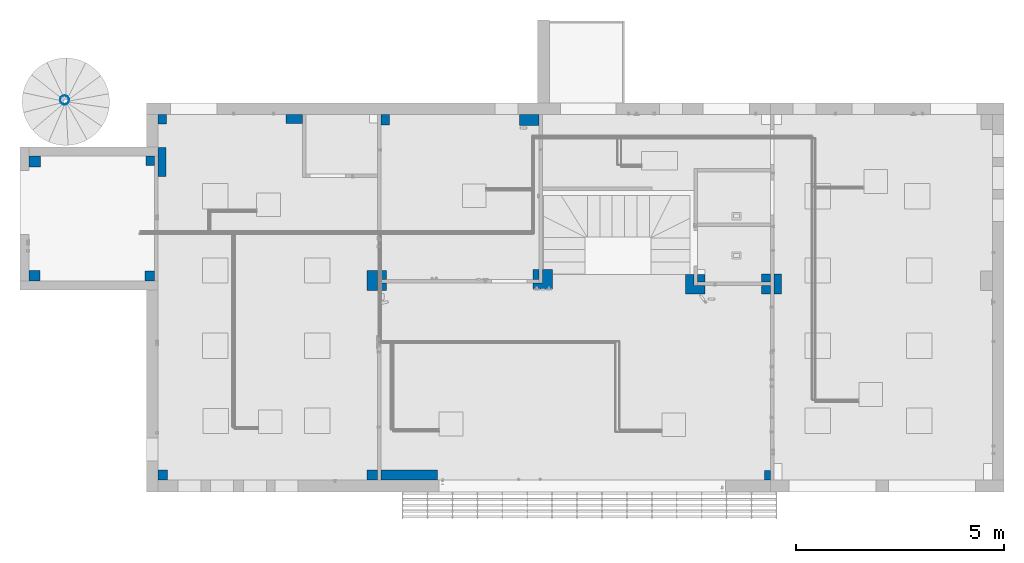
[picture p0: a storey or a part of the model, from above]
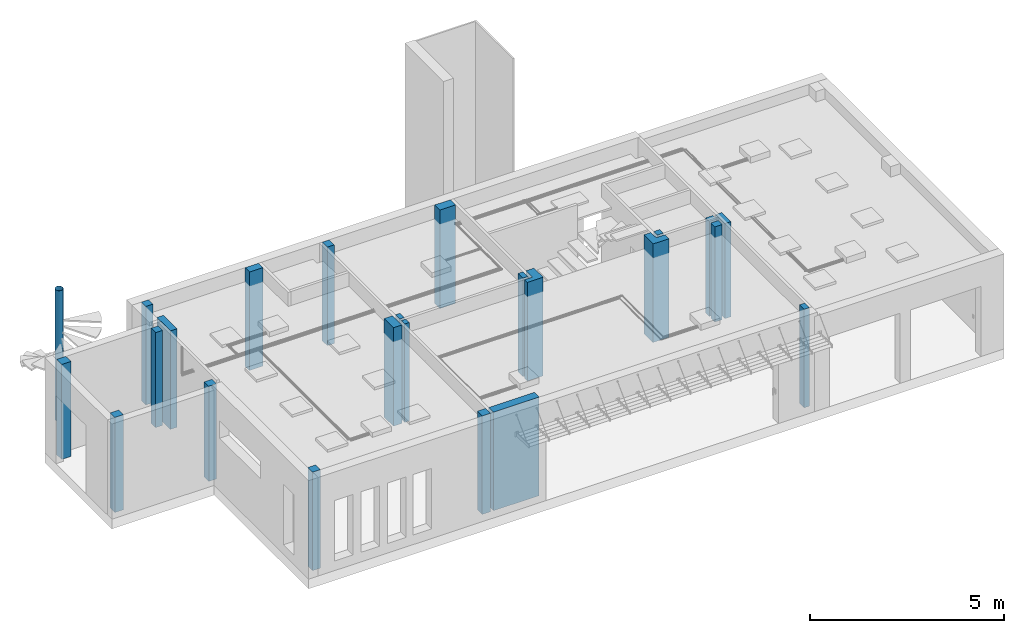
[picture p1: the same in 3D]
Properties of the parts of a building model (IFC2X3), part 1 of 5

# File
Description: ViewDefinition [CoordinationView_V2.0]
File name: Project Number
Time: 2023-02-07T13:56:00+02:00
Written by: ODA SDAI 22.12
Made in: 23.0.11.19 - Exporter 23.0.11.19 - Alternate UI 23.0.11.19

# IfcProject, Project Number
LongName: Project Name; Phase: Project Status

# IfcSite, Default
RefLatitude: 40, 38, 39, 763182; RefLongitude: 22, 55, 47, 232054; RefElevation: 0 mm
Pset_ProductRequirements - Category: Topography

# IfcSite: Surface:342065:342065 : Surface:342065, Surface:342065:342065 : Surface:342065:328022
Material: Earth 227
Pset_ProductRequirements - Category: Site

# IfcBuilding
Pset_BuildingCommon - NumberOfStoreys: 5
Pset_ProductRequirements - Category: Topography

# IfcBuildingStorey: Level:Circle Head - Project Datum (3)
Pset_ProductRequirements - Category: Levels
Name | LongName = Pset_AirSideSystemInformation, Name = Pset_ProductRequirements, Name | Elevation (mm)
Level 1 | Level 1 | 0
Level 2 | Level 2 | 3300
Top | Top | 6650

# IfcSpace: 10
In: Level 2
LongName: Bedroom First Floor; InteriorOrExteriorSpace: INTERNAL
Pset_AirSideSystemInformation - Name: Bedroom First Floor
Pset_ProductRequirements - Name: Bedroom First Floor; Category: Spaces
Pset_SpaceCommon - Reference: Bedroom First Floor 10; Category: Spaces

# IfcSpace: 11
In: Level 2
LongName: Game Room; InteriorOrExteriorSpace: INTERNAL
Pset_AirSideSystemInformation - Name: Game Room
Pset_ProductRequirements - Name: Game Room; Category: Spaces
Pset_SpaceCommon - Reference: Game Room 11; Category: Spaces

# IfcSpace: 12
In: Level 2
LongName: Double Bedroom; InteriorOrExteriorSpace: INTERNAL
Pset_AirSideSystemInformation - Name: Double Bedroom
Pset_ProductRequirements - Name: Double Bedroom; Category: Spaces
Pset_SpaceCommon - Reference: Double Bedroom 12; Category: Spaces

# IfcSpace: 13
In: Level 2
LongName: Bathroom Up; InteriorOrExteriorSpace: INTERNAL
Pset_AirSideSystemInformation - Name: Bathroom Up
Pset_ProductRequirements - Name: Bathroom Up; Category: Spaces
Pset_SpaceCommon - Reference: Bathroom Up 13; Category: Spaces

# IfcSpace: 15
In: Level 2
LongName: Hall up; InteriorOrExteriorSpace: INTERNAL
Pset_AirSideSystemInformation - Name: Hall up
Pset_ProductRequirements - Name: Hall up; Category: Spaces
Pset_SpaceCommon - Reference: Hall up 15; Category: Spaces

# IfcSpace: 2
In: Level 1
LongName: Control Room West; InteriorOrExteriorSpace: INTERNAL
Pset_AirSideSystemInformation - Name: Control Room West
Pset_ProductRequirements - Name: Control Room West; Category: Spaces
Pset_SpaceCommon - Reference: Control Room West 2; Category: Spaces

# IfcSpace: 3
In: Level 1
LongName: Bedroom; InteriorOrExteriorSpace: INTERNAL
Pset_AirSideSystemInformation - Name: Bedroom
Pset_ProductRequirements - Name: Bedroom; Category: Spaces
Pset_SpaceCommon - Reference: Bedroom 3; Category: Spaces

# IfcSpace: 33
In: Level 1
LongName: Plenum 1a; InteriorOrExteriorSpace: INTERNAL
Pset_AirSideSystemInformation - Name: Plenum 1a
Pset_ProductRequirements - Name: Plenum 1a; Category: Spaces
Pset_SpaceCommon - Reference: Plenum 1a 33; Category: Spaces

# IfcSpace: 34
In: Level 1
LongName: Plenum 1b; InteriorOrExteriorSpace: INTERNAL
Pset_AirSideSystemInformation - Name: Plenum 1b
Pset_ProductRequirements - Name: Plenum 1b; Category: Spaces
Pset_SpaceCommon - Reference: Plenum 1b 34; Category: Spaces

# IfcSpace: 35
In: Level 1
LongName: Plenum 1h; InteriorOrExteriorSpace: INTERNAL
Pset_AirSideSystemInformation - Name: Plenum 1h
Pset_ProductRequirements - Name: Plenum 1h; Category: Spaces
Pset_SpaceCommon - Reference: Plenum 1h 35; Category: Spaces

# IfcSpace: 36
In: Level 1
LongName: Plenum 1c; InteriorOrExteriorSpace: INTERNAL
Pset_AirSideSystemInformation - Name: Plenum 1c
Pset_ProductRequirements - Name: Plenum 1c; Category: Spaces
Pset_SpaceCommon - Reference: Plenum 1c 36; Category: Spaces

# IfcSpace: 37
In: Level 1
LongName: Plenum 1d; InteriorOrExteriorSpace: INTERNAL
Pset_AirSideSystemInformation - Name: Plenum 1d
Pset_ProductRequirements - Name: Plenum 1d; Category: Spaces
Pset_SpaceCommon - Reference: Plenum 1d 37; Category: Spaces

# IfcSpace: 38
In: Level 1
LongName: Plenum 1e; InteriorOrExteriorSpace: INTERNAL
Pset_AirSideSystemInformation - Name: Plenum 1e
Pset_ProductRequirements - Name: Plenum 1e; Category: Spaces
Pset_SpaceCommon - Reference: Plenum 1e 38; Category: Spaces

# IfcSpace: 39
In: Level 1
LongName: Plenum 1f; InteriorOrExteriorSpace: INTERNAL
Pset_AirSideSystemInformation - Name: Plenum 1f
Pset_ProductRequirements - Name: Plenum 1f; Category: Spaces
Pset_SpaceCommon - Reference: Plenum 1f 39; Category: Spaces

# IfcSpace: 4
In: Level 1
LongName: Living Room; InteriorOrExteriorSpace: INTERNAL
Pset_AirSideSystemInformation - Name: Living Room
Pset_ProductRequirements - Name: Living Room; Category: Spaces
Pset_SpaceCommon - Reference: Living Room 4; Category: Spaces

# IfcSpace: 40
In: Level 2
LongName: Plenum 2a; InteriorOrExteriorSpace: INTERNAL
Pset_AirSideSystemInformation - Name: Plenum 2a
Pset_ProductRequirements - Name: Plenum 2a; Category: Spaces
Pset_SpaceCommon - Reference: Plenum 2a 40; Category: Spaces

# IfcSpace: 41
In: Level 2
LongName: Plenum 2b; InteriorOrExteriorSpace: INTERNAL
Pset_AirSideSystemInformation - Name: Plenum 2b
Pset_ProductRequirements - Name: Plenum 2b; Category: Spaces
Pset_SpaceCommon - Reference: Plenum 2b 41; Category: Spaces

# IfcSpace: 42
In: Level 2
LongName: Plenum 2c; InteriorOrExteriorSpace: INTERNAL
Pset_AirSideSystemInformation - Name: Plenum 2c
Pset_ProductRequirements - Name: Plenum 2c; Category: Spaces
Pset_SpaceCommon - Reference: Plenum 2c 42; Category: Spaces

# IfcSpace: 43
In: Level 2
LongName: Plenum 2d; InteriorOrExteriorSpace: INTERNAL
Pset_AirSideSystemInformation - Name: Plenum 2d
Pset_ProductRequirements - Name: Plenum 2d; Category: Spaces
Pset_SpaceCommon - Reference: Plenum 2d 43; Category: Spaces

# IfcSpace: 44
In: Level 2
LongName: Plenum 2e; InteriorOrExteriorSpace: INTERNAL
Pset_AirSideSystemInformation - Name: Plenum 2e
Pset_ProductRequirements - Name: Plenum 2e; Category: Spaces
Pset_SpaceCommon - Reference: Plenum 2e 44; Category: Spaces

# IfcSpace: 45
In: Level 2
LongName: Plenum 2f; InteriorOrExteriorSpace: INTERNAL
Pset_AirSideSystemInformation - Name: Plenum 2f
Pset_ProductRequirements - Name: Plenum 2f; Category: Spaces
Pset_SpaceCommon - Reference: Plenum 2f 45; Category: Spaces

# IfcSpace: 46
In: Level 1
LongName: Plenum 1g; InteriorOrExteriorSpace: INTERNAL
Pset_AirSideSystemInformation - Name: Plenum 1g
Pset_ProductRequirements - Name: Plenum 1g; Category: Spaces
Pset_SpaceCommon - Reference: Plenum 1g 46; Category: Spaces

# IfcSpace: 47
In: Level 1
LongName: Stairs; InteriorOrExteriorSpace: INTERNAL
Pset_AirSideSystemInformation - Name: Stairs
Pset_ProductRequirements - Name: Stairs; Category: Spaces
Pset_SpaceCommon - Reference: Stairs 47; Category: Spaces

# IfcSpace: 48
In: Level 1
LongName: Engine Room; InteriorOrExteriorSpace: INTERNAL
Pset_AirSideSystemInformation - Name: Engine Room
Pset_ProductRequirements - Name: Engine Room; Category: Spaces
Pset_SpaceCommon - Reference: Engine Room 48; Category: Spaces

# IfcSpace: 49
In: Level 1
LongName: Space; InteriorOrExteriorSpace: INTERNAL
Pset_AirSideSystemInformation - Name: Space
Pset_ProductRequirements - Name: Space; Category: Spaces
Pset_SpaceCommon - Reference: Space 49; Category: Spaces

# IfcSpace: 5
In: Level 1
LongName: WC1; InteriorOrExteriorSpace: INTERNAL
Pset_AirSideSystemInformation - Name: WC1
Pset_ProductRequirements - Name: WC1; Category: Spaces
Pset_SpaceCommon - Reference: WC1 5; Category: Spaces

# IfcSpace: 6
In: Level 1
LongName: WC2; InteriorOrExteriorSpace: INTERNAL
Pset_AirSideSystemInformation - Name: WC2
Pset_ProductRequirements - Name: WC2; Category: Spaces
Pset_SpaceCommon - Reference: WC2 6; Category: Spaces

# IfcSpace: 7
In: Level 1
LongName: WC3; InteriorOrExteriorSpace: INTERNAL
Pset_AirSideSystemInformation - Name: WC3
Pset_ProductRequirements - Name: WC3; Category: Spaces
Pset_SpaceCommon - Reference: WC3 7; Category: Spaces

# IfcSpace: 9
In: Level 2
LongName: Demo Room; InteriorOrExteriorSpace: INTERNAL
Pset_AirSideSystemInformation - Name: Demo Room
Pset_ProductRequirements - Name: Demo Room; Category: Spaces
Pset_SpaceCommon - Reference: Demo Room 9; Category: Spaces

# IfcBuildingElementProxy: Alumil Chic no lock:Alumil Chic no lock:1027049:Alumil Chic no lock:1027049 : Alumil Chic no lock:Alumil Chic no lock:1027049:326691, Alumil Chic no lock:Alumil Chic no lock:1027049:Alumil Chic no lock:1027049 : Alumil Chic no lock:Alumil Chic no lock:1027049:326691:Alumil Chic no lock:1027049:Alumil Chic no lock:1027049 : Alumil Chic no lock:Alumil Chic no lock:1027049:326691 : Alumil Chic no lock:Alumil Chic no lock:1027049:Alumil Chic no lock:1027049 : Alumil Chic no lock:Alumil Chic no lock:1027049:326691:326029
In: Level 2
Type - Material: Polished Steel (5)
Type - Pset_BuildingElementProxyCommon - Reference: Alumil Chic no lock
Type - Pset_ProductRequirements - Category: Generic Models
Type - Pset_QuantityTakeOff - Reference: Alumil Chic no lock
Type - Pset_ProvisionForVoid - Width: 34 mm; Height: 14.0853 mm; Depth: 14.0853 mm
Pset_BuildingElementProxyCommon - sets with these values: 2
Pset_ProvisionForVoid - Width: 0.0103632 mm

# IfcBuildingElementProxy: Alumil Chic:Alumil Chic:1027241:Alumil Chic:1027241 : Alumil Chic:Alumil Chic:1027241:322622, Alumil Chic:Alumil Chic:1027241:Alumil Chic:1027241 : Alumil Chic:Alumil Chic:1027241:322622:Alumil Chic:1027241:Alumil Chic:1027241 : Alumil Chic:Alumil Chic:1027241:322622 : Alumil Chic:Alumil Chic:1027241:Alumil Chic:1027241 : Alumil Chic:Alumil Chic:1027241:322622:322399
In: Level 1
Type - Material: Polished Steel (9)
Type - Pset_BuildingElementProxyCommon - Reference: Alumil Chic
Type - Pset_ProductRequirements - Category: Generic Models
Type - Pset_QuantityTakeOff - Reference: Alumil Chic
Type - Pset_ProvisionForVoid - Width: 126.361 mm; Height: 34 mm; Depth: 4.01325 mm
Pset_BuildingElementProxyCommon - sets with these values: 2
Pset_ProvisionForVoid - Width: 0.038515 mm

# IfcBuildingElementProxy: Alumil Chic:Alumil Chic:1027242:Alumil Chic:1027242 : Alumil Chic:Alumil Chic:1027242:322710, Alumil Chic:Alumil Chic:1027242:Alumil Chic:1027242 : Alumil Chic:Alumil Chic:1027242:322710:Alumil Chic:1027242:Alumil Chic:1027242 : Alumil Chic:Alumil Chic:1027242:322710 : Alumil Chic:Alumil Chic:1027242:Alumil Chic:1027242 : Alumil Chic:Alumil Chic:1027242:322710:322488
In: Level 1
Type - Material: Polished Steel (9)
Type - Pset_BuildingElementProxyCommon - Reference: Alumil Chic
Type - Pset_ProductRequirements - Category: Generic Models
Type - Pset_QuantityTakeOff - Reference: Alumil Chic
Type - Pset_ProvisionForVoid - Width: 126.361 mm; Height: 34 mm; Depth: 4.01325 mm
Pset_BuildingElementProxyCommon - sets with these values: 2
Pset_ProvisionForVoid - Width: 0.038515 mm

# IfcBuildingElementProxy: Camera ORBBEC v1:Camera ORBBEC v1:1027540:Camera ORBBEC v1:1027540 : Camera ORBBEC v1:Camera ORBBEC v1:1027540:324731, Camera ORBBEC v1:Camera ORBBEC v1:1027540:Camera ORBBEC v1:1027540 : Camera ORBBEC v1:Camera ORBBEC v1:1027540:324731:Camera ORBBEC v1:1027540:Camera ORBBEC v1:1027540 : Camera ORBBEC v1:Camera ORBBEC v1:1027540:324731 : Camera ORBBEC v1:Camera ORBBEC v1:1027540:Camera ORBBEC v1:1027540 : Camera ORBBEC v1:Camera ORBBEC v1:1027540:324731:325063
In: Level 1
Type - Material: Plastic - Sony - Black_Matt (4)
Type - Pset_BuildingElementProxyCommon - Reference: Camera ORBBEC v1
Type - Pset_ManufacturerTypeInformation - Manufacturer: Orbbec
Type - Pset_ProductRequirements - Category: Specialty Equipment
Type - Pset_QuantityTakeOff - Reference: Camera ORBBEC v1
Type - Pset_ProvisionForVoid - Depth: 2 mm
Pset_BuildingElementProxyCommon - sets with these values: 2
Pset_ProductRequirements - Category: Generic Models

# IfcBuildingElementProxy: Camera ORBBEC v1:Camera ORBBEC v1:1027541:Camera ORBBEC v1:1027541 : Camera ORBBEC v1:Camera ORBBEC v1:1027541:324770, Camera ORBBEC v1:Camera ORBBEC v1:1027541:Camera ORBBEC v1:1027541 : Camera ORBBEC v1:Camera ORBBEC v1:1027541:324770:Camera ORBBEC v1:1027541:Camera ORBBEC v1:1027541 : Camera ORBBEC v1:Camera ORBBEC v1:1027541:324770 : Camera ORBBEC v1:Camera ORBBEC v1:1027541:Camera ORBBEC v1:1027541 : Camera ORBBEC v1:Camera ORBBEC v1:1027541:324770:325102
In: Level 1
Type - Material: Plastic - Sony - Black_Matt (4)
Type - Pset_BuildingElementProxyCommon - Reference: Camera ORBBEC v1
Type - Pset_ManufacturerTypeInformation - Manufacturer: Orbbec
Type - Pset_ProductRequirements - Category: Specialty Equipment
Type - Pset_QuantityTakeOff - Reference: Camera ORBBEC v1
Type - Pset_ProvisionForVoid - Depth: 2 mm
Pset_BuildingElementProxyCommon - sets with these values: 2
Pset_ProductRequirements - Category: Generic Models

# IfcBuildingElementProxy: Camera ORBBEC v1:Camera ORBBEC v1:1027546:Camera ORBBEC v1:1027546 : Camera ORBBEC v1:Camera ORBBEC v1:1027546:324823, Camera ORBBEC v1:Camera ORBBEC v1:1027546:Camera ORBBEC v1:1027546 : Camera ORBBEC v1:Camera ORBBEC v1:1027546:324823:Camera ORBBEC v1:1027546:Camera ORBBEC v1:1027546 : Camera ORBBEC v1:Camera ORBBEC v1:1027546:324823 : Camera ORBBEC v1:Camera ORBBEC v1:1027546:Camera ORBBEC v1:1027546 : Camera ORBBEC v1:Camera ORBBEC v1:1027546:324823:325155
In: Level 1
Type - Material: Plastic - Sony - Black_Matt (4)
Type - Pset_BuildingElementProxyCommon - Reference: Camera ORBBEC v1
Type - Pset_ManufacturerTypeInformation - Manufacturer: Orbbec
Type - Pset_ProductRequirements - Category: Specialty Equipment
Type - Pset_QuantityTakeOff - Reference: Camera ORBBEC v1
Type - Pset_ProvisionForVoid - Depth: 2 mm
Pset_BuildingElementProxyCommon - sets with these values: 2
Pset_ProductRequirements - Category: Generic Models

# IfcBuildingElementProxy: Camera ORBBEC v1:Camera ORBBEC v1:1027547:Camera ORBBEC v1:1027547 : Camera ORBBEC v1:Camera ORBBEC v1:1027547:324862, Camera ORBBEC v1:Camera ORBBEC v1:1027547:Camera ORBBEC v1:1027547 : Camera ORBBEC v1:Camera ORBBEC v1:1027547:324862:Camera ORBBEC v1:1027547:Camera ORBBEC v1:1027547 : Camera ORBBEC v1:Camera ORBBEC v1:1027547:324862 : Camera ORBBEC v1:Camera ORBBEC v1:1027547:Camera ORBBEC v1:1027547 : Camera ORBBEC v1:Camera ORBBEC v1:1027547:324862:325194
In: Level 1
Type - Material: Plastic - Sony - Black_Matt (4)
Type - Pset_BuildingElementProxyCommon - Reference: Camera ORBBEC v1
Type - Pset_ManufacturerTypeInformation - Manufacturer: Orbbec
Type - Pset_ProductRequirements - Category: Specialty Equipment
Type - Pset_QuantityTakeOff - Reference: Camera ORBBEC v1
Type - Pset_ProvisionForVoid - Depth: 2 mm
Pset_BuildingElementProxyCommon - sets with these values: 2
Pset_ProductRequirements - Category: Generic Models

# IfcBuildingElementProxy: Camera ORBBEC v1:Camera ORBBEC v1:1027552:Camera ORBBEC v1:1027552 : Camera ORBBEC v1:Camera ORBBEC v1:1027552:324015, Camera ORBBEC v1:Camera ORBBEC v1:1027552:Camera ORBBEC v1:1027552 : Camera ORBBEC v1:Camera ORBBEC v1:1027552:324015:Camera ORBBEC v1:1027552:Camera ORBBEC v1:1027552 : Camera ORBBEC v1:Camera ORBBEC v1:1027552:324015 : Camera ORBBEC v1:Camera ORBBEC v1:1027552:Camera ORBBEC v1:1027552 : Camera ORBBEC v1:Camera ORBBEC v1:1027552:324015:324971
In: Level 1
Type - Material: Plastic - Sony - Black_Matt (4)
Type - Pset_BuildingElementProxyCommon - Reference: Camera ORBBEC v1
Type - Pset_ManufacturerTypeInformation - Manufacturer: Orbbec
Type - Pset_ProductRequirements - Category: Specialty Equipment
Type - Pset_QuantityTakeOff - Reference: Camera ORBBEC v1
Type - Pset_ProvisionForVoid - Depth: 2 mm
Pset_BuildingElementProxyCommon - sets with these values: 2
Pset_ProductRequirements - Category: Generic Models

# IfcBuildingElementProxy: Compound Ceiling:My ceiling mineral fiber mpania:1026756:My ceiling mineral fiber mpania:1026756 : Compound Ceiling:My ceiling mineral fiber mpania:1026756:321788, Compound Ceiling:My ceiling mineral fiber mpania:1026756:My ceiling mineral fiber mpania:1026756 : Compound Ceiling:My ceiling mineral fiber mpania:1026756:321788:My ceiling mineral fiber mpania:1026756:My ceiling mineral fiber mpania:1026756 : Compound Ceiling:My ceiling mineral fiber mpania:1026756:321788 : Compound Ceiling:My ceiling mineral fiber mpania:1026756:My ceiling mineral fiber mpania:1026756 : Compound Ceiling:My ceiling mineral fiber mpania:1026756:321788:321591
In: Level 1
Type - Material: Ceiling Tile 600 x 600
Type - Pset_BuildingElementProxyCommon - Reference: My ceiling mineral fiber mpania
Type - Pset_ProductRequirements - Category: Ceilings
Type - Pset_QuantityTakeOff - Reference: My ceiling mineral fiber mpania
Type - Pset_ProvisionForVoid - Depth: 57 mm
Pset_BuildingElementProxyCommon - sets with these values: 2
Pset_ProductRequirements - Category: Generic Models

# IfcBuildingElementProxy: Compound Ceiling:My ceiling mineral fiber mpania:1026769:My ceiling mineral fiber mpania:1026769 : Compound Ceiling:My ceiling mineral fiber mpania:1026769:321804, Compound Ceiling:My ceiling mineral fiber mpania:1026769:My ceiling mineral fiber mpania:1026769 : Compound Ceiling:My ceiling mineral fiber mpania:1026769:321804:My ceiling mineral fiber mpania:1026769:My ceiling mineral fiber mpania:1026769 : Compound Ceiling:My ceiling mineral fiber mpania:1026769:321804 : Compound Ceiling:My ceiling mineral fiber mpania:1026769:My ceiling mineral fiber mpania:1026769 : Compound Ceiling:My ceiling mineral fiber mpania:1026769:321804:321607
In: Level 1
Type - Material: Ceiling Tile 600 x 600
Type - Pset_BuildingElementProxyCommon - Reference: My ceiling mineral fiber mpania
Type - Pset_ProductRequirements - Category: Ceilings
Type - Pset_QuantityTakeOff - Reference: My ceiling mineral fiber mpania
Type - Pset_ProvisionForVoid - Depth: 57 mm
Pset_BuildingElementProxyCommon - sets with these values: 2
Pset_ProductRequirements - Category: Generic Models

# IfcBuildingElementProxy: Compound Ceiling:My ceiling mineral fiber mpania:1026845:My ceiling mineral fiber mpania:1026845 : Compound Ceiling:My ceiling mineral fiber mpania:1026845:326623, Compound Ceiling:My ceiling mineral fiber mpania:1026845:My ceiling mineral fiber mpania:1026845 : Compound Ceiling:My ceiling mineral fiber mpania:1026845:326623:My ceiling mineral fiber mpania:1026845:My ceiling mineral fiber mpania:1026845 : Compound Ceiling:My ceiling mineral fiber mpania:1026845:326623 : Compound Ceiling:My ceiling mineral fiber mpania:1026845:My ceiling mineral fiber mpania:1026845 : Compound Ceiling:My ceiling mineral fiber mpania:1026845:326623:325963
In: Level 2
Type - Material: Ceiling Tile 600 x 600
Type - Pset_BuildingElementProxyCommon - Reference: My ceiling mineral fiber mpania
Type - Pset_ProductRequirements - Category: Ceilings
Type - Pset_QuantityTakeOff - Reference: My ceiling mineral fiber mpania
Type - Pset_ProvisionForVoid - Depth: 57 mm
Pset_BuildingElementProxyCommon - sets with these values: 2
Pset_ProductRequirements - Category: Generic Models

# IfcBuildingElementProxy: Compound Ceiling:My ceiling mineral fiber:1026741:My ceiling mineral fiber:1026741 : Compound Ceiling:My ceiling mineral fiber:1026741:321752, Compound Ceiling:My ceiling mineral fiber:1026741:My ceiling mineral fiber:1026741 : Compound Ceiling:My ceiling mineral fiber:1026741:321752:My ceiling mineral fiber:1026741:My ceiling mineral fiber:1026741 : Compound Ceiling:My ceiling mineral fiber:1026741:321752 : Compound Ceiling:My ceiling mineral fiber:1026741:My ceiling mineral fiber:1026741 : Compound Ceiling:My ceiling mineral fiber:1026741:321752:321562
In: Level 1
Type - Material: Ceiling Tile 600 x 600
Type - Pset_BuildingElementProxyCommon - Reference: My ceiling mineral fiber
Type - Pset_ProductRequirements - Category: Ceilings
Type - Pset_QuantityTakeOff - Reference: My ceiling mineral fiber
Type - Pset_ProvisionForVoid - Depth: 57 mm
Pset_BuildingElementProxyCommon - sets with these values: 2
Pset_ProductRequirements - Category: Generic Models

# IfcBuildingElementProxy: Compound Ceiling:My ceiling mineral fiber:1026780:My ceiling mineral fiber:1026780 : Compound Ceiling:My ceiling mineral fiber:1026780:326517, Compound Ceiling:My ceiling mineral fiber:1026780:My ceiling mineral fiber:1026780 : Compound Ceiling:My ceiling mineral fiber:1026780:326517:My ceiling mineral fiber:1026780:My ceiling mineral fiber:1026780 : Compound Ceiling:My ceiling mineral fiber:1026780:326517 : Compound Ceiling:My ceiling mineral fiber:1026780:My ceiling mineral fiber:1026780 : Compound Ceiling:My ceiling mineral fiber:1026780:326517:325857
In: Level 2
Type - Material: Ceiling Tile 600 x 600
Type - Pset_BuildingElementProxyCommon - Reference: My ceiling mineral fiber
Type - Pset_ProductRequirements - Category: Ceilings
Type - Pset_QuantityTakeOff - Reference: My ceiling mineral fiber
Type - Pset_ProvisionForVoid - Depth: 57 mm
Pset_BuildingElementProxyCommon - sets with these values: 2
Pset_ProductRequirements - Category: Generic Models

# IfcBuildingElementProxy: Compound Ceiling:My ceiling mineral fiber:1026814:My ceiling mineral fiber:1026814 : Compound Ceiling:My ceiling mineral fiber:1026814:326583, Compound Ceiling:My ceiling mineral fiber:1026814:My ceiling mineral fiber:1026814 : Compound Ceiling:My ceiling mineral fiber:1026814:326583:My ceiling mineral fiber:1026814:My ceiling mineral fiber:1026814 : Compound Ceiling:My ceiling mineral fiber:1026814:326583 : Compound Ceiling:My ceiling mineral fiber:1026814:My ceiling mineral fiber:1026814 : Compound Ceiling:My ceiling mineral fiber:1026814:326583:325923
In: Level 2
Type - Material: Ceiling Tile 600 x 600
Type - Pset_BuildingElementProxyCommon - Reference: My ceiling mineral fiber
Type - Pset_ProductRequirements - Category: Ceilings
Type - Pset_QuantityTakeOff - Reference: My ceiling mineral fiber
Type - Pset_ProvisionForVoid - Depth: 57 mm
Pset_BuildingElementProxyCommon - sets with these values: 2
Pset_ProductRequirements - Category: Generic Models

# IfcBuildingElementProxy: Compound Ceiling:My ceiling mineral fiber:1026827:My ceiling mineral fiber:1026827 : Compound Ceiling:My ceiling mineral fiber:1026827:326603, Compound Ceiling:My ceiling mineral fiber:1026827:My ceiling mineral fiber:1026827 : Compound Ceiling:My ceiling mineral fiber:1026827:326603:My ceiling mineral fiber:1026827:My ceiling mineral fiber:1026827 : Compound Ceiling:My ceiling mineral fiber:1026827:326603 : Compound Ceiling:My ceiling mineral fiber:1026827:My ceiling mineral fiber:1026827 : Compound Ceiling:My ceiling mineral fiber:1026827:326603:325943
In: Level 2
Type - Material: Ceiling Tile 600 x 600
Type - Pset_BuildingElementProxyCommon - Reference: My ceiling mineral fiber
Type - Pset_ProductRequirements - Category: Ceilings
Type - Pset_QuantityTakeOff - Reference: My ceiling mineral fiber
Type - Pset_ProvisionForVoid - Depth: 57 mm
Pset_BuildingElementProxyCommon - sets with these values: 2
Pset_ProductRequirements - Category: Generic Models

# IfcBuildingElementProxy: Compound Ceiling:My ceiling mineral fiber:1026868:My ceiling mineral fiber:1026868 : Compound Ceiling:My ceiling mineral fiber:1026868:326647, Compound Ceiling:My ceiling mineral fiber:1026868:My ceiling mineral fiber:1026868 : Compound Ceiling:My ceiling mineral fiber:1026868:326647:My ceiling mineral fiber:1026868:My ceiling mineral fiber:1026868 : Compound Ceiling:My ceiling mineral fiber:1026868:326647 : Compound Ceiling:My ceiling mineral fiber:1026868:My ceiling mineral fiber:1026868 : Compound Ceiling:My ceiling mineral fiber:1026868:326647:325987
In: Level 2
Type - Material: Ceiling Tile 600 x 600
Type - Pset_BuildingElementProxyCommon - Reference: My ceiling mineral fiber
Type - Pset_ProductRequirements - Category: Ceilings
Type - Pset_QuantityTakeOff - Reference: My ceiling mineral fiber
Type - Pset_ProvisionForVoid - Depth: 57 mm
Pset_BuildingElementProxyCommon - sets with these values: 2
Pset_ProductRequirements - Category: Generic Models

# IfcBuildingElementProxy: Compound Ceiling:My ceiling mineral fiber:1026892:My ceiling mineral fiber:1026892 : Compound Ceiling:My ceiling mineral fiber:1026892:326669, Compound Ceiling:My ceiling mineral fiber:1026892:My ceiling mineral fiber:1026892 : Compound Ceiling:My ceiling mineral fiber:1026892:326669:My ceiling mineral fiber:1026892:My ceiling mineral fiber:1026892 : Compound Ceiling:My ceiling mineral fiber:1026892:326669 : Compound Ceiling:My ceiling mineral fiber:1026892:My ceiling mineral fiber:1026892 : Compound Ceiling:My ceiling mineral fiber:1026892:326669:326009
In: Level 2
Type - Material: Ceiling Tile 600 x 600
Type - Pset_BuildingElementProxyCommon - Reference: My ceiling mineral fiber
Type - Pset_ProductRequirements - Category: Ceilings
Type - Pset_QuantityTakeOff - Reference: My ceiling mineral fiber
Type - Pset_ProvisionForVoid - Depth: 57 mm
Pset_BuildingElementProxyCommon - sets with these values: 2
Pset_ProductRequirements - Category: Generic Models

# IfcBuildingElementProxy: Compound Ceiling:My ceiling mineral fiber:1026909:My ceiling mineral fiber:1026909 : Compound Ceiling:My ceiling mineral fiber:1026909:321822, Compound Ceiling:My ceiling mineral fiber:1026909:My ceiling mineral fiber:1026909 : Compound Ceiling:My ceiling mineral fiber:1026909:321822:My ceiling mineral fiber:1026909:My ceiling mineral fiber:1026909 : Compound Ceiling:My ceiling mineral fiber:1026909:321822 : Compound Ceiling:My ceiling mineral fiber:1026909:My ceiling mineral fiber:1026909 : Compound Ceiling:My ceiling mineral fiber:1026909:321822:321625
In: Level 1
Type - Material: Ceiling Tile 600 x 600
Type - Pset_BuildingElementProxyCommon - Reference: My ceiling mineral fiber
Type - Pset_ProductRequirements - Category: Ceilings
Type - Pset_QuantityTakeOff - Reference: My ceiling mineral fiber
Type - Pset_ProvisionForVoid - Depth: 57 mm
Pset_BuildingElementProxyCommon - sets with these values: 2
Pset_ProductRequirements - Category: Generic Models

# IfcBuildingElementProxy: Compound Ceiling:My ceiling mineral fiber:1027013:My ceiling mineral fiber:1027013 : Compound Ceiling:My ceiling mineral fiber:1027013:321842, Compound Ceiling:My ceiling mineral fiber:1027013:My ceiling mineral fiber:1027013 : Compound Ceiling:My ceiling mineral fiber:1027013:321842:My ceiling mineral fiber:1027013:My ceiling mineral fiber:1027013 : Compound Ceiling:My ceiling mineral fiber:1027013:321842 : Compound Ceiling:My ceiling mineral fiber:1027013:My ceiling mineral fiber:1027013 : Compound Ceiling:My ceiling mineral fiber:1027013:321842:321645
In: Level 1
Type - Material: Ceiling Tile 600 x 600
Type - Pset_BuildingElementProxyCommon - Reference: My ceiling mineral fiber
Type - Pset_ProductRequirements - Category: Ceilings
Type - Pset_QuantityTakeOff - Reference: My ceiling mineral fiber
Type - Pset_ProvisionForVoid - Width: 1225.48 mm; Height: 1759 mm; Depth: 57 mm
Pset_BuildingElementProxyCommon - sets with these values: 2
Pset_ProductRequirements - Category: Generic Models
Pset_ProvisionForVoid - Width: 0.373527 mm

# IfcBuildingElementProxy: Compound Ceiling:My ceiling mineral fiber:1027159:My ceiling mineral fiber:1027159 : Compound Ceiling:My ceiling mineral fiber:1027159:322520, Compound Ceiling:My ceiling mineral fiber:1027159:My ceiling mineral fiber:1027159 : Compound Ceiling:My ceiling mineral fiber:1027159:322520:My ceiling mineral fiber:1027159:My ceiling mineral fiber:1027159 : Compound Ceiling:My ceiling mineral fiber:1027159:322520 : Compound Ceiling:My ceiling mineral fiber:1027159:My ceiling mineral fiber:1027159 : Compound Ceiling:My ceiling mineral fiber:1027159:322520:322307
In: Level 1
Type - Material: Ceiling Tile 600 x 600
Type - Pset_BuildingElementProxyCommon - Reference: My ceiling mineral fiber
Type - Pset_ProductRequirements - Category: Ceilings
Type - Pset_QuantityTakeOff - Reference: My ceiling mineral fiber
Type - Pset_ProvisionForVoid - Depth: 57 mm
Pset_BuildingElementProxyCommon - sets with these values: 2
Pset_ProductRequirements - Category: Generic Models

# IfcBuildingElementProxy: Compound Ceiling:My ceiling mineral fiber:1027182:My ceiling mineral fiber:1027182 : Compound Ceiling:My ceiling mineral fiber:1027182:322582, Compound Ceiling:My ceiling mineral fiber:1027182:My ceiling mineral fiber:1027182 : Compound Ceiling:My ceiling mineral fiber:1027182:322582:My ceiling mineral fiber:1027182:My ceiling mineral fiber:1027182 : Compound Ceiling:My ceiling mineral fiber:1027182:322582 : Compound Ceiling:My ceiling mineral fiber:1027182:My ceiling mineral fiber:1027182 : Compound Ceiling:My ceiling mineral fiber:1027182:322582:322369
In: Level 1
Type - Material: Ceiling Tile 600 x 600
Type - Pset_BuildingElementProxyCommon - Reference: My ceiling mineral fiber
Type - Pset_ProductRequirements - Category: Ceilings
Type - Pset_QuantityTakeOff - Reference: My ceiling mineral fiber
Type - Pset_ProvisionForVoid - Depth: 57 mm
Pset_BuildingElementProxyCommon - sets with these values: 2
Pset_ProductRequirements - Category: Generic Models

# IfcBuildingElementProxy: Compound Ceiling:My ceiling mineral fiber:1027328:My ceiling mineral fiber:1027328 : Compound Ceiling:My ceiling mineral fiber:1027328:322800, Compound Ceiling:My ceiling mineral fiber:1027328:My ceiling mineral fiber:1027328 : Compound Ceiling:My ceiling mineral fiber:1027328:322800:My ceiling mineral fiber:1027328:My ceiling mineral fiber:1027328 : Compound Ceiling:My ceiling mineral fiber:1027328:322800 : Compound Ceiling:My ceiling mineral fiber:1027328:My ceiling mineral fiber:1027328 : Compound Ceiling:My ceiling mineral fiber:1027328:322800:322576
In: Level 1
Type - Material: Ceiling Tile 600 x 600
Type - Pset_BuildingElementProxyCommon - Reference: My ceiling mineral fiber
Type - Pset_ProductRequirements - Category: Ceilings
Type - Pset_QuantityTakeOff - Reference: My ceiling mineral fiber
Type - Pset_ProvisionForVoid - Depth: 57 mm
Pset_BuildingElementProxyCommon - sets with these values: 2
Pset_ProductRequirements - Category: Generic Models

# IfcBuildingElementProxy: Electrical_Controls_Fibaro_Motion-sensor.eng:Default:1027543:Default:1027543 : Electrical_Controls_Fibaro_Motion-sensor.eng:Default:1027543:324809, Electrical_Controls_Fibaro_Motion-sensor.eng:Default:1027543:Default:1027543 : Electrical_Controls_Fibaro_Motion-sensor.eng:Default:1027543:324809:Default:1027543:Default:1027543 : Electrical_Controls_Fibaro_Motion-sensor.eng:Default:1027543:324809 : Electrical_Controls_Fibaro_Motion-sensor.eng:Default:1027543:Default:1027543 : Electrical_Controls_Fibaro_Motion-sensor.eng:Default:1027543:324809:325141
In: Level 1
Type - Material: Fibaro_glossywhite 7ECA5D70
Type - Pset_BuildingElementProxyCommon - Reference: Default
Type - Pset_ProductRequirements - Category: Electrical Equipment
Type - Pset_QuantityTakeOff - Reference: Default
Material: Fibaro_blue 127BC1BD, Fibaro_transparent 1B44B9A5, Fibaro_glossywhite 7ECA5D70
Pset_BuildingElementProxyCommon - sets with these values: 2
Pset_ProductRequirements - Category: Generic Models

# IfcBuildingElementProxy: Electrical_Controls_Fibaro_Motion-sensor.eng:Default:1027545:Default:1027545 : Electrical_Controls_Fibaro_Motion-sensor.eng:Default:1027545:324816, Electrical_Controls_Fibaro_Motion-sensor.eng:Default:1027545:Default:1027545 : Electrical_Controls_Fibaro_Motion-sensor.eng:Default:1027545:324816:Default:1027545:Default:1027545 : Electrical_Controls_Fibaro_Motion-sensor.eng:Default:1027545:324816 : Electrical_Controls_Fibaro_Motion-sensor.eng:Default:1027545:Default:1027545 : Electrical_Controls_Fibaro_Motion-sensor.eng:Default:1027545:324816:325148
In: Level 1
Type - Material: Fibaro_glossywhite 7ECA5D70
Type - Pset_BuildingElementProxyCommon - Reference: Default
Type - Pset_ProductRequirements - Category: Electrical Equipment
Type - Pset_QuantityTakeOff - Reference: Default
Material: Fibaro_blue 127BC1BD, Fibaro_transparent 1B44B9A5, Fibaro_glossywhite 7ECA5D70
Pset_BuildingElementProxyCommon - sets with these values: 2
Pset_ProductRequirements - Category: Generic Models

# IfcBuildingElementProxy: Electrical_Controls_Fibaro_Motion-sensor.eng:Default:1027550:Default:1027550 : Electrical_Controls_Fibaro_Motion-sensor.eng:Default:1027550:324931, Electrical_Controls_Fibaro_Motion-sensor.eng:Default:1027550:Default:1027550 : Electrical_Controls_Fibaro_Motion-sensor.eng:Default:1027550:324931:Default:1027550:Default:1027550 : Electrical_Controls_Fibaro_Motion-sensor.eng:Default:1027550:324931 : Electrical_Controls_Fibaro_Motion-sensor.eng:Default:1027550:Default:1027550 : Electrical_Controls_Fibaro_Motion-sensor.eng:Default:1027550:324931:325263
In: Level 1
Type - Material: Fibaro_glossywhite 7ECA5D70
Type - Pset_BuildingElementProxyCommon - Reference: Default
Type - Pset_ProductRequirements - Category: Electrical Equipment
Type - Pset_QuantityTakeOff - Reference: Default
Material: Fibaro_blue 127BC1BD, Fibaro_transparent 1B44B9A5, Fibaro_glossywhite 7ECA5D70
Pset_BuildingElementProxyCommon - sets with these values: 2
Pset_ProductRequirements - Category: Generic Models

# IfcBuildingElementProxy: Electrical_Controls_Fibaro_Motion-sensor.eng:Default:1027556:Default:1027556 : Electrical_Controls_Fibaro_Motion-sensor.eng:Default:1027556:324090, Electrical_Controls_Fibaro_Motion-sensor.eng:Default:1027556:Default:1027556 : Electrical_Controls_Fibaro_Motion-sensor.eng:Default:1027556:324090:Default:1027556:Default:1027556 : Electrical_Controls_Fibaro_Motion-sensor.eng:Default:1027556:324090 : Electrical_Controls_Fibaro_Motion-sensor.eng:Default:1027556:Default:1027556 : Electrical_Controls_Fibaro_Motion-sensor.eng:Default:1027556:324090:325046
In: Level 1
Type - Material: Fibaro_glossywhite 7ECA5D70
Type - Pset_BuildingElementProxyCommon - Reference: Default
Type - Pset_ProductRequirements - Category: Electrical Equipment
Type - Pset_QuantityTakeOff - Reference: Default
Material: Fibaro_blue 127BC1BD, Fibaro_transparent 1B44B9A5, Fibaro_glossywhite 7ECA5D70
Pset_BuildingElementProxyCommon - sets with these values: 2
Pset_ProductRequirements - Category: Generic Models

# IfcBuildingElementProxy: Electrical_Controls_Fibaro_Motion-sensor.eng:Default:1027557:Default:1027557 : Electrical_Controls_Fibaro_Motion-sensor.eng:Default:1027557:324118, Electrical_Controls_Fibaro_Motion-sensor.eng:Default:1027557:Default:1027557 : Electrical_Controls_Fibaro_Motion-sensor.eng:Default:1027557:324118:Default:1027557:Default:1027557 : Electrical_Controls_Fibaro_Motion-sensor.eng:Default:1027557:324118 : Electrical_Controls_Fibaro_Motion-sensor.eng:Default:1027557:Default:1027557 : Electrical_Controls_Fibaro_Motion-sensor.eng:Default:1027557:324118:325056
In: Level 1
Type - Material: Fibaro_glossywhite 7ECA5D70
Type - Pset_BuildingElementProxyCommon - Reference: Default
Type - Pset_ProductRequirements - Category: Electrical Equipment
Type - Pset_QuantityTakeOff - Reference: Default
Material: Fibaro_blue 127BC1BD, Fibaro_transparent 1B44B9A5, Fibaro_glossywhite 7ECA5D70
Pset_BuildingElementProxyCommon - sets with these values: 2
Pset_ProductRequirements - Category: Generic Models

# IfcBuildingElementProxy: FIH65B_Luminance_Eltaco:FIH65B_Luminance_Eltaco:1027553:FIH65B_Luminance_Eltaco:1027553 : FIH65B_Luminance_Eltaco:FIH65B_Luminance_Eltaco:1027553:324055, FIH65B_Luminance_Eltaco:FIH65B_Luminance_Eltaco:1027553:FIH65B_Luminance_Eltaco:1027553 : FIH65B_Luminance_Eltaco:FIH65B_Luminance_Eltaco:1027553:324055:FIH65B_Luminance_Eltaco:1027553:FIH65B_Luminance_Eltaco:1027553 : FIH65B_Luminance_Eltaco:FIH65B_Luminance_Eltaco:1027553:324055 : FIH65B_Luminance_Eltaco:FIH65B_Luminance_Eltaco:1027553:FIH65B_Luminance_Eltaco:1027553 : FIH65B_Luminance_Eltaco:FIH65B_Luminance_Eltaco:1027553:324055:325011
In: Level 1
Type - Material: Plastic 166340 (3)
Type - Pset_BuildingElementProxyCommon - Reference: FIH65B_Luminance_Eltaco
Type - Pset_ManufacturerTypeInformation - Manufacturer: Plugwise
Type - Pset_ProductRequirements - Category: Specialty Equipment
Type - Pset_QuantityTakeOff - Reference: FIH65B_Luminance_Eltaco
Type - Pset_ProvisionForVoid - Depth: 1 mm
Pset_BuildingElementProxyCommon - sets with these values: 2
Pset_ProductRequirements - Category: Generic Models

# IfcBuildingElementProxy: Indoor LG 1way simple box KRIPIS v1 SYSTEMS:ARNU09GTUC4:937583:ARNU09GTUC4:937583 : Indoor LG 1way simple box KRIPIS v1 SYSTEMS:ARNU09GTUC4:937583:324319, Indoor LG 1way simple box KRIPIS v1 SYSTEMS:ARNU09GTUC4:937583:ARNU09GTUC4:937583 : Indoor LG 1way simple box KRIPIS v1 SYSTEMS:ARNU09GTUC4:937583:324319:ARNU09GTUC4:937583:ARNU09GTUC4:937583 : Indoor LG 1way simple box KRIPIS v1 SYSTEMS:ARNU09GTUC4:937583:324319 : Indoor LG 1way simple box KRIPIS v1 SYSTEMS:ARNU09GTUC4:937583:ARNU09GTUC4:937583 : Indoor LG 1way simple box KRIPIS v1 SYSTEMS:ARNU09GTUC4:937583:324319:323520
In: Level 1
Type - Material: <Unnamed>
Type - Pset_BuildingElementProxyCommon - Reference: ARNU09GTUC4
Type - Pset_ProductRequirements - Category: Mechanical Equipment
Type - Pset_QuantityTakeOff - Reference: ARNU09GTUC4
Type - Pset_ProvisionForVoid - Width: 450 mm; Height: 860 mm; Depth: 132 mm
Pset_BuildingElementProxyCommon - sets with these values: 2
Pset_ProductRequirements - Category: Generic Models
Pset_ProvisionForVoid - Width: 0.13716 mm

# IfcBuildingElementProxy: Indoor LG 4way simple box KRIPIS v3 SYSTEMS:ARNU07GTRC4:921597:ARNU07GTRC4:921597 : Indoor LG 4way simple box KRIPIS v3 SYSTEMS:ARNU07GTRC4:921597:328316, Indoor LG 4way simple box KRIPIS v3 SYSTEMS:ARNU07GTRC4:921597:ARNU07GTRC4:921597 : Indoor LG 4way simple box KRIPIS v3 SYSTEMS:ARNU07GTRC4:921597:328316:ARNU07GTRC4:921597:ARNU07GTRC4:921597 : Indoor LG 4way simple box KRIPIS v3 SYSTEMS:ARNU07GTRC4:921597:328316 : Indoor LG 4way simple box KRIPIS v3 SYSTEMS:ARNU07GTRC4:921597:ARNU07GTRC4:921597 : Indoor LG 4way simple box KRIPIS v3 SYSTEMS:ARNU07GTRC4:921597:328316:327255
In: Level 2
Type - Material: <Unnamed>
Type - Pset_BuildingElementProxyCommon - Reference: ARNU07GTRC4
Type - Pset_ProductRequirements - Category: Mechanical Equipment
Type - Pset_QuantityTakeOff - Reference: ARNU07GTRC4
Type - Pset_ProvisionForVoid - Width: 570 mm; Height: 570 mm; Depth: 214 mm
Pset_BuildingElementProxyCommon - sets with these values: 2
Pset_ProductRequirements - Category: Generic Models
Pset_ProvisionForVoid - Width: 0.173736 mm

# IfcBuildingElementProxy: Indoor LG 4way simple box KRIPIS v3 SYSTEMS:ARNU07GTRC4:922141:ARNU07GTRC4:922141 : Indoor LG 4way simple box KRIPIS v3 SYSTEMS:ARNU07GTRC4:922141:328980, Indoor LG 4way simple box KRIPIS v3 SYSTEMS:ARNU07GTRC4:922141:ARNU07GTRC4:922141 : Indoor LG 4way simple box KRIPIS v3 SYSTEMS:ARNU07GTRC4:922141:328980:ARNU07GTRC4:922141:ARNU07GTRC4:922141 : Indoor LG 4way simple box KRIPIS v3 SYSTEMS:ARNU07GTRC4:922141:328980 : Indoor LG 4way simple box KRIPIS v3 SYSTEMS:ARNU07GTRC4:922141:ARNU07GTRC4:922141 : Indoor LG 4way simple box KRIPIS v3 SYSTEMS:ARNU07GTRC4:922141:328980:327588
In: Level 2
Type - Material: <Unnamed>
Type - Pset_BuildingElementProxyCommon - Reference: ARNU07GTRC4
Type - Pset_ProductRequirements - Category: Mechanical Equipment
Type - Pset_QuantityTakeOff - Reference: ARNU07GTRC4
Type - Pset_ProvisionForVoid - Width: 570 mm; Height: 570 mm; Depth: 214 mm
Pset_BuildingElementProxyCommon - sets with these values: 2
Pset_ProductRequirements - Category: Generic Models
Pset_ProvisionForVoid - Width: 0.173736 mm

# IfcBuildingElementProxy: Indoor LG 4way simple box KRIPIS v3 SYSTEMS:ARNU07GTRC4:931225:ARNU07GTRC4:931225 : Indoor LG 4way simple box KRIPIS v3 SYSTEMS:ARNU07GTRC4:931225:323736, Indoor LG 4way simple box KRIPIS v3 SYSTEMS:ARNU07GTRC4:931225:ARNU07GTRC4:931225 : Indoor LG 4way simple box KRIPIS v3 SYSTEMS:ARNU07GTRC4:931225:323736:ARNU07GTRC4:931225:ARNU07GTRC4:931225 : Indoor LG 4way simple box KRIPIS v3 SYSTEMS:ARNU07GTRC4:931225:323736 : Indoor LG 4way simple box KRIPIS v3 SYSTEMS:ARNU07GTRC4:931225:ARNU07GTRC4:931225 : Indoor LG 4way simple box KRIPIS v3 SYSTEMS:ARNU07GTRC4:931225:323736:323334
In: Level 1
Type - Material: <Unnamed>
Type - Pset_BuildingElementProxyCommon - Reference: ARNU07GTRC4
Type - Pset_ProductRequirements - Category: Mechanical Equipment
Type - Pset_QuantityTakeOff - Reference: ARNU07GTRC4
Type - Pset_ProvisionForVoid - Width: 570 mm; Height: 570 mm; Depth: 214 mm
Pset_BuildingElementProxyCommon - sets with these values: 2
Pset_ProductRequirements - Category: Generic Models
Pset_ProvisionForVoid - Width: 0.173736 mm

# IfcBuildingElementProxy: Indoor LG 4way simple box KRIPIS v3 SYSTEMS:ARNU12GTRC4:921133:ARNU12GTRC4:921133 : Indoor LG 4way simple box KRIPIS v3 SYSTEMS:ARNU12GTRC4:921133:328557, Indoor LG 4way simple box KRIPIS v3 SYSTEMS:ARNU12GTRC4:921133:ARNU12GTRC4:921133 : Indoor LG 4way simple box KRIPIS v3 SYSTEMS:ARNU12GTRC4:921133:328557:ARNU12GTRC4:921133:ARNU12GTRC4:921133 : Indoor LG 4way simple box KRIPIS v3 SYSTEMS:ARNU12GTRC4:921133:328557 : Indoor LG 4way simple box KRIPIS v3 SYSTEMS:ARNU12GTRC4:921133:ARNU12GTRC4:921133 : Indoor LG 4way simple box KRIPIS v3 SYSTEMS:ARNU12GTRC4:921133:328557:327366
In: Level 2
Type - Material: <Unnamed>
Type - Pset_BuildingElementProxyCommon - Reference: ARNU12GTRC4
Type - Pset_ProductRequirements - Category: Mechanical Equipment
Type - Pset_QuantityTakeOff - Reference: ARNU12GTRC4
Type - Pset_ProvisionForVoid - Width: 570 mm; Height: 570 mm; Depth: 214 mm
Pset_BuildingElementProxyCommon - sets with these values: 2
Pset_ProductRequirements - Category: Generic Models
Pset_ProvisionForVoid - Width: 0.173736 mm

# IfcBuildingElementProxy: Indoor LG 4way simple box KRIPIS v3 SYSTEMS:ARNU12GTRC4:921403:ARNU12GTRC4:921403 : Indoor LG 4way simple box KRIPIS v3 SYSTEMS:ARNU12GTRC4:921403:327674, Indoor LG 4way simple box KRIPIS v3 SYSTEMS:ARNU12GTRC4:921403:ARNU12GTRC4:921403 : Indoor LG 4way simple box KRIPIS v3 SYSTEMS:ARNU12GTRC4:921403:327674:ARNU12GTRC4:921403:ARNU12GTRC4:921403 : Indoor LG 4way simple box KRIPIS v3 SYSTEMS:ARNU12GTRC4:921403:327674 : Indoor LG 4way simple box KRIPIS v3 SYSTEMS:ARNU12GTRC4:921403:ARNU12GTRC4:921403 : Indoor LG 4way simple box KRIPIS v3 SYSTEMS:ARNU12GTRC4:921403:327674:326805
In: Level 2
Type - Material: <Unnamed>
Type - Pset_BuildingElementProxyCommon - Reference: ARNU12GTRC4
Type - Pset_ProductRequirements - Category: Mechanical Equipment
Type - Pset_QuantityTakeOff - Reference: ARNU12GTRC4
Type - Pset_ProvisionForVoid - Width: 570 mm; Height: 570 mm; Depth: 214 mm
Pset_BuildingElementProxyCommon - sets with these values: 2
Pset_ProductRequirements - Category: Generic Models
Pset_ProvisionForVoid - Width: 0.173736 mm

# IfcBuildingElementProxy: Indoor LG 4way simple box KRIPIS v3 SYSTEMS:ARNU12GTRC4:921951:ARNU12GTRC4:921951 : Indoor LG 4way simple box KRIPIS v3 SYSTEMS:ARNU12GTRC4:921951:327688, Indoor LG 4way simple box KRIPIS v3 SYSTEMS:ARNU12GTRC4:921951:ARNU12GTRC4:921951 : Indoor LG 4way simple box KRIPIS v3 SYSTEMS:ARNU12GTRC4:921951:327688:ARNU12GTRC4:921951:ARNU12GTRC4:921951 : Indoor LG 4way simple box KRIPIS v3 SYSTEMS:ARNU12GTRC4:921951:327688 : Indoor LG 4way simple box KRIPIS v3 SYSTEMS:ARNU12GTRC4:921951:ARNU12GTRC4:921951 : Indoor LG 4way simple box KRIPIS v3 SYSTEMS:ARNU12GTRC4:921951:327688:326819
In: Level 2
Type - Material: <Unnamed>
Type - Pset_BuildingElementProxyCommon - Reference: ARNU12GTRC4
Type - Pset_ProductRequirements - Category: Mechanical Equipment
Type - Pset_QuantityTakeOff - Reference: ARNU12GTRC4
Type - Pset_ProvisionForVoid - Width: 570 mm; Height: 570 mm; Depth: 214 mm
Pset_BuildingElementProxyCommon - sets with these values: 2
Pset_ProductRequirements - Category: Generic Models
Pset_ProvisionForVoid - Width: 0.173736 mm

# IfcBuildingElementProxy: Indoor LG 4way simple box KRIPIS v3 SYSTEMS:ARNU12GTRC4:931535:ARNU12GTRC4:931535 : Indoor LG 4way simple box KRIPIS v3 SYSTEMS:ARNU12GTRC4:931535:322912, Indoor LG 4way simple box KRIPIS v3 SYSTEMS:ARNU12GTRC4:931535:ARNU12GTRC4:931535 : Indoor LG 4way simple box KRIPIS v3 SYSTEMS:ARNU12GTRC4:931535:322912:ARNU12GTRC4:931535:ARNU12GTRC4:931535 : Indoor LG 4way simple box KRIPIS v3 SYSTEMS:ARNU12GTRC4:931535:322912 : Indoor LG 4way simple box KRIPIS v3 SYSTEMS:ARNU12GTRC4:931535:ARNU12GTRC4:931535 : Indoor LG 4way simple box KRIPIS v3 SYSTEMS:ARNU12GTRC4:931535:322912:322636
In: Level 1
Type - Material: <Unnamed>
Type - Pset_BuildingElementProxyCommon - Reference: ARNU12GTRC4
Type - Pset_ProductRequirements - Category: Mechanical Equipment
Type - Pset_QuantityTakeOff - Reference: ARNU12GTRC4
Type - Pset_ProvisionForVoid - Width: 570 mm; Height: 570 mm; Depth: 214 mm
Pset_BuildingElementProxyCommon - sets with these values: 2
Pset_ProductRequirements - Category: Generic Models
Pset_ProvisionForVoid - Width: 0.173736 mm

# IfcBuildingElementProxy: Indoor LG 4way simple box KRIPIS v3 SYSTEMS:ARNU12GTRC4:931541:ARNU12GTRC4:931541 : Indoor LG 4way simple box KRIPIS v3 SYSTEMS:ARNU12GTRC4:931541:322926, Indoor LG 4way simple box KRIPIS v3 SYSTEMS:ARNU12GTRC4:931541:ARNU12GTRC4:931541 : Indoor LG 4way simple box KRIPIS v3 SYSTEMS:ARNU12GTRC4:931541:322926:ARNU12GTRC4:931541:ARNU12GTRC4:931541 : Indoor LG 4way simple box KRIPIS v3 SYSTEMS:ARNU12GTRC4:931541:322926 : Indoor LG 4way simple box KRIPIS v3 SYSTEMS:ARNU12GTRC4:931541:ARNU12GTRC4:931541 : Indoor LG 4way simple box KRIPIS v3 SYSTEMS:ARNU12GTRC4:931541:322926:322650
In: Level 1
Type - Material: <Unnamed>
Type - Pset_BuildingElementProxyCommon - Reference: ARNU12GTRC4
Type - Pset_ProductRequirements - Category: Mechanical Equipment
Type - Pset_QuantityTakeOff - Reference: ARNU12GTRC4
Type - Pset_ProvisionForVoid - Width: 570 mm; Height: 570 mm; Depth: 214 mm
Pset_BuildingElementProxyCommon - sets with these values: 2
Pset_ProductRequirements - Category: Generic Models
Pset_ProvisionForVoid - Width: 0.173736 mm

# IfcBuildingElementProxy: Indoor LG 4way simple box KRIPIS v3 SYSTEMS:ARNU15GTQC4:931777:ARNU15GTQC4:931777 : Indoor LG 4way simple box KRIPIS v3 SYSTEMS:ARNU15GTQC4:931777:325145, Indoor LG 4way simple box KRIPIS v3 SYSTEMS:ARNU15GTQC4:931777:ARNU15GTQC4:931777 : Indoor LG 4way simple box KRIPIS v3 SYSTEMS:ARNU15GTQC4:931777:325145:ARNU15GTQC4:931777:ARNU15GTQC4:931777 : Indoor LG 4way simple box KRIPIS v3 SYSTEMS:ARNU15GTQC4:931777:325145 : Indoor LG 4way simple box KRIPIS v3 SYSTEMS:ARNU15GTQC4:931777:ARNU15GTQC4:931777 : Indoor LG 4way simple box KRIPIS v3 SYSTEMS:ARNU15GTQC4:931777:325145:323993
In: Level 1
Type - Material: <Unnamed>
Type - Pset_BuildingElementProxyCommon - Reference: ARNU15GTQC4
Type - Pset_ProductRequirements - Category: Mechanical Equipment
Type - Pset_QuantityTakeOff - Reference: ARNU15GTQC4
Type - Pset_ProvisionForVoid - Width: 570 mm; Height: 570 mm; Depth: 256 mm
Pset_BuildingElementProxyCommon - sets with these values: 2
Pset_ProductRequirements - Category: Generic Models
Pset_ProvisionForVoid - Width: 0.173736 mm

# IfcBuildingElementProxy: Indoor LG 4way simple box KRIPIS v3 SYSTEMS:ARNU15GTQC4:931784:ARNU15GTQC4:931784 : Indoor LG 4way simple box KRIPIS v3 SYSTEMS:ARNU15GTQC4:931784:325159, Indoor LG 4way simple box KRIPIS v3 SYSTEMS:ARNU15GTQC4:931784:ARNU15GTQC4:931784 : Indoor LG 4way simple box KRIPIS v3 SYSTEMS:ARNU15GTQC4:931784:325159:ARNU15GTQC4:931784:ARNU15GTQC4:931784 : Indoor LG 4way simple box KRIPIS v3 SYSTEMS:ARNU15GTQC4:931784:325159 : Indoor LG 4way simple box KRIPIS v3 SYSTEMS:ARNU15GTQC4:931784:ARNU15GTQC4:931784 : Indoor LG 4way simple box KRIPIS v3 SYSTEMS:ARNU15GTQC4:931784:325159:324007
In: Level 1
Type - Material: <Unnamed>
Type - Pset_BuildingElementProxyCommon - Reference: ARNU15GTQC4
Type - Pset_ProductRequirements - Category: Mechanical Equipment
Type - Pset_QuantityTakeOff - Reference: ARNU15GTQC4
Type - Pset_ProvisionForVoid - Width: 570 mm; Height: 570 mm; Depth: 256 mm
Pset_BuildingElementProxyCommon - sets with these values: 2
Pset_ProductRequirements - Category: Generic Models
Pset_ProvisionForVoid - Width: 0.173736 mm

# IfcBuildingElementProxy: Indoor LG 4way simple box KRIPIS v3 SYSTEMS:ARNU18GTQC4:921126:ARNU18GTQC4:921126 : Indoor LG 4way simple box KRIPIS v3 SYSTEMS:ARNU18GTQC4:921126:328739, Indoor LG 4way simple box KRIPIS v3 SYSTEMS:ARNU18GTQC4:921126:ARNU18GTQC4:921126 : Indoor LG 4way simple box KRIPIS v3 SYSTEMS:ARNU18GTQC4:921126:328739:ARNU18GTQC4:921126:ARNU18GTQC4:921126 : Indoor LG 4way simple box KRIPIS v3 SYSTEMS:ARNU18GTQC4:921126:328739 : Indoor LG 4way simple box KRIPIS v3 SYSTEMS:ARNU18GTQC4:921126:ARNU18GTQC4:921126 : Indoor LG 4way simple box KRIPIS v3 SYSTEMS:ARNU18GTQC4:921126:328739:327456
In: Level 2
Type - Material: <Unnamed>
Type - Pset_BuildingElementProxyCommon - Reference: ARNU18GTQC4
Type - Pset_ProductRequirements - Category: Mechanical Equipment
Type - Pset_QuantityTakeOff - Reference: ARNU18GTQC4
Type - Pset_ProvisionForVoid - Width: 570 mm; Height: 570 mm; Depth: 256 mm
Pset_BuildingElementProxyCommon - sets with these values: 2
Pset_ProductRequirements - Category: Generic Models
Pset_ProvisionForVoid - Width: 0.173736 mm

# IfcBuildingElementProxy: Indoor LG 4way simple box KRIPIS v3 SYSTEMS:ARNU18GTQC4:931936:ARNU18GTQC4:931936 : Indoor LG 4way simple box KRIPIS v3 SYSTEMS:ARNU18GTQC4:931936:324153, Indoor LG 4way simple box KRIPIS v3 SYSTEMS:ARNU18GTQC4:931936:ARNU18GTQC4:931936 : Indoor LG 4way simple box KRIPIS v3 SYSTEMS:ARNU18GTQC4:931936:324153:ARNU18GTQC4:931936:ARNU18GTQC4:931936 : Indoor LG 4way simple box KRIPIS v3 SYSTEMS:ARNU18GTQC4:931936:324153 : Indoor LG 4way simple box KRIPIS v3 SYSTEMS:ARNU18GTQC4:931936:ARNU18GTQC4:931936 : Indoor LG 4way simple box KRIPIS v3 SYSTEMS:ARNU18GTQC4:931936:324153:323466
In: Level 1
Type - Material: <Unnamed>
Type - Pset_BuildingElementProxyCommon - Reference: ARNU18GTQC4
Type - Pset_ProductRequirements - Category: Mechanical Equipment
Type - Pset_QuantityTakeOff - Reference: ARNU18GTQC4
Type - Pset_ProvisionForVoid - Width: 570 mm; Height: 570 mm; Depth: 256 mm
Pset_BuildingElementProxyCommon - sets with these values: 2
Pset_ProductRequirements - Category: Generic Models
Pset_ProvisionForVoid - Width: 0.173736 mm

# IfcBuildingElementProxy: Indoor LG 4way simple box KRIPIS v3 SYSTEMS:ARNU18GTQC4:931942:ARNU18GTQC4:931942 : Indoor LG 4way simple box KRIPIS v3 SYSTEMS:ARNU18GTQC4:931942:324167, Indoor LG 4way simple box KRIPIS v3 SYSTEMS:ARNU18GTQC4:931942:ARNU18GTQC4:931942 : Indoor LG 4way simple box KRIPIS v3 SYSTEMS:ARNU18GTQC4:931942:324167:ARNU18GTQC4:931942:ARNU18GTQC4:931942 : Indoor LG 4way simple box KRIPIS v3 SYSTEMS:ARNU18GTQC4:931942:324167 : Indoor LG 4way simple box KRIPIS v3 SYSTEMS:ARNU18GTQC4:931942:ARNU18GTQC4:931942 : Indoor LG 4way simple box KRIPIS v3 SYSTEMS:ARNU18GTQC4:931942:324167:323480
In: Level 1
Type - Material: <Unnamed>
Type - Pset_BuildingElementProxyCommon - Reference: ARNU18GTQC4
Type - Pset_ProductRequirements - Category: Mechanical Equipment
Type - Pset_QuantityTakeOff - Reference: ARNU18GTQC4
Type - Pset_ProvisionForVoid - Width: 570 mm; Height: 570 mm; Depth: 256 mm
Pset_BuildingElementProxyCommon - sets with these values: 2
Pset_ProductRequirements - Category: Generic Models
Pset_ProvisionForVoid - Width: 0.173736 mm

# IfcBuildingElementProxy: M_Lighting Switches:Single Pole:1026974:Single Pole:1026974 : M_Lighting Switches:Single Pole:1026974:328798, M_Lighting Switches:Single Pole:1026974:Single Pole:1026974 : M_Lighting Switches:Single Pole:1026974:328798:Single Pole:1026974:Single Pole:1026974 : M_Lighting Switches:Single Pole:1026974:328798 : M_Lighting Switches:Single Pole:1026974:Single Pole:1026974 : M_Lighting Switches:Single Pole:1026974:328798:327483
In: Level 2
Type - Material: <Unnamed> (2)
Type - Pset_BuildingElementProxyCommon - Reference: Single Pole
Type - Pset_ProductRequirements - Category: Lighting Devices
Type - Pset_QuantityTakeOff - Reference: Single Pole
Type - Pset_ProvisionForVoid - Width: 53.975 mm; Height: 38.1 mm; Depth: 76.2 mm
Pset_BuildingElementProxyCommon - sets with these values: 2
Pset_ProductRequirements - Category: Generic Models
Pset_ProvisionForVoid - Width: 0.0164516 mm

# IfcBuildingElementProxy: M_Lighting Switches:Single Pole:1026975:Single Pole:1026975 : M_Lighting Switches:Single Pole:1026975:328819, M_Lighting Switches:Single Pole:1026975:Single Pole:1026975 : M_Lighting Switches:Single Pole:1026975:328819:Single Pole:1026975:Single Pole:1026975 : M_Lighting Switches:Single Pole:1026975:328819 : M_Lighting Switches:Single Pole:1026975:Single Pole:1026975 : M_Lighting Switches:Single Pole:1026975:328819:327504
In: Level 2
Type - Material: <Unnamed> (2)
Type - Pset_BuildingElementProxyCommon - Reference: Single Pole
Type - Pset_ProductRequirements - Category: Lighting Devices
Type - Pset_QuantityTakeOff - Reference: Single Pole
Type - Pset_ProvisionForVoid - Width: 53.975 mm; Height: 38.1 mm; Depth: 76.2 mm
Pset_BuildingElementProxyCommon - sets with these values: 2
Pset_ProductRequirements - Category: Generic Models
Pset_ProvisionForVoid - Width: 0.0164516 mm

# IfcBuildingElementProxy: M_Lighting Switches:Single Pole:1026976:Single Pole:1026976 : M_Lighting Switches:Single Pole:1026976:328840, M_Lighting Switches:Single Pole:1026976:Single Pole:1026976 : M_Lighting Switches:Single Pole:1026976:328840:Single Pole:1026976:Single Pole:1026976 : M_Lighting Switches:Single Pole:1026976:328840 : M_Lighting Switches:Single Pole:1026976:Single Pole:1026976 : M_Lighting Switches:Single Pole:1026976:328840:327525
In: Level 2
Type - Material: <Unnamed> (2)
Type - Pset_BuildingElementProxyCommon - Reference: Single Pole
Type - Pset_ProductRequirements - Category: Lighting Devices
Type - Pset_QuantityTakeOff - Reference: Single Pole
Type - Pset_ProvisionForVoid - Width: 53.975 mm; Height: 38.1 mm; Depth: 76.2 mm
Pset_BuildingElementProxyCommon - sets with these values: 2
Pset_ProductRequirements - Category: Generic Models
Pset_ProvisionForVoid - Width: 0.0164516 mm

# IfcBuildingElementProxy: M_Lighting Switches:Single Pole:1026977:Single Pole:1026977 : M_Lighting Switches:Single Pole:1026977:328931, M_Lighting Switches:Single Pole:1026977:Single Pole:1026977 : M_Lighting Switches:Single Pole:1026977:328931:Single Pole:1026977:Single Pole:1026977 : M_Lighting Switches:Single Pole:1026977:328931 : M_Lighting Switches:Single Pole:1026977:Single Pole:1026977 : M_Lighting Switches:Single Pole:1026977:328931:327567
In: Level 2
Type - Material: <Unnamed> (2)
Type - Pset_BuildingElementProxyCommon - Reference: Single Pole
Type - Pset_ProductRequirements - Category: Lighting Devices
Type - Pset_QuantityTakeOff - Reference: Single Pole
Type - Pset_ProvisionForVoid - Width: 53.975 mm; Height: 38.1 mm; Depth: 76.2 mm
Pset_BuildingElementProxyCommon - sets with these values: 2
Pset_ProductRequirements - Category: Generic Models
Pset_ProvisionForVoid - Width: 0.0164516 mm

# IfcBuildingElementProxy: M_Lighting Switches:Single Pole:1026979:Single Pole:1026979 : M_Lighting Switches:Single Pole:1026979:329052, M_Lighting Switches:Single Pole:1026979:Single Pole:1026979 : M_Lighting Switches:Single Pole:1026979:329052:Single Pole:1026979:Single Pole:1026979 : M_Lighting Switches:Single Pole:1026979:329052 : M_Lighting Switches:Single Pole:1026979:Single Pole:1026979 : M_Lighting Switches:Single Pole:1026979:329052:327636
In: Level 2
Type - Material: <Unnamed> (2)
Type - Pset_BuildingElementProxyCommon - Reference: Single Pole
Type - Pset_ProductRequirements - Category: Lighting Devices
Type - Pset_QuantityTakeOff - Reference: Single Pole
Type - Pset_ProvisionForVoid - Width: 53.975 mm; Height: 38.1 mm; Depth: 76.2 mm
Pset_BuildingElementProxyCommon - sets with these values: 2
Pset_ProductRequirements - Category: Generic Models
Pset_ProvisionForVoid - Width: 0.0164516 mm

# IfcBuildingElementProxy: M_Lighting Switches:Single Pole:1026980:Single Pole:1026980 : M_Lighting Switches:Single Pole:1026980:328431, M_Lighting Switches:Single Pole:1026980:Single Pole:1026980 : M_Lighting Switches:Single Pole:1026980:328431:Single Pole:1026980:Single Pole:1026980 : M_Lighting Switches:Single Pole:1026980:328431 : M_Lighting Switches:Single Pole:1026980:Single Pole:1026980 : M_Lighting Switches:Single Pole:1026980:328431:327282
In: Level 2
Type - Material: <Unnamed> (2)
Type - Pset_BuildingElementProxyCommon - Reference: Single Pole
Type - Pset_ProductRequirements - Category: Lighting Devices
Type - Pset_QuantityTakeOff - Reference: Single Pole
Type - Pset_ProvisionForVoid - Width: 53.975 mm; Height: 38.1 mm; Depth: 76.2 mm
Pset_BuildingElementProxyCommon - sets with these values: 2
Pset_ProductRequirements - Category: Generic Models
Pset_ProvisionForVoid - Width: 0.0164516 mm

# IfcBuildingElementProxy: M_Lighting Switches:Single Pole:1026981:Single Pole:1026981 : M_Lighting Switches:Single Pole:1026981:328452, M_Lighting Switches:Single Pole:1026981:Single Pole:1026981 : M_Lighting Switches:Single Pole:1026981:328452:Single Pole:1026981:Single Pole:1026981 : M_Lighting Switches:Single Pole:1026981:328452 : M_Lighting Switches:Single Pole:1026981:Single Pole:1026981 : M_Lighting Switches:Single Pole:1026981:328452:327303
In: Level 2
Type - Material: <Unnamed> (2)
Type - Pset_BuildingElementProxyCommon - Reference: Single Pole
Type - Pset_ProductRequirements - Category: Lighting Devices
Type - Pset_QuantityTakeOff - Reference: Single Pole
Type - Pset_ProvisionForVoid - Width: 53.975 mm; Height: 38.1 mm; Depth: 76.2 mm
Pset_BuildingElementProxyCommon - sets with these values: 2
Pset_ProductRequirements - Category: Generic Models
Pset_ProvisionForVoid - Width: 0.0164516 mm

# IfcBuildingElementProxy: M_Lighting Switches:Single Pole:1026982:Single Pole:1026982 : M_Lighting Switches:Single Pole:1026982:328473, M_Lighting Switches:Single Pole:1026982:Single Pole:1026982 : M_Lighting Switches:Single Pole:1026982:328473:Single Pole:1026982:Single Pole:1026982 : M_Lighting Switches:Single Pole:1026982:328473 : M_Lighting Switches:Single Pole:1026982:Single Pole:1026982 : M_Lighting Switches:Single Pole:1026982:328473:327324
In: Level 2
Type - Material: <Unnamed> (2)
Type - Pset_BuildingElementProxyCommon - Reference: Single Pole
Type - Pset_ProductRequirements - Category: Lighting Devices
Type - Pset_QuantityTakeOff - Reference: Single Pole
Type - Pset_ProvisionForVoid - Width: 53.975 mm; Height: 38.1 mm; Depth: 76.2 mm
Pset_BuildingElementProxyCommon - sets with these values: 2
Pset_ProductRequirements - Category: Generic Models
Pset_ProvisionForVoid - Width: 0.0164516 mm

# IfcBuildingElementProxy: M_Lighting Switches:Single Pole:1026983:Single Pole:1026983 : M_Lighting Switches:Single Pole:1026983:327864, M_Lighting Switches:Single Pole:1026983:Single Pole:1026983 : M_Lighting Switches:Single Pole:1026983:327864:Single Pole:1026983:Single Pole:1026983 : M_Lighting Switches:Single Pole:1026983:327864 : M_Lighting Switches:Single Pole:1026983:Single Pole:1026983 : M_Lighting Switches:Single Pole:1026983:327864:326859
In: Level 2
Type - Material: <Unnamed> (2)
Type - Pset_BuildingElementProxyCommon - Reference: Single Pole
Type - Pset_ProductRequirements - Category: Lighting Devices
Type - Pset_QuantityTakeOff - Reference: Single Pole
Type - Pset_ProvisionForVoid - Width: 53.975 mm; Height: 38.1 mm; Depth: 76.2 mm
Pset_BuildingElementProxyCommon - sets with these values: 2
Pset_ProductRequirements - Category: Generic Models
Pset_ProvisionForVoid - Width: 0.0164516 mm

# IfcBuildingElementProxy: M_Lighting Switches:Single Pole:1026990:Single Pole:1026990 : M_Lighting Switches:Single Pole:1026990:325481, M_Lighting Switches:Single Pole:1026990:Single Pole:1026990 : M_Lighting Switches:Single Pole:1026990:325481:Single Pole:1026990:Single Pole:1026990 : M_Lighting Switches:Single Pole:1026990:325481 : M_Lighting Switches:Single Pole:1026990:Single Pole:1026990 : M_Lighting Switches:Single Pole:1026990:325481:324257
In: Level 1
Type - Material: <Unnamed> (2)
Type - Pset_BuildingElementProxyCommon - Reference: Single Pole
Type - Pset_ProductRequirements - Category: Lighting Devices
Type - Pset_QuantityTakeOff - Reference: Single Pole
Type - Pset_ProvisionForVoid - Width: 53.975 mm; Height: 38.1 mm; Depth: 76.2 mm
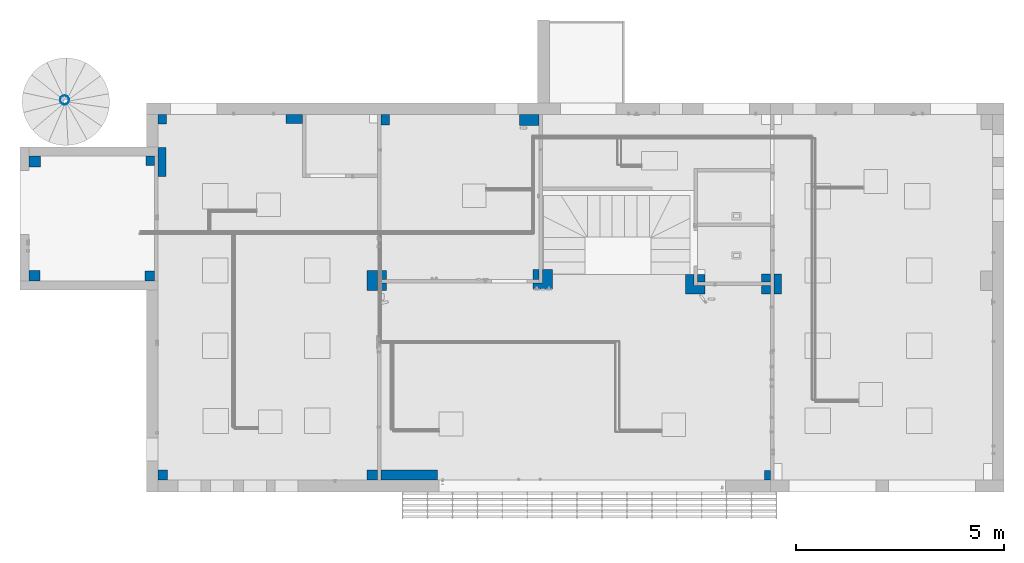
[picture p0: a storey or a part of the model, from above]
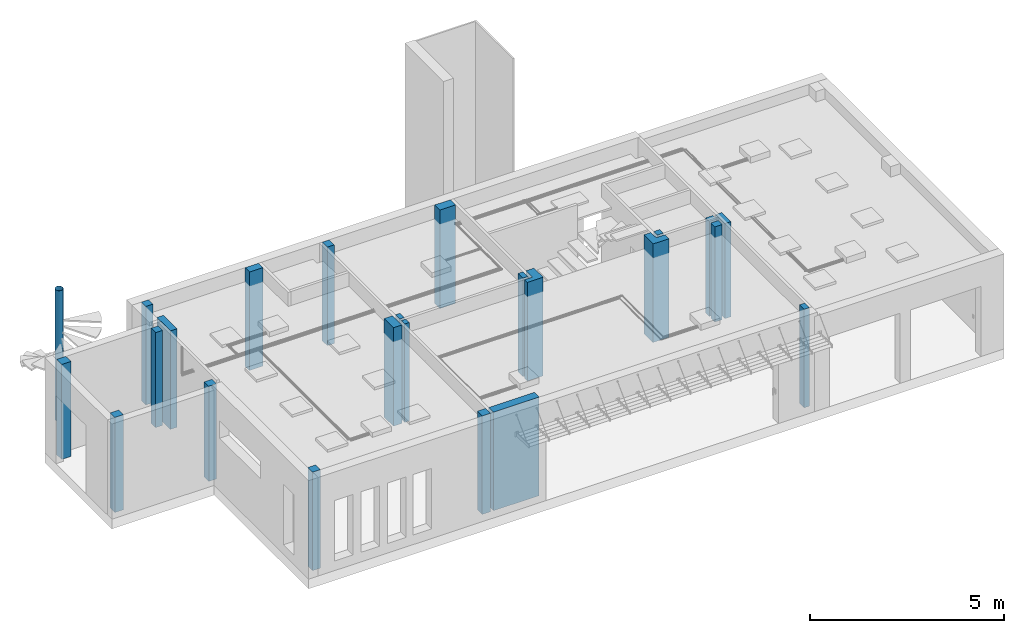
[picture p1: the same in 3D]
Properties of the parts of a building model (IFC2X3), part 2 of 5

# IfcBuildingElementProxy: M_Lighting Switches:Single Pole:1026990:Single Pole:1026990 : M_Lighting Switches:Single Pole:1026990:325481, M_Lighting Switches:Single Pole:1026990:Single Pole:1026990 : M_Lighting Switches:Single Pole:1026990:325481:Single Pole:1026990:Single Pole:1026990 : M_Lighting Switches:Single Pole:1026990:325481 : M_Lighting Switches:Single Pole:1026990:Single Pole:1026990 : M_Lighting Switches:Single Pole:1026990:325481:324257
Pset_BuildingElementProxyCommon - sets with these values: 2
Pset_ProductRequirements - Category: Generic Models
Pset_ProvisionForVoid - Width: 0.0164516 mm

# IfcBuildingElementProxy: M_Lighting Switches:Single Pole:1026993:Single Pole:1026993 : M_Lighting Switches:Single Pole:1026993:324605, M_Lighting Switches:Single Pole:1026993:Single Pole:1026993 : M_Lighting Switches:Single Pole:1026993:324605:Single Pole:1026993:Single Pole:1026993 : M_Lighting Switches:Single Pole:1026993:324605 : M_Lighting Switches:Single Pole:1026993:Single Pole:1026993 : M_Lighting Switches:Single Pole:1026993:324605:323757
In: Level 1
Type - Material: <Unnamed> (2)
Type - Pset_BuildingElementProxyCommon - Reference: Single Pole
Type - Pset_ProductRequirements - Category: Lighting Devices
Type - Pset_QuantityTakeOff - Reference: Single Pole
Type - Pset_ProvisionForVoid - Width: 53.975 mm; Height: 38.1 mm; Depth: 76.2 mm
Pset_BuildingElementProxyCommon - sets with these values: 2
Pset_ProductRequirements - Category: Generic Models
Pset_ProvisionForVoid - Width: 0.0164516 mm

# IfcBuildingElementProxy: M_Lighting Switches:Single Pole:1026995:Single Pole:1026995 : M_Lighting Switches:Single Pole:1026995:324626, M_Lighting Switches:Single Pole:1026995:Single Pole:1026995 : M_Lighting Switches:Single Pole:1026995:324626:Single Pole:1026995:Single Pole:1026995 : M_Lighting Switches:Single Pole:1026995:324626 : M_Lighting Switches:Single Pole:1026995:Single Pole:1026995 : M_Lighting Switches:Single Pole:1026995:324626:323778
In: Level 1
Type - Material: <Unnamed> (2)
Type - Pset_BuildingElementProxyCommon - Reference: Single Pole
Type - Pset_ProductRequirements - Category: Lighting Devices
Type - Pset_QuantityTakeOff - Reference: Single Pole
Type - Pset_ProvisionForVoid - Width: 53.975 mm; Height: 38.1 mm; Depth: 76.2 mm
Pset_BuildingElementProxyCommon - sets with these values: 2
Pset_ProductRequirements - Category: Generic Models
Pset_ProvisionForVoid - Width: 0.0164516 mm

# IfcBuildingElementProxy: M_Lighting Switches:Single Pole:1026996:Single Pole:1026996 : M_Lighting Switches:Single Pole:1026996:324647, M_Lighting Switches:Single Pole:1026996:Single Pole:1026996 : M_Lighting Switches:Single Pole:1026996:324647:Single Pole:1026996:Single Pole:1026996 : M_Lighting Switches:Single Pole:1026996:324647 : M_Lighting Switches:Single Pole:1026996:Single Pole:1026996 : M_Lighting Switches:Single Pole:1026996:324647:323799
In: Level 1
Type - Material: <Unnamed> (2)
Type - Pset_BuildingElementProxyCommon - Reference: Single Pole
Type - Pset_ProductRequirements - Category: Lighting Devices
Type - Pset_QuantityTakeOff - Reference: Single Pole
Type - Pset_ProvisionForVoid - Width: 53.975 mm; Height: 38.1 mm; Depth: 76.2 mm
Pset_BuildingElementProxyCommon - sets with these values: 2
Pset_ProductRequirements - Category: Generic Models
Pset_ProvisionForVoid - Width: 0.0164516 mm

# IfcBuildingElementProxy: M_Lighting Switches:Single Pole:1026997:Single Pole:1026997 : M_Lighting Switches:Single Pole:1026997:323872, M_Lighting Switches:Single Pole:1026997:Single Pole:1026997 : M_Lighting Switches:Single Pole:1026997:323872:Single Pole:1026997:Single Pole:1026997 : M_Lighting Switches:Single Pole:1026997:323872 : M_Lighting Switches:Single Pole:1026997:Single Pole:1026997 : M_Lighting Switches:Single Pole:1026997:323872:323382
In: Level 1
Type - Material: <Unnamed> (2)
Type - Pset_BuildingElementProxyCommon - Reference: Single Pole
Type - Pset_ProductRequirements - Category: Lighting Devices
Type - Pset_QuantityTakeOff - Reference: Single Pole
Type - Pset_ProvisionForVoid - Width: 53.975 mm; Height: 38.1 mm; Depth: 76.2 mm
Pset_BuildingElementProxyCommon - sets with these values: 2
Pset_ProductRequirements - Category: Generic Models
Pset_ProvisionForVoid - Width: 0.0164516 mm

# IfcBuildingElementProxy: M_Lighting Switches:Single Pole:1026998:Single Pole:1026998 : M_Lighting Switches:Single Pole:1026998:323893, M_Lighting Switches:Single Pole:1026998:Single Pole:1026998 : M_Lighting Switches:Single Pole:1026998:323893:Single Pole:1026998:Single Pole:1026998 : M_Lighting Switches:Single Pole:1026998:323893 : M_Lighting Switches:Single Pole:1026998:Single Pole:1026998 : M_Lighting Switches:Single Pole:1026998:323893:323403
In: Level 1
Type - Material: <Unnamed> (2)
Type - Pset_BuildingElementProxyCommon - Reference: Single Pole
Type - Pset_ProductRequirements - Category: Lighting Devices
Type - Pset_QuantityTakeOff - Reference: Single Pole
Type - Pset_ProvisionForVoid - Width: 53.975 mm; Height: 38.1 mm; Depth: 76.2 mm
Pset_BuildingElementProxyCommon - sets with these values: 2
Pset_ProductRequirements - Category: Generic Models
Pset_ProvisionForVoid - Width: 0.0164516 mm

# IfcBuildingElementProxy: M_Lighting Switches:Single Pole:1026999:Single Pole:1026999 : M_Lighting Switches:Single Pole:1026999:323914, M_Lighting Switches:Single Pole:1026999:Single Pole:1026999 : M_Lighting Switches:Single Pole:1026999:323914:Single Pole:1026999:Single Pole:1026999 : M_Lighting Switches:Single Pole:1026999:323914 : M_Lighting Switches:Single Pole:1026999:Single Pole:1026999 : M_Lighting Switches:Single Pole:1026999:323914:323424
In: Level 1
Type - Material: <Unnamed> (2)
Type - Pset_BuildingElementProxyCommon - Reference: Single Pole
Type - Pset_ProductRequirements - Category: Lighting Devices
Type - Pset_QuantityTakeOff - Reference: Single Pole
Type - Pset_ProvisionForVoid - Width: 53.975 mm; Height: 38.1 mm; Depth: 76.2 mm
Pset_BuildingElementProxyCommon - sets with these values: 2
Pset_ProductRequirements - Category: Generic Models
Pset_ProvisionForVoid - Width: 0.0164516 mm

# IfcBuildingElementProxy: M_Lighting Switches:Single Pole:1027000:Single Pole:1027000 : M_Lighting Switches:Single Pole:1027000:323332, M_Lighting Switches:Single Pole:1027000:Single Pole:1027000 : M_Lighting Switches:Single Pole:1027000:323332:Single Pole:1027000:Single Pole:1027000 : M_Lighting Switches:Single Pole:1027000:323332 : M_Lighting Switches:Single Pole:1027000:Single Pole:1027000 : M_Lighting Switches:Single Pole:1027000:323332:322947
In: Level 1
Type - Material: <Unnamed> (2)
Type - Pset_BuildingElementProxyCommon - Reference: Single Pole
Type - Pset_ProductRequirements - Category: Lighting Devices
Type - Pset_QuantityTakeOff - Reference: Single Pole
Type - Pset_ProvisionForVoid - Width: 53.975 mm; Height: 38.1 mm; Depth: 76.2 mm
Pset_BuildingElementProxyCommon - sets with these values: 2
Pset_ProductRequirements - Category: Generic Models
Pset_ProvisionForVoid - Width: 0.0164516 mm

# IfcBuildingElementProxy: M_Lighting Switches:Single Pole:1027002:Single Pole:1027002 : M_Lighting Switches:Single Pole:1027002:325103, M_Lighting Switches:Single Pole:1027002:Single Pole:1027002 : M_Lighting Switches:Single Pole:1027002:325103:Single Pole:1027002:Single Pole:1027002 : M_Lighting Switches:Single Pole:1027002:325103 : M_Lighting Switches:Single Pole:1027002:Single Pole:1027002 : M_Lighting Switches:Single Pole:1027002:325103:323951
In: Level 1
Type - Material: <Unnamed> (2)
Type - Pset_BuildingElementProxyCommon - Reference: Single Pole
Type - Pset_ProductRequirements - Category: Lighting Devices
Type - Pset_QuantityTakeOff - Reference: Single Pole
Type - Pset_ProvisionForVoid - Width: 53.975 mm; Height: 38.1 mm; Depth: 76.2 mm
Pset_BuildingElementProxyCommon - sets with these values: 2
Pset_ProductRequirements - Category: Generic Models
Pset_ProvisionForVoid - Width: 0.0164516 mm

# IfcBuildingElementProxy: M_Lighting Switches:Single Pole:1027003:Single Pole:1027003 : M_Lighting Switches:Single Pole:1027003:325124, M_Lighting Switches:Single Pole:1027003:Single Pole:1027003 : M_Lighting Switches:Single Pole:1027003:325124:Single Pole:1027003:Single Pole:1027003 : M_Lighting Switches:Single Pole:1027003:325124 : M_Lighting Switches:Single Pole:1027003:Single Pole:1027003 : M_Lighting Switches:Single Pole:1027003:325124:323972
In: Level 1
Type - Material: <Unnamed> (2)
Type - Pset_BuildingElementProxyCommon - Reference: Single Pole
Type - Pset_ProductRequirements - Category: Lighting Devices
Type - Pset_QuantityTakeOff - Reference: Single Pole
Type - Pset_ProvisionForVoid - Width: 53.975 mm; Height: 38.1 mm; Depth: 76.2 mm
Pset_BuildingElementProxyCommon - sets with these values: 2
Pset_ProductRequirements - Category: Generic Models
Pset_ProvisionForVoid - Width: 0.0164516 mm

# IfcBuildingElementProxy: M_Lighting Switches:Three Way:1026984:Three Way:1026984 : M_Lighting Switches:Three Way:1026984:328648, M_Lighting Switches:Three Way:1026984:Three Way:1026984 : M_Lighting Switches:Three Way:1026984:328648:Three Way:1026984:Three Way:1026984 : M_Lighting Switches:Three Way:1026984:328648 : M_Lighting Switches:Three Way:1026984:Three Way:1026984 : M_Lighting Switches:Three Way:1026984:328648:327393
In: Level 2
Type - Material: <Unnamed> (2)
Type - Pset_BuildingElementProxyCommon - Reference: Three Way
Type - Pset_ProductRequirements - Category: Lighting Devices
Type - Pset_QuantityTakeOff - Reference: Three Way
Type - Pset_ProvisionForVoid - Width: 53.975 mm; Height: 38.1 mm; Depth: 76.2 mm
Pset_BuildingElementProxyCommon - sets with these values: 2
Pset_ProductRequirements - Category: Generic Models
Pset_ProvisionForVoid - Width: 0.0164516 mm

# IfcBuildingElementProxy: M_Lighting Switches:Three Way:1026985:Three Way:1026985 : M_Lighting Switches:Three Way:1026985:328669, M_Lighting Switches:Three Way:1026985:Three Way:1026985 : M_Lighting Switches:Three Way:1026985:328669:Three Way:1026985:Three Way:1026985 : M_Lighting Switches:Three Way:1026985:328669 : M_Lighting Switches:Three Way:1026985:Three Way:1026985 : M_Lighting Switches:Three Way:1026985:328669:327414
In: Level 2
Type - Material: <Unnamed> (2)
Type - Pset_BuildingElementProxyCommon - Reference: Three Way
Type - Pset_ProductRequirements - Category: Lighting Devices
Type - Pset_QuantityTakeOff - Reference: Three Way
Type - Pset_ProvisionForVoid - Width: 53.975 mm; Height: 38.1 mm; Depth: 76.2 mm
Pset_BuildingElementProxyCommon - sets with these values: 2
Pset_ProductRequirements - Category: Generic Models
Pset_ProvisionForVoid - Width: 0.0164516 mm

# IfcBuildingElementProxy: M_Lighting Switches:Three Way:1026986:Three Way:1026986 : M_Lighting Switches:Three Way:1026986:329073, M_Lighting Switches:Three Way:1026986:Three Way:1026986 : M_Lighting Switches:Three Way:1026986:329073:Three Way:1026986:Three Way:1026986 : M_Lighting Switches:Three Way:1026986:329073 : M_Lighting Switches:Three Way:1026986:Three Way:1026986 : M_Lighting Switches:Three Way:1026986:329073:327657
In: Level 2
Type - Material: <Unnamed> (2)
Type - Pset_BuildingElementProxyCommon - Reference: Three Way
Type - Pset_ProductRequirements - Category: Lighting Devices
Type - Pset_QuantityTakeOff - Reference: Three Way
Type - Pset_ProvisionForVoid - Width: 53.975 mm; Height: 38.1 mm; Depth: 76.2 mm
Pset_BuildingElementProxyCommon - sets with these values: 2
Pset_ProductRequirements - Category: Generic Models
Pset_ProvisionForVoid - Width: 0.0164516 mm

# IfcBuildingElementProxy: M_Lighting Switches:Three Way:1026988:Three Way:1026988 : M_Lighting Switches:Three Way:1026988:325439, M_Lighting Switches:Three Way:1026988:Three Way:1026988 : M_Lighting Switches:Three Way:1026988:325439:Three Way:1026988:Three Way:1026988 : M_Lighting Switches:Three Way:1026988:325439 : M_Lighting Switches:Three Way:1026988:Three Way:1026988 : M_Lighting Switches:Three Way:1026988:325439:324215
In: Level 1
Type - Material: <Unnamed> (2)
Type - Pset_BuildingElementProxyCommon - Reference: Three Way
Type - Pset_ProductRequirements - Category: Lighting Devices
Type - Pset_QuantityTakeOff - Reference: Three Way
Type - Pset_ProvisionForVoid - Width: 53.975 mm; Height: 38.1 mm; Depth: 76.2 mm
Pset_BuildingElementProxyCommon - sets with these values: 2
Pset_ProductRequirements - Category: Generic Models
Pset_ProvisionForVoid - Width: 0.0164516 mm

# IfcBuildingElementProxy: M_Lighting Switches:Three Way:1026989:Three Way:1026989 : M_Lighting Switches:Three Way:1026989:325460, M_Lighting Switches:Three Way:1026989:Three Way:1026989 : M_Lighting Switches:Three Way:1026989:325460:Three Way:1026989:Three Way:1026989 : M_Lighting Switches:Three Way:1026989:325460 : M_Lighting Switches:Three Way:1026989:Three Way:1026989 : M_Lighting Switches:Three Way:1026989:325460:324236
In: Level 1
Type - Material: <Unnamed> (2)
Type - Pset_BuildingElementProxyCommon - Reference: Three Way
Type - Pset_ProductRequirements - Category: Lighting Devices
Type - Pset_QuantityTakeOff - Reference: Three Way
Type - Pset_ProvisionForVoid - Width: 53.975 mm; Height: 38.1 mm; Depth: 76.2 mm
Pset_BuildingElementProxyCommon - sets with these values: 2
Pset_ProductRequirements - Category: Generic Models
Pset_ProvisionForVoid - Width: 0.0164516 mm

# IfcBuildingElementProxy: M_Lighting Switches:Three Way:1026991:Three Way:1026991 : M_Lighting Switches:Three Way:1026991:324563, M_Lighting Switches:Three Way:1026991:Three Way:1026991 : M_Lighting Switches:Three Way:1026991:324563:Three Way:1026991:Three Way:1026991 : M_Lighting Switches:Three Way:1026991:324563 : M_Lighting Switches:Three Way:1026991:Three Way:1026991 : M_Lighting Switches:Three Way:1026991:324563:323715
In: Level 1
Type - Material: <Unnamed> (2)
Type - Pset_BuildingElementProxyCommon - Reference: Three Way
Type - Pset_ProductRequirements - Category: Lighting Devices
Type - Pset_QuantityTakeOff - Reference: Three Way
Type - Pset_ProvisionForVoid - Width: 53.975 mm; Height: 38.1 mm; Depth: 76.2 mm
Pset_BuildingElementProxyCommon - sets with these values: 2
Pset_ProductRequirements - Category: Generic Models
Pset_ProvisionForVoid - Width: 0.0164516 mm

# IfcBuildingElementProxy: M_Lighting Switches:Three Way:1026992:Three Way:1026992 : M_Lighting Switches:Three Way:1026992:324584, M_Lighting Switches:Three Way:1026992:Three Way:1026992 : M_Lighting Switches:Three Way:1026992:324584:Three Way:1026992:Three Way:1026992 : M_Lighting Switches:Three Way:1026992:324584 : M_Lighting Switches:Three Way:1026992:Three Way:1026992 : M_Lighting Switches:Three Way:1026992:324584:323736
In: Level 1
Type - Material: <Unnamed> (2)
Type - Pset_BuildingElementProxyCommon - Reference: Three Way
Type - Pset_ProductRequirements - Category: Lighting Devices
Type - Pset_QuantityTakeOff - Reference: Three Way
Type - Pset_ProvisionForVoid - Width: 53.975 mm; Height: 38.1 mm; Depth: 76.2 mm
Pset_BuildingElementProxyCommon - sets with these values: 2
Pset_ProductRequirements - Category: Generic Models
Pset_ProvisionForVoid - Width: 0.0164516 mm

# IfcBuildingElementProxy: M_Lighting Switches:Three Way:1027004:Three Way:1027004 : M_Lighting Switches:Three Way:1027004:323362, M_Lighting Switches:Three Way:1027004:Three Way:1027004 : M_Lighting Switches:Three Way:1027004:323362:Three Way:1027004:Three Way:1027004 : M_Lighting Switches:Three Way:1027004:323362 : M_Lighting Switches:Three Way:1027004:Three Way:1027004 : M_Lighting Switches:Three Way:1027004:323362:322968
In: Level 1
Type - Material: <Unnamed> (2)
Type - Pset_BuildingElementProxyCommon - Reference: Three Way
Type - Pset_ProductRequirements - Category: Lighting Devices
Type - Pset_QuantityTakeOff - Reference: Three Way
Type - Pset_ProvisionForVoid - Width: 53.975 mm; Height: 38.1 mm; Depth: 76.2 mm
Pset_BuildingElementProxyCommon - sets with these values: 2
Pset_ProductRequirements - Category: Generic Models
Pset_ProvisionForVoid - Width: 0.0164516 mm

# IfcBuildingElementProxy: M_Lighting Switches:Three Way:1027005:Three Way:1027005 : M_Lighting Switches:Three Way:1027005:323383, M_Lighting Switches:Three Way:1027005:Three Way:1027005 : M_Lighting Switches:Three Way:1027005:323383:Three Way:1027005:Three Way:1027005 : M_Lighting Switches:Three Way:1027005:323383 : M_Lighting Switches:Three Way:1027005:Three Way:1027005 : M_Lighting Switches:Three Way:1027005:323383:322989
In: Level 1
Type - Material: <Unnamed> (2)
Type - Pset_BuildingElementProxyCommon - Reference: Three Way
Type - Pset_ProductRequirements - Category: Lighting Devices
Type - Pset_QuantityTakeOff - Reference: Three Way
Type - Pset_ProvisionForVoid - Width: 53.975 mm; Height: 38.1 mm; Depth: 76.2 mm
Pset_BuildingElementProxyCommon - sets with these values: 2
Pset_ProductRequirements - Category: Generic Models
Pset_ProvisionForVoid - Width: 0.0164516 mm

# IfcBuildingElementProxy: M_Lighting Switches:Three Way:1027007:Three Way:1027007 : M_Lighting Switches:Three Way:1027007:327885, M_Lighting Switches:Three Way:1027007:Three Way:1027007 : M_Lighting Switches:Three Way:1027007:327885:Three Way:1027007:Three Way:1027007 : M_Lighting Switches:Three Way:1027007:327885 : M_Lighting Switches:Three Way:1027007:Three Way:1027007 : M_Lighting Switches:Three Way:1027007:327885:326880
In: Level 2
Type - Material: <Unnamed> (2)
Type - Pset_BuildingElementProxyCommon - Reference: Three Way
Type - Pset_ProductRequirements - Category: Lighting Devices
Type - Pset_QuantityTakeOff - Reference: Three Way
Type - Pset_ProvisionForVoid - Width: 53.975 mm; Height: 38.1 mm; Depth: 76.2 mm
Pset_BuildingElementProxyCommon - sets with these values: 2
Pset_ProductRequirements - Category: Generic Models
Pset_ProvisionForVoid - Width: 0.0164516 mm

# IfcBuildingElementProxy: M_Receptacle - 220V:Standard:1026922:Standard:1026922 : M_Receptacle - 220V:Standard:1026922:323851, M_Receptacle - 220V:Standard:1026922:Standard:1026922 : M_Receptacle - 220V:Standard:1026922:323851:Standard:1026922:Standard:1026922 : M_Receptacle - 220V:Standard:1026922:323851 : M_Receptacle - 220V:Standard:1026922:Standard:1026922 : M_Receptacle - 220V:Standard:1026922:323851:323361
In: Level 1
Type - Material: <Unnamed> (2)
Type - Pset_BuildingElementProxyCommon - Reference: Standard
Type - Pset_ProductRequirements - Category: Electrical Fixtures
Type - Pset_QuantityTakeOff - Reference: Standard
Type - Pset_ProvisionForVoid - Width: 53.975 mm; Height: 38.1 mm; Depth: 76.2 mm
Pset_BuildingElementProxyCommon - sets with these values: 2
Pset_ProductRequirements - Category: Generic Models
Pset_ProvisionForVoid - Width: 0.0164516 mm

# IfcBuildingElementProxy: M_Receptacle - 220V:Standard:1026924:Standard:1026924 : M_Receptacle - 220V:Standard:1026924:323078, M_Receptacle - 220V:Standard:1026924:Standard:1026924 : M_Receptacle - 220V:Standard:1026924:323078:Standard:1026924:Standard:1026924 : M_Receptacle - 220V:Standard:1026924:323078 : M_Receptacle - 220V:Standard:1026924:Standard:1026924 : M_Receptacle - 220V:Standard:1026924:323078:322695
In: Level 1
Type - Material: <Unnamed> (2)
Type - Pset_BuildingElementProxyCommon - Reference: Standard
Type - Pset_ProductRequirements - Category: Electrical Fixtures
Type - Pset_QuantityTakeOff - Reference: Standard
Type - Pset_ProvisionForVoid - Width: 53.975 mm; Height: 38.1 mm; Depth: 76.2 mm
Pset_BuildingElementProxyCommon - sets with these values: 2
Pset_ProductRequirements - Category: Generic Models
Pset_ProvisionForVoid - Width: 0.0164516 mm

# IfcBuildingElementProxy: M_Receptacle - 220V:Standard:1026926:Standard:1026926 : M_Receptacle - 220V:Standard:1026926:323101, M_Receptacle - 220V:Standard:1026926:Standard:1026926 : M_Receptacle - 220V:Standard:1026926:323101:Standard:1026926:Standard:1026926 : M_Receptacle - 220V:Standard:1026926:323101 : M_Receptacle - 220V:Standard:1026926:Standard:1026926 : M_Receptacle - 220V:Standard:1026926:323101:322716
In: Level 1
Type - Material: <Unnamed> (2)
Type - Pset_BuildingElementProxyCommon - Reference: Standard
Type - Pset_ProductRequirements - Category: Electrical Fixtures
Type - Pset_QuantityTakeOff - Reference: Standard
Type - Pset_ProvisionForVoid - Width: 53.975 mm; Height: 38.1 mm; Depth: 76.2 mm
Pset_BuildingElementProxyCommon - sets with these values: 2
Pset_ProductRequirements - Category: Generic Models
Pset_ProvisionForVoid - Width: 0.0164516 mm

# IfcBuildingElementProxy: M_Receptacle - 220V:Standard:1026927:Standard:1026927 : M_Receptacle - 220V:Standard:1026927:323122, M_Receptacle - 220V:Standard:1026927:Standard:1026927 : M_Receptacle - 220V:Standard:1026927:323122:Standard:1026927:Standard:1026927 : M_Receptacle - 220V:Standard:1026927:323122 : M_Receptacle - 220V:Standard:1026927:Standard:1026927 : M_Receptacle - 220V:Standard:1026927:323122:322737
In: Level 1
Type - Material: <Unnamed> (2)
Type - Pset_BuildingElementProxyCommon - Reference: Standard
Type - Pset_ProductRequirements - Category: Electrical Fixtures
Type - Pset_QuantityTakeOff - Reference: Standard
Type - Pset_ProvisionForVoid - Width: 53.975 mm; Height: 38.1 mm; Depth: 76.2 mm
Pset_BuildingElementProxyCommon - sets with these values: 2
Pset_ProductRequirements - Category: Generic Models
Pset_ProvisionForVoid - Width: 0.0164516 mm

# IfcBuildingElementProxy: M_Receptacle - 220V:Standard:1026929:Standard:1026929 : M_Receptacle - 220V:Standard:1026929:323143, M_Receptacle - 220V:Standard:1026929:Standard:1026929 : M_Receptacle - 220V:Standard:1026929:323143:Standard:1026929:Standard:1026929 : M_Receptacle - 220V:Standard:1026929:323143 : M_Receptacle - 220V:Standard:1026929:Standard:1026929 : M_Receptacle - 220V:Standard:1026929:323143:322758
In: Level 1
Type - Material: <Unnamed> (2)
Type - Pset_BuildingElementProxyCommon - Reference: Standard
Type - Pset_ProductRequirements - Category: Electrical Fixtures
Type - Pset_QuantityTakeOff - Reference: Standard
Type - Pset_ProvisionForVoid - Width: 53.975 mm; Height: 38.1 mm; Depth: 76.2 mm
Pset_BuildingElementProxyCommon - sets with these values: 2
Pset_ProductRequirements - Category: Generic Models
Pset_ProvisionForVoid - Width: 0.0164516 mm

# IfcBuildingElementProxy: M_Receptacle - 220V:Standard:1026930:Standard:1026930 : M_Receptacle - 220V:Standard:1026930:323164, M_Receptacle - 220V:Standard:1026930:Standard:1026930 : M_Receptacle - 220V:Standard:1026930:323164:Standard:1026930:Standard:1026930 : M_Receptacle - 220V:Standard:1026930:323164 : M_Receptacle - 220V:Standard:1026930:Standard:1026930 : M_Receptacle - 220V:Standard:1026930:323164:322779
In: Level 1
Type - Material: <Unnamed> (2)
Type - Pset_BuildingElementProxyCommon - Reference: Standard
Type - Pset_ProductRequirements - Category: Electrical Fixtures
Type - Pset_QuantityTakeOff - Reference: Standard
Type - Pset_ProvisionForVoid - Width: 53.975 mm; Height: 38.1 mm; Depth: 76.2 mm
Pset_BuildingElementProxyCommon - sets with these values: 2
Pset_ProductRequirements - Category: Generic Models
Pset_ProvisionForVoid - Width: 0.0164516 mm

# IfcBuildingElementProxy: M_Receptacle - 220V:Standard:1026931:Standard:1026931 : M_Receptacle - 220V:Standard:1026931:323185, M_Receptacle - 220V:Standard:1026931:Standard:1026931 : M_Receptacle - 220V:Standard:1026931:323185:Standard:1026931:Standard:1026931 : M_Receptacle - 220V:Standard:1026931:323185 : M_Receptacle - 220V:Standard:1026931:Standard:1026931 : M_Receptacle - 220V:Standard:1026931:323185:322800
In: Level 1
Type - Material: <Unnamed> (2)
Type - Pset_BuildingElementProxyCommon - Reference: Standard
Type - Pset_ProductRequirements - Category: Electrical Fixtures
Type - Pset_QuantityTakeOff - Reference: Standard
Type - Pset_ProvisionForVoid - Width: 53.975 mm; Height: 38.1 mm; Depth: 76.2 mm
Pset_BuildingElementProxyCommon - sets with these values: 2
Pset_ProductRequirements - Category: Generic Models
Pset_ProvisionForVoid - Width: 0.0164516 mm

# IfcBuildingElementProxy: M_Receptacle - 220V:Standard:1026933:Standard:1026933 : M_Receptacle - 220V:Standard:1026933:323206, M_Receptacle - 220V:Standard:1026933:Standard:1026933 : M_Receptacle - 220V:Standard:1026933:323206:Standard:1026933:Standard:1026933 : M_Receptacle - 220V:Standard:1026933:323206 : M_Receptacle - 220V:Standard:1026933:Standard:1026933 : M_Receptacle - 220V:Standard:1026933:323206:322821
In: Level 1
Type - Material: <Unnamed> (2)
Type - Pset_BuildingElementProxyCommon - Reference: Standard
Type - Pset_ProductRequirements - Category: Electrical Fixtures
Type - Pset_QuantityTakeOff - Reference: Standard
Type - Pset_ProvisionForVoid - Width: 53.975 mm; Height: 38.1 mm; Depth: 76.2 mm
Pset_BuildingElementProxyCommon - sets with these values: 2
Pset_ProductRequirements - Category: Generic Models
Pset_ProvisionForVoid - Width: 0.0164516 mm

# IfcBuildingElementProxy: M_Receptacle - 220V:Standard:1026935:Standard:1026935 : M_Receptacle - 220V:Standard:1026935:323227, M_Receptacle - 220V:Standard:1026935:Standard:1026935 : M_Receptacle - 220V:Standard:1026935:323227:Standard:1026935:Standard:1026935 : M_Receptacle - 220V:Standard:1026935:323227 : M_Receptacle - 220V:Standard:1026935:Standard:1026935 : M_Receptacle - 220V:Standard:1026935:323227:322842
In: Level 1
Type - Material: <Unnamed> (2)
Type - Pset_BuildingElementProxyCommon - Reference: Standard
Type - Pset_ProductRequirements - Category: Electrical Fixtures
Type - Pset_QuantityTakeOff - Reference: Standard
Type - Pset_ProvisionForVoid - Width: 53.975 mm; Height: 38.1 mm; Depth: 76.2 mm
Pset_BuildingElementProxyCommon - sets with these values: 2
Pset_ProductRequirements - Category: Generic Models
Pset_ProvisionForVoid - Width: 0.0164516 mm

# IfcBuildingElementProxy: M_Receptacle - 220V:Standard:1026936:Standard:1026936 : M_Receptacle - 220V:Standard:1026936:323248, M_Receptacle - 220V:Standard:1026936:Standard:1026936 : M_Receptacle - 220V:Standard:1026936:323248:Standard:1026936:Standard:1026936 : M_Receptacle - 220V:Standard:1026936:323248 : M_Receptacle - 220V:Standard:1026936:Standard:1026936 : M_Receptacle - 220V:Standard:1026936:323248:322863
In: Level 1
Type - Material: <Unnamed> (2)
Type - Pset_BuildingElementProxyCommon - Reference: Standard
Type - Pset_ProductRequirements - Category: Electrical Fixtures
Type - Pset_QuantityTakeOff - Reference: Standard
Type - Pset_ProvisionForVoid - Width: 53.975 mm; Height: 38.1 mm; Depth: 76.2 mm
Pset_BuildingElementProxyCommon - sets with these values: 2
Pset_ProductRequirements - Category: Generic Models
Pset_ProvisionForVoid - Width: 0.0164516 mm

# IfcBuildingElementProxy: M_Receptacle - 220V:Standard:1026937:Standard:1026937 : M_Receptacle - 220V:Standard:1026937:323269, M_Receptacle - 220V:Standard:1026937:Standard:1026937 : M_Receptacle - 220V:Standard:1026937:323269:Standard:1026937:Standard:1026937 : M_Receptacle - 220V:Standard:1026937:323269 : M_Receptacle - 220V:Standard:1026937:Standard:1026937 : M_Receptacle - 220V:Standard:1026937:323269:322884
In: Level 1
Type - Material: <Unnamed> (2)
Type - Pset_BuildingElementProxyCommon - Reference: Standard
Type - Pset_ProductRequirements - Category: Electrical Fixtures
Type - Pset_QuantityTakeOff - Reference: Standard
Type - Pset_ProvisionForVoid - Width: 53.975 mm; Height: 38.1 mm; Depth: 76.2 mm
Pset_BuildingElementProxyCommon - sets with these values: 2
Pset_ProductRequirements - Category: Generic Models
Pset_ProvisionForVoid - Width: 0.0164516 mm

# IfcBuildingElementProxy: M_Receptacle - 220V:Standard:1026938:Standard:1026938 : M_Receptacle - 220V:Standard:1026938:323290, M_Receptacle - 220V:Standard:1026938:Standard:1026938 : M_Receptacle - 220V:Standard:1026938:323290:Standard:1026938:Standard:1026938 : M_Receptacle - 220V:Standard:1026938:323290 : M_Receptacle - 220V:Standard:1026938:Standard:1026938 : M_Receptacle - 220V:Standard:1026938:323290:322905
In: Level 1
Type - Material: <Unnamed> (2)
Type - Pset_BuildingElementProxyCommon - Reference: Standard
Type - Pset_ProductRequirements - Category: Electrical Fixtures
Type - Pset_QuantityTakeOff - Reference: Standard
Type - Pset_ProvisionForVoid - Width: 53.975 mm; Height: 38.1 mm; Depth: 76.2 mm
Pset_BuildingElementProxyCommon - sets with these values: 2
Pset_ProductRequirements - Category: Generic Models
Pset_ProvisionForVoid - Width: 0.0164516 mm

# IfcBuildingElementProxy: M_Receptacle - 220V:Standard:1026939:Standard:1026939 : M_Receptacle - 220V:Standard:1026939:323311, M_Receptacle - 220V:Standard:1026939:Standard:1026939 : M_Receptacle - 220V:Standard:1026939:323311:Standard:1026939:Standard:1026939 : M_Receptacle - 220V:Standard:1026939:323311 : M_Receptacle - 220V:Standard:1026939:Standard:1026939 : M_Receptacle - 220V:Standard:1026939:323311:322926
In: Level 1
Type - Material: <Unnamed> (2)
Type - Pset_BuildingElementProxyCommon - Reference: Standard
Type - Pset_ProductRequirements - Category: Electrical Fixtures
Type - Pset_QuantityTakeOff - Reference: Standard
Type - Pset_ProvisionForVoid - Width: 53.975 mm; Height: 38.1 mm; Depth: 76.2 mm
Pset_BuildingElementProxyCommon - sets with these values: 2
Pset_ProductRequirements - Category: Generic Models
Pset_ProvisionForVoid - Width: 0.0164516 mm

# IfcBuildingElementProxy: M_Receptacle - 220V:Standard:1026951:Standard:1026951 : M_Receptacle - 220V:Standard:1026951:324521, M_Receptacle - 220V:Standard:1026951:Standard:1026951 : M_Receptacle - 220V:Standard:1026951:324521:Standard:1026951:Standard:1026951 : M_Receptacle - 220V:Standard:1026951:324521 : M_Receptacle - 220V:Standard:1026951:Standard:1026951 : M_Receptacle - 220V:Standard:1026951:324521:323673
In: Level 1
Type - Material: <Unnamed> (2)
Type - Pset_BuildingElementProxyCommon - Reference: Standard
Type - Pset_ProductRequirements - Category: Electrical Fixtures
Type - Pset_QuantityTakeOff - Reference: Standard
Type - Pset_ProvisionForVoid - Width: 53.975 mm; Height: 38.1 mm; Depth: 76.2 mm
Pset_BuildingElementProxyCommon - sets with these values: 2
Pset_ProductRequirements - Category: Generic Models
Pset_ProvisionForVoid - Width: 0.0164516 mm

# IfcBuildingElementProxy: M_Receptacle - 220V:Standard:1026953:Standard:1026953 : M_Receptacle - 220V:Standard:1026953:324542, M_Receptacle - 220V:Standard:1026953:Standard:1026953 : M_Receptacle - 220V:Standard:1026953:324542:Standard:1026953:Standard:1026953 : M_Receptacle - 220V:Standard:1026953:324542 : M_Receptacle - 220V:Standard:1026953:Standard:1026953 : M_Receptacle - 220V:Standard:1026953:324542:323694
In: Level 1
Type - Material: <Unnamed> (2)
Type - Pset_BuildingElementProxyCommon - Reference: Standard
Type - Pset_ProductRequirements - Category: Electrical Fixtures
Type - Pset_QuantityTakeOff - Reference: Standard
Type - Pset_ProvisionForVoid - Width: 53.975 mm; Height: 38.1 mm; Depth: 76.2 mm
Pset_BuildingElementProxyCommon - sets with these values: 2
Pset_ProductRequirements - Category: Generic Models
Pset_ProvisionForVoid - Width: 0.0164516 mm

# IfcBuildingElementProxy: M_Receptacle - 220V:Standard:1026954:Standard:1026954 : M_Receptacle - 220V:Standard:1026954:325271, M_Receptacle - 220V:Standard:1026954:Standard:1026954 : M_Receptacle - 220V:Standard:1026954:325271:Standard:1026954:Standard:1026954 : M_Receptacle - 220V:Standard:1026954:325271 : M_Receptacle - 220V:Standard:1026954:Standard:1026954 : M_Receptacle - 220V:Standard:1026954:325271:324047
In: Level 1
Type - Material: <Unnamed> (2)
Type - Pset_BuildingElementProxyCommon - Reference: Standard
Type - Pset_ProductRequirements - Category: Electrical Fixtures
Type - Pset_QuantityTakeOff - Reference: Standard
Type - Pset_ProvisionForVoid - Width: 53.975 mm; Height: 38.1 mm; Depth: 76.2 mm
Pset_BuildingElementProxyCommon - sets with these values: 2
Pset_ProductRequirements - Category: Generic Models
Pset_ProvisionForVoid - Width: 0.0164516 mm

# IfcBuildingElementProxy: M_Receptacle - 220V:Standard:1026956:Standard:1026956 : M_Receptacle - 220V:Standard:1026956:325292, M_Receptacle - 220V:Standard:1026956:Standard:1026956 : M_Receptacle - 220V:Standard:1026956:325292:Standard:1026956:Standard:1026956 : M_Receptacle - 220V:Standard:1026956:325292 : M_Receptacle - 220V:Standard:1026956:Standard:1026956 : M_Receptacle - 220V:Standard:1026956:325292:324068
In: Level 1
Type - Material: <Unnamed> (2)
Type - Pset_BuildingElementProxyCommon - Reference: Standard
Type - Pset_ProductRequirements - Category: Electrical Fixtures
Type - Pset_QuantityTakeOff - Reference: Standard
Type - Pset_ProvisionForVoid - Width: 53.975 mm; Height: 38.1 mm; Depth: 76.2 mm
Pset_BuildingElementProxyCommon - sets with these values: 2
Pset_ProductRequirements - Category: Generic Models
Pset_ProvisionForVoid - Width: 0.0164516 mm

# IfcBuildingElementProxy: M_Receptacle - 220V:Standard:1026957:Standard:1026957 : M_Receptacle - 220V:Standard:1026957:325313, M_Receptacle - 220V:Standard:1026957:Standard:1026957 : M_Receptacle - 220V:Standard:1026957:325313:Standard:1026957:Standard:1026957 : M_Receptacle - 220V:Standard:1026957:325313 : M_Receptacle - 220V:Standard:1026957:Standard:1026957 : M_Receptacle - 220V:Standard:1026957:325313:324089
In: Level 1
Type - Material: <Unnamed> (2)
Type - Pset_BuildingElementProxyCommon - Reference: Standard
Type - Pset_ProductRequirements - Category: Electrical Fixtures
Type - Pset_QuantityTakeOff - Reference: Standard
Type - Pset_ProvisionForVoid - Width: 53.975 mm; Height: 38.1 mm; Depth: 76.2 mm
Pset_BuildingElementProxyCommon - sets with these values: 2
Pset_ProductRequirements - Category: Generic Models
Pset_ProvisionForVoid - Width: 0.0164516 mm

# IfcBuildingElementProxy: M_Receptacle - 220V:Standard:1026958:Standard:1026958 : M_Receptacle - 220V:Standard:1026958:325334, M_Receptacle - 220V:Standard:1026958:Standard:1026958 : M_Receptacle - 220V:Standard:1026958:325334:Standard:1026958:Standard:1026958 : M_Receptacle - 220V:Standard:1026958:325334 : M_Receptacle - 220V:Standard:1026958:Standard:1026958 : M_Receptacle - 220V:Standard:1026958:325334:324110
In: Level 1
Type - Material: <Unnamed> (2)
Type - Pset_BuildingElementProxyCommon - Reference: Standard
Type - Pset_ProductRequirements - Category: Electrical Fixtures
Type - Pset_QuantityTakeOff - Reference: Standard
Type - Pset_ProvisionForVoid - Width: 53.975 mm; Height: 38.1 mm; Depth: 76.2 mm
Pset_BuildingElementProxyCommon - sets with these values: 2
Pset_ProductRequirements - Category: Generic Models
Pset_ProvisionForVoid - Width: 0.0164516 mm

# IfcBuildingElementProxy: M_Receptacle - 220V:Standard:1026960:Standard:1026960 : M_Receptacle - 220V:Standard:1026960:325355, M_Receptacle - 220V:Standard:1026960:Standard:1026960 : M_Receptacle - 220V:Standard:1026960:325355:Standard:1026960:Standard:1026960 : M_Receptacle - 220V:Standard:1026960:325355 : M_Receptacle - 220V:Standard:1026960:Standard:1026960 : M_Receptacle - 220V:Standard:1026960:325355:324131
In: Level 1
Type - Material: <Unnamed> (2)
Type - Pset_BuildingElementProxyCommon - Reference: Standard
Type - Pset_ProductRequirements - Category: Electrical Fixtures
Type - Pset_QuantityTakeOff - Reference: Standard
Type - Pset_ProvisionForVoid - Width: 53.975 mm; Height: 38.1 mm; Depth: 76.2 mm
Pset_BuildingElementProxyCommon - sets with these values: 2
Pset_ProductRequirements - Category: Generic Models
Pset_ProvisionForVoid - Width: 0.0164516 mm

# IfcBuildingElementProxy: M_Receptacle - 220V:Standard:1026961:Standard:1026961 : M_Receptacle - 220V:Standard:1026961:325376, M_Receptacle - 220V:Standard:1026961:Standard:1026961 : M_Receptacle - 220V:Standard:1026961:325376:Standard:1026961:Standard:1026961 : M_Receptacle - 220V:Standard:1026961:325376 : M_Receptacle - 220V:Standard:1026961:Standard:1026961 : M_Receptacle - 220V:Standard:1026961:325376:324152
In: Level 1
Type - Material: <Unnamed> (2)
Type - Pset_BuildingElementProxyCommon - Reference: Standard
Type - Pset_ProductRequirements - Category: Electrical Fixtures
Type - Pset_QuantityTakeOff - Reference: Standard
Type - Pset_ProvisionForVoid - Width: 53.975 mm; Height: 38.1 mm; Depth: 76.2 mm
Pset_BuildingElementProxyCommon - sets with these values: 2
Pset_ProductRequirements - Category: Generic Models
Pset_ProvisionForVoid - Width: 0.0164516 mm

# IfcBuildingElementProxy: M_Receptacle - 220V:Standard:1026962:Standard:1026962 : M_Receptacle - 220V:Standard:1026962:325397, M_Receptacle - 220V:Standard:1026962:Standard:1026962 : M_Receptacle - 220V:Standard:1026962:325397:Standard:1026962:Standard:1026962 : M_Receptacle - 220V:Standard:1026962:325397 : M_Receptacle - 220V:Standard:1026962:Standard:1026962 : M_Receptacle - 220V:Standard:1026962:325397:324173
In: Level 1
Type - Material: <Unnamed> (2)
Type - Pset_BuildingElementProxyCommon - Reference: Standard
Type - Pset_ProductRequirements - Category: Electrical Fixtures
Type - Pset_QuantityTakeOff - Reference: Standard
Type - Pset_ProvisionForVoid - Width: 53.975 mm; Height: 38.1 mm; Depth: 76.2 mm
Pset_BuildingElementProxyCommon - sets with these values: 2
Pset_ProductRequirements - Category: Generic Models
Pset_ProvisionForVoid - Width: 0.0164516 mm

# IfcBuildingElementProxy: M_Receptacle - 220V:Standard:1026964:Standard:1026964 : M_Receptacle - 220V:Standard:1026964:325418, M_Receptacle - 220V:Standard:1026964:Standard:1026964 : M_Receptacle - 220V:Standard:1026964:325418:Standard:1026964:Standard:1026964 : M_Receptacle - 220V:Standard:1026964:325418 : M_Receptacle - 220V:Standard:1026964:Standard:1026964 : M_Receptacle - 220V:Standard:1026964:325418:324194
In: Level 1
Type - Material: <Unnamed> (2)
Type - Pset_BuildingElementProxyCommon - Reference: Standard
Type - Pset_ProductRequirements - Category: Electrical Fixtures
Type - Pset_QuantityTakeOff - Reference: Standard
Type - Pset_ProvisionForVoid - Width: 53.975 mm; Height: 38.1 mm; Depth: 76.2 mm
Pset_BuildingElementProxyCommon - sets with these values: 2
Pset_ProductRequirements - Category: Generic Models
Pset_ProvisionForVoid - Width: 0.0164516 mm

# IfcBuildingElementProxy: M_Receptacle - 220V:Standard:1026971:Standard:1026971 : M_Receptacle - 220V:Standard:1026971:329031, M_Receptacle - 220V:Standard:1026971:Standard:1026971 : M_Receptacle - 220V:Standard:1026971:329031:Standard:1026971:Standard:1026971 : M_Receptacle - 220V:Standard:1026971:329031 : M_Receptacle - 220V:Standard:1026971:Standard:1026971 : M_Receptacle - 220V:Standard:1026971:329031:327615
In: Level 2
Type - Material: <Unnamed> (2)
Type - Pset_BuildingElementProxyCommon - Reference: Standard
Type - Pset_ProductRequirements - Category: Electrical Fixtures
Type - Pset_QuantityTakeOff - Reference: Standard
Type - Pset_ProvisionForVoid - Width: 53.975 mm; Height: 38.1 mm; Depth: 76.2 mm
Pset_BuildingElementProxyCommon - sets with these values: 2
Pset_ProductRequirements - Category: Generic Models
Pset_ProvisionForVoid - Width: 0.0164516 mm

# IfcBuildingElementProxy: M_Receptacle - 220V:Standard:1027317:Standard:1027317 : M_Receptacle - 220V:Standard:1027317:325502, M_Receptacle - 220V:Standard:1027317:Standard:1027317 : M_Receptacle - 220V:Standard:1027317:325502:Standard:1027317:Standard:1027317 : M_Receptacle - 220V:Standard:1027317:325502 : M_Receptacle - 220V:Standard:1027317:Standard:1027317 : M_Receptacle - 220V:Standard:1027317:325502:324278
In: Level 1
Type - Material: <Unnamed> (2)
Type - Pset_BuildingElementProxyCommon - Reference: Standard
Type - Pset_ProductRequirements - Category: Electrical Fixtures
Type - Pset_QuantityTakeOff - Reference: Standard
Type - Pset_ProvisionForVoid - Width: 53.975 mm; Height: 38.1 mm; Depth: 76.2 mm
Pset_BuildingElementProxyCommon - sets with these values: 2
Pset_ProductRequirements - Category: Generic Models
Pset_ProvisionForVoid - Width: 0.0164516 mm

# IfcBuildingElementProxy: M_Weather Proof Receptacle:220 V:1026941:220 V:1026941 : M_Weather Proof Receptacle:220 V:1026941:324395, M_Weather Proof Receptacle:220 V:1026941:220 V:1026941 : M_Weather Proof Receptacle:220 V:1026941:324395:220 V:1026941:220 V:1026941 : M_Weather Proof Receptacle:220 V:1026941:324395 : M_Weather Proof Receptacle:220 V:1026941:220 V:1026941 : M_Weather Proof Receptacle:220 V:1026941:324395:323547
In: Level 1
Type - Material: <Unnamed> (2)
Type - Pset_BuildingElementProxyCommon - Reference: 220 V
Type - Pset_ProductRequirements - Category: Electrical Fixtures
Type - Pset_QuantityTakeOff - Reference: 220 V
Type - Pset_ProvisionForVoid - Width: 53.975 mm; Height: 38.1 mm; Depth: 76.2 mm
Pset_BuildingElementProxyCommon - sets with these values: 2
Pset_ProductRequirements - Category: Generic Models
Pset_ProvisionForVoid - Width: 0.0164516 mm

# IfcBuildingElementProxy: M_Weather Proof Receptacle:220 V:1026943:220 V:1026943 : M_Weather Proof Receptacle:220 V:1026943:324416, M_Weather Proof Receptacle:220 V:1026943:220 V:1026943 : M_Weather Proof Receptacle:220 V:1026943:324416:220 V:1026943:220 V:1026943 : M_Weather Proof Receptacle:220 V:1026943:324416 : M_Weather Proof Receptacle:220 V:1026943:220 V:1026943 : M_Weather Proof Receptacle:220 V:1026943:324416:323568
In: Level 1
Type - Material: <Unnamed> (2)
Type - Pset_BuildingElementProxyCommon - Reference: 220 V
Type - Pset_ProductRequirements - Category: Electrical Fixtures
Type - Pset_QuantityTakeOff - Reference: 220 V
Type - Pset_ProvisionForVoid - Width: 53.975 mm; Height: 38.1 mm; Depth: 76.2 mm
Pset_BuildingElementProxyCommon - sets with these values: 2
Pset_ProductRequirements - Category: Generic Models
Pset_ProvisionForVoid - Width: 0.0164516 mm

# IfcBuildingElementProxy: M_Weather Proof Receptacle:220 V:1026944:220 V:1026944 : M_Weather Proof Receptacle:220 V:1026944:324437, M_Weather Proof Receptacle:220 V:1026944:220 V:1026944 : M_Weather Proof Receptacle:220 V:1026944:324437:220 V:1026944:220 V:1026944 : M_Weather Proof Receptacle:220 V:1026944:324437 : M_Weather Proof Receptacle:220 V:1026944:220 V:1026944 : M_Weather Proof Receptacle:220 V:1026944:324437:323589
In: Level 1
Type - Material: <Unnamed> (2)
Type - Pset_BuildingElementProxyCommon - Reference: 220 V
Type - Pset_ProductRequirements - Category: Electrical Fixtures
Type - Pset_QuantityTakeOff - Reference: 220 V
Type - Pset_ProvisionForVoid - Width: 53.975 mm; Height: 38.1 mm; Depth: 76.2 mm
Pset_BuildingElementProxyCommon - sets with these values: 2
Pset_ProductRequirements - Category: Generic Models
Pset_ProvisionForVoid - Width: 0.0164516 mm

# IfcBuildingElementProxy: M_Weather Proof Receptacle:220 V:1026945:220 V:1026945 : M_Weather Proof Receptacle:220 V:1026945:324458, M_Weather Proof Receptacle:220 V:1026945:220 V:1026945 : M_Weather Proof Receptacle:220 V:1026945:324458:220 V:1026945:220 V:1026945 : M_Weather Proof Receptacle:220 V:1026945:324458 : M_Weather Proof Receptacle:220 V:1026945:220 V:1026945 : M_Weather Proof Receptacle:220 V:1026945:324458:323610
In: Level 1
Type - Material: <Unnamed> (2)
Type - Pset_BuildingElementProxyCommon - Reference: 220 V
Type - Pset_ProductRequirements - Category: Electrical Fixtures
Type - Pset_QuantityTakeOff - Reference: 220 V
Type - Pset_ProvisionForVoid - Width: 53.975 mm; Height: 38.1 mm; Depth: 76.2 mm
Pset_BuildingElementProxyCommon - sets with these values: 2
Pset_ProductRequirements - Category: Generic Models
Pset_ProvisionForVoid - Width: 0.0164516 mm

# IfcBuildingElementProxy: M_Weather Proof Receptacle:220 V:1026946:220 V:1026946 : M_Weather Proof Receptacle:220 V:1026946:324479, M_Weather Proof Receptacle:220 V:1026946:220 V:1026946 : M_Weather Proof Receptacle:220 V:1026946:324479:220 V:1026946:220 V:1026946 : M_Weather Proof Receptacle:220 V:1026946:324479 : M_Weather Proof Receptacle:220 V:1026946:220 V:1026946 : M_Weather Proof Receptacle:220 V:1026946:324479:323631
In: Level 1
Type - Material: <Unnamed> (2)
Type - Pset_BuildingElementProxyCommon - Reference: 220 V
Type - Pset_ProductRequirements - Category: Electrical Fixtures
Type - Pset_QuantityTakeOff - Reference: 220 V
Type - Pset_ProvisionForVoid - Width: 53.975 mm; Height: 38.1 mm; Depth: 76.2 mm
Pset_BuildingElementProxyCommon - sets with these values: 2
Pset_ProductRequirements - Category: Generic Models
Pset_ProvisionForVoid - Width: 0.0164516 mm

# IfcBuildingElementProxy: M_Weather Proof Receptacle:220 V:1026947:220 V:1026947 : M_Weather Proof Receptacle:220 V:1026947:324500, M_Weather Proof Receptacle:220 V:1026947:220 V:1026947 : M_Weather Proof Receptacle:220 V:1026947:324500:220 V:1026947:220 V:1026947 : M_Weather Proof Receptacle:220 V:1026947:324500 : M_Weather Proof Receptacle:220 V:1026947:220 V:1026947 : M_Weather Proof Receptacle:220 V:1026947:324500:323652
In: Level 1
Type - Material: <Unnamed> (2)
Type - Pset_BuildingElementProxyCommon - Reference: 220 V
Type - Pset_ProductRequirements - Category: Electrical Fixtures
Type - Pset_QuantityTakeOff - Reference: 220 V
Type - Pset_ProvisionForVoid - Width: 53.975 mm; Height: 38.1 mm; Depth: 76.2 mm
Pset_BuildingElementProxyCommon - sets with these values: 2
Pset_ProductRequirements - Category: Generic Models
Pset_ProvisionForVoid - Width: 0.0164516 mm

# IfcBuildingElementProxy: M_Weather Proof Receptacle:220 V:1026949:220 V:1026949 : M_Weather Proof Receptacle:220 V:1026949:325082, M_Weather Proof Receptacle:220 V:1026949:220 V:1026949 : M_Weather Proof Receptacle:220 V:1026949:325082:220 V:1026949:220 V:1026949 : M_Weather Proof Receptacle:220 V:1026949:325082 : M_Weather Proof Receptacle:220 V:1026949:220 V:1026949 : M_Weather Proof Receptacle:220 V:1026949:325082:323930
In: Level 1
Type - Material: <Unnamed> (2)
Type - Pset_BuildingElementProxyCommon - Reference: 220 V
Type - Pset_ProductRequirements - Category: Electrical Fixtures
Type - Pset_QuantityTakeOff - Reference: 220 V
Type - Pset_ProvisionForVoid - Width: 53.975 mm; Height: 38.1 mm; Depth: 76.2 mm
Pset_BuildingElementProxyCommon - sets with these values: 2
Pset_ProductRequirements - Category: Generic Models
Pset_ProvisionForVoid - Width: 0.0164516 mm

# IfcBuildingElementProxy: Outdoor LG simple box KRIPIS v1 SYSTEMS:ARUN080LTE4:1030513:ARUN080LTE4:1030513 : Outdoor LG simple box KRIPIS v1 SYSTEMS:ARUN080LTE4:1030513:327373, Outdoor LG simple box KRIPIS v1 SYSTEMS:ARUN080LTE4:1030513:ARUN080LTE4:1030513 : Outdoor LG simple box KRIPIS v1 SYSTEMS:ARUN080LTE4:1030513:327373:ARUN080LTE4:1030513:ARUN080LTE4:1030513 : Outdoor LG simple box KRIPIS v1 SYSTEMS:ARUN080LTE4:1030513:327373 : Outdoor LG simple box KRIPIS v1 SYSTEMS:ARUN080LTE4:1030513:ARUN080LTE4:1030513 : Outdoor LG simple box KRIPIS v1 SYSTEMS:ARUN080LTE4:1030513:327373:326695
In: Level 2
Type - Material: <Unnamed>
Type - Pset_BuildingElementProxyCommon - Reference: ARUN080LTE4
Type - Pset_ProductRequirements - Category: Mechanical Equipment
Type - Pset_QuantityTakeOff - Reference: ARUN080LTE4
Type - Pset_ProvisionForVoid - Width: 800 mm; Height: 1200 mm; Depth: 1700 mm
Pset_BuildingElementProxyCommon - sets with these values: 2
Pset_ProductRequirements - Category: Generic Models
Pset_ProvisionForVoid - Width: 0.24384 mm

# IfcBuildingElementProxy: Outdoor LG simple box KRIPIS v1 SYSTEMS:ARUN100LTE4:933655:ARUN100LTE4:933655 : Outdoor LG simple box KRIPIS v1 SYSTEMS:ARUN100LTE4:933655:326445, Outdoor LG simple box KRIPIS v1 SYSTEMS:ARUN100LTE4:933655:ARUN100LTE4:933655 : Outdoor LG simple box KRIPIS v1 SYSTEMS:ARUN100LTE4:933655:326445:ARUN100LTE4:933655:ARUN100LTE4:933655 : Outdoor LG simple box KRIPIS v1 SYSTEMS:ARUN100LTE4:933655:326445 : Outdoor LG simple box KRIPIS v1 SYSTEMS:ARUN100LTE4:933655:ARUN100LTE4:933655 : Outdoor LG simple box KRIPIS v1 SYSTEMS:ARUN100LTE4:933655:326445:325815
In: Level 2
Type - Material: <Unnamed>
Type - Pset_BuildingElementProxyCommon - Reference: ARUN100LTE4
Type - Pset_ProductRequirements - Category: Mechanical Equipment
Type - Pset_QuantityTakeOff - Reference: ARUN100LTE4
Type - Pset_ProvisionForVoid - Width: 800 mm; Height: 1200 mm; Depth: 1700 mm
Pset_BuildingElementProxyCommon - sets with these values: 2
Pset_ProductRequirements - Category: Generic Models
Pset_ProvisionForVoid - Width: 0.24384 mm

# IfcBuildingElementProxy: PV Inclined Modules v8:6 Module:1027088:6 Module:1027088 : PV Inclined Modules v8:6 Module:1027088:329184, PV Inclined Modules v8:6 Module:1027088:6 Module:1027088 : PV Inclined Modules v8:6 Module:1027088:329184:6 Module:1027088:6 Module:1027088 : PV Inclined Modules v8:6 Module:1027088:329184 : PV Inclined Modules v8:6 Module:1027088:6 Module:1027088 : PV Inclined Modules v8:6 Module:1027088:329184:327877
In: Top
Type - Material: <Unnamed>
Type - Pset_BuildingElementProxyCommon - Reference: 6 Module
Type - Pset_ProductRequirements - Category: Mechanical Equipment
Type - Pset_QuantityTakeOff - Reference: 6 Module
Type - Pset_ProvisionForVoid - Depth: 6000 mm
Pset_BuildingElementProxyCommon - sets with these values: 2
Pset_ProductRequirements - Category: Generic Models

# IfcBuildingElementProxy: PV Inclined Modules v8:6 Module:1027090:6 Module:1027090 : PV Inclined Modules v8:6 Module:1027090:329212, PV Inclined Modules v8:6 Module:1027090:6 Module:1027090 : PV Inclined Modules v8:6 Module:1027090:329212:6 Module:1027090:6 Module:1027090 : PV Inclined Modules v8:6 Module:1027090:329212 : PV Inclined Modules v8:6 Module:1027090:6 Module:1027090 : PV Inclined Modules v8:6 Module:1027090:329212:327905
In: Top
Type - Material: <Unnamed>
Type - Pset_BuildingElementProxyCommon - Reference: 6 Module
Type - Pset_ProductRequirements - Category: Mechanical Equipment
Type - Pset_QuantityTakeOff - Reference: 6 Module
Type - Pset_ProvisionForVoid - Depth: 6000 mm
Pset_BuildingElementProxyCommon - sets with these values: 2
Pset_ProductRequirements - Category: Generic Models

# IfcBuildingElementProxy: PV Inclined Modules v8:6 Module:1027091:6 Module:1027091 : PV Inclined Modules v8:6 Module:1027091:329226, PV Inclined Modules v8:6 Module:1027091:6 Module:1027091 : PV Inclined Modules v8:6 Module:1027091:329226:6 Module:1027091:6 Module:1027091 : PV Inclined Modules v8:6 Module:1027091:329226 : PV Inclined Modules v8:6 Module:1027091:6 Module:1027091 : PV Inclined Modules v8:6 Module:1027091:329226:327919
In: Top
Type - Material: <Unnamed>
Type - Pset_BuildingElementProxyCommon - Reference: 6 Module
Type - Pset_ProductRequirements - Category: Mechanical Equipment
Type - Pset_QuantityTakeOff - Reference: 6 Module
Type - Pset_ProvisionForVoid - Depth: 6000 mm
Pset_BuildingElementProxyCommon - sets with these values: 2
Pset_ProductRequirements - Category: Generic Models

# IfcBuildingElementProxy: PV Inclined Modules v8:6 Module:1027094:6 Module:1027094 : PV Inclined Modules v8:6 Module:1027094:329268, PV Inclined Modules v8:6 Module:1027094:6 Module:1027094 : PV Inclined Modules v8:6 Module:1027094:329268:6 Module:1027094:6 Module:1027094 : PV Inclined Modules v8:6 Module:1027094:329268 : PV Inclined Modules v8:6 Module:1027094:6 Module:1027094 : PV Inclined Modules v8:6 Module:1027094:329268:327961
In: Top
Type - Material: <Unnamed>
Type - Pset_BuildingElementProxyCommon - Reference: 6 Module
Type - Pset_ProductRequirements - Category: Mechanical Equipment
Type - Pset_QuantityTakeOff - Reference: 6 Module
Type - Pset_ProvisionForVoid - Depth: 6000 mm
Pset_BuildingElementProxyCommon - sets with these values: 2
Pset_ProductRequirements - Category: Generic Models

# IfcBuildingElementProxy: PV Inclined Modules v8:6 Module:1027095:6 Module:1027095 : PV Inclined Modules v8:6 Module:1027095:329282, PV Inclined Modules v8:6 Module:1027095:6 Module:1027095 : PV Inclined Modules v8:6 Module:1027095:329282:6 Module:1027095:6 Module:1027095 : PV Inclined Modules v8:6 Module:1027095:329282 : PV Inclined Modules v8:6 Module:1027095:6 Module:1027095 : PV Inclined Modules v8:6 Module:1027095:329282:327975
In: Top
Type - Material: <Unnamed>
Type - Pset_BuildingElementProxyCommon - Reference: 6 Module
Type - Pset_ProductRequirements - Category: Mechanical Equipment
Type - Pset_QuantityTakeOff - Reference: 6 Module
Type - Pset_ProvisionForVoid - Depth: 6000 mm
Pset_BuildingElementProxyCommon - sets with these values: 2
Pset_ProductRequirements - Category: Generic Models

# IfcBuildingElementProxy: PV Inclined Modules v8:7 Module:1027087:7 Module:1027087 : PV Inclined Modules v8:7 Module:1027087:329166, PV Inclined Modules v8:7 Module:1027087:7 Module:1027087 : PV Inclined Modules v8:7 Module:1027087:329166:7 Module:1027087:7 Module:1027087 : PV Inclined Modules v8:7 Module:1027087:329166 : PV Inclined Modules v8:7 Module:1027087:7 Module:1027087 : PV Inclined Modules v8:7 Module:1027087:329166:327863
In: Top
Type - Material: <Unnamed>
Type - Pset_BuildingElementProxyCommon - Reference: 7 Module
Type - Pset_ProductRequirements - Category: Mechanical Equipment
Type - Pset_QuantityTakeOff - Reference: 7 Module
Type - Pset_ProvisionForVoid - Depth: 7000 mm
Pset_BuildingElementProxyCommon - sets with these values: 2
Pset_ProductRequirements - Category: Generic Models

# IfcBuildingElementProxy: PV Inclined Modules v8:7 Module:1027089:7 Module:1027089 : PV Inclined Modules v8:7 Module:1027089:329198, PV Inclined Modules v8:7 Module:1027089:7 Module:1027089 : PV Inclined Modules v8:7 Module:1027089:329198:7 Module:1027089:7 Module:1027089 : PV Inclined Modules v8:7 Module:1027089:329198 : PV Inclined Modules v8:7 Module:1027089:7 Module:1027089 : PV Inclined Modules v8:7 Module:1027089:329198:327891
In: Top
Type - Material: <Unnamed>
Type - Pset_BuildingElementProxyCommon - Reference: 7 Module
Type - Pset_ProductRequirements - Category: Mechanical Equipment
Type - Pset_QuantityTakeOff - Reference: 7 Module
Type - Pset_ProvisionForVoid - Depth: 7000 mm
Pset_BuildingElementProxyCommon - sets with these values: 2
Pset_ProductRequirements - Category: Generic Models

# IfcBuildingElementProxy: PV Inclined Modules v8:7 Module:1027092:7 Module:1027092 : PV Inclined Modules v8:7 Module:1027092:329240, PV Inclined Modules v8:7 Module:1027092:7 Module:1027092 : PV Inclined Modules v8:7 Module:1027092:329240:7 Module:1027092:7 Module:1027092 : PV Inclined Modules v8:7 Module:1027092:329240 : PV Inclined Modules v8:7 Module:1027092:7 Module:1027092 : PV Inclined Modules v8:7 Module:1027092:329240:327933
In: Top
Type - Material: <Unnamed>
Type - Pset_BuildingElementProxyCommon - Reference: 7 Module
Type - Pset_ProductRequirements - Category: Mechanical Equipment
Type - Pset_QuantityTakeOff - Reference: 7 Module
Type - Pset_ProvisionForVoid - Depth: 7000 mm
Pset_BuildingElementProxyCommon - sets with these values: 2
Pset_ProductRequirements - Category: Generic Models

# IfcBuildingElementProxy: PV Inclined Modules v8:7 Module:1027093:7 Module:1027093 : PV Inclined Modules v8:7 Module:1027093:329254, PV Inclined Modules v8:7 Module:1027093:7 Module:1027093 : PV Inclined Modules v8:7 Module:1027093:329254:7 Module:1027093:7 Module:1027093 : PV Inclined Modules v8:7 Module:1027093:329254 : PV Inclined Modules v8:7 Module:1027093:7 Module:1027093 : PV Inclined Modules v8:7 Module:1027093:329254:327947
In: Top
Type - Material: <Unnamed>
Type - Pset_BuildingElementProxyCommon - Reference: 7 Module
Type - Pset_ProductRequirements - Category: Mechanical Equipment
Type - Pset_QuantityTakeOff - Reference: 7 Module
Type - Pset_ProvisionForVoid - Depth: 7000 mm
Pset_BuildingElementProxyCommon - sets with these values: 2
Pset_ProductRequirements - Category: Generic Models

# IfcBuildingElementProxy: Plugwise SENSE v1:Plugwise SENSE v1:1027549:Plugwise SENSE v1:1027549 : Plugwise SENSE v1:Plugwise SENSE v1:1027549:324901, Plugwise SENSE v1:Plugwise SENSE v1:1027549:Plugwise SENSE v1:1027549 : Plugwise SENSE v1:Plugwise SENSE v1:1027549:324901:Plugwise SENSE v1:1027549:Plugwise SENSE v1:1027549 : Plugwise SENSE v1:Plugwise SENSE v1:1027549:324901 : Plugwise SENSE v1:Plugwise SENSE v1:1027549:Plugwise SENSE v1:1027549 : Plugwise SENSE v1:Plugwise SENSE v1:1027549:324901:325233
In: Level 1
Type - Material: <Unnamed> (3)
Type - Pset_BuildingElementProxyCommon - Reference: Plugwise SENSE v1
Type - Pset_ManufacturerTypeInformation - Manufacturer: Plugwise
Type - Pset_ProductRequirements - Category: Specialty Equipment
Type - Pset_QuantityTakeOff - Reference: Plugwise SENSE v1
Type - Pset_ProvisionForVoid - Width: 4.6875 mm; Height: 1 mm; Depth: 1 mm
Pset_BuildingElementProxyCommon - sets with these values: 2
Pset_ProductRequirements - Category: Generic Models
Pset_ProvisionForVoid - Width: 0.00142875 mm

# IfcBuildingElementProxy: Plugwise SENSE v1:Plugwise SENSE v1:1027551:Plugwise SENSE v1:1027551 : Plugwise SENSE v1:Plugwise SENSE v1:1027551:323975, Plugwise SENSE v1:Plugwise SENSE v1:1027551:Plugwise SENSE v1:1027551 : Plugwise SENSE v1:Plugwise SENSE v1:1027551:323975:Plugwise SENSE v1:1027551:Plugwise SENSE v1:1027551 : Plugwise SENSE v1:Plugwise SENSE v1:1027551:323975 : Plugwise SENSE v1:Plugwise SENSE v1:1027551:Plugwise SENSE v1:1027551 : Plugwise SENSE v1:Plugwise SENSE v1:1027551:323975:324939
In: Level 1
Type - Material: <Unnamed> (3)
Type - Pset_BuildingElementProxyCommon - Reference: Plugwise SENSE v1
Type - Pset_ManufacturerTypeInformation - Manufacturer: Plugwise
Type - Pset_ProductRequirements - Category: Specialty Equipment
Type - Pset_QuantityTakeOff - Reference: Plugwise SENSE v1
Type - Pset_ProvisionForVoid - Width: 4.6875 mm; Height: 1 mm; Depth: 1 mm
Pset_BuildingElementProxyCommon - sets with these values: 2
Pset_ProductRequirements - Category: Generic Models
Pset_ProvisionForVoid - Width: 0.00142875 mm

# IfcBuildingElementProxy: Solar Collector v1:Custom Type:1027416:Custom Type:1027416 : Solar Collector v1:Custom Type:1027416:329296, Solar Collector v1:Custom Type:1027416:Custom Type:1027416 : Solar Collector v1:Custom Type:1027416:329296:Custom Type:1027416:Custom Type:1027416 : Solar Collector v1:Custom Type:1027416:329296 : Solar Collector v1:Custom Type:1027416:Custom Type:1027416 : Solar Collector v1:Custom Type:1027416:329296:327989
In: Top
Type - Material: <Unnamed>
Type - Pset_BuildingElementProxyCommon - Reference: Custom Type
Type - Pset_ProductRequirements - Category: Mechanical Equipment
Type - Pset_QuantityTakeOff - Reference: Custom Type
Type - Pset_ProvisionForVoid - Depth: 1250 mm
Pset_BuildingElementProxyCommon - sets with these values: 2
Pset_ProductRequirements - Category: Generic Models

# IfcBuildingElementProxy: Thermostat Kripis v3:Standard:1027207:Standard:1027207 : Thermostat Kripis v3:Standard:1027207:323935, Thermostat Kripis v3:Standard:1027207:Standard:1027207 : Thermostat Kripis v3:Standard:1027207:323935:Standard:1027207:Standard:1027207 : Thermostat Kripis v3:Standard:1027207:323935 : Thermostat Kripis v3:Standard:1027207:Standard:1027207 : Thermostat Kripis v3:Standard:1027207:323935:323445
In: Level 1
Type - Material: <Unnamed> (2)
Type - Pset_BuildingElementProxyCommon - Reference: Standard
Type - Pset_ProductRequirements - Name: Thermostat_B; Category: Mechanical Equipment
Type - Pset_QuantityTakeOff - Reference: Standard
Type - Pset_ProvisionForVoid - Width: 53.975 mm; Height: 38.1 mm; Depth: 76.2 mm
Pset_BuildingElementProxyCommon - sets with these values: 2
Pset_ProductRequirements - Category: Generic Models
Pset_ProvisionForVoid - Width: 0.0164516 mm

# IfcBuildingElementProxy: Thermostat Kripis v3:Standard:1027405:Standard:1027405 : Thermostat Kripis v3:Standard:1027405:323404, Thermostat Kripis v3:Standard:1027405:Standard:1027405 : Thermostat Kripis v3:Standard:1027405:323404:Standard:1027405:Standard:1027405 : Thermostat Kripis v3:Standard:1027405:323404 : Thermostat Kripis v3:Standard:1027405:Standard:1027405 : Thermostat Kripis v3:Standard:1027405:323404:323010
In: Level 1
Type - Material: <Unnamed> (2)
Type - Pset_BuildingElementProxyCommon - Reference: Standard
Type - Pset_ProductRequirements - Name: Thermostat_C; Category: Mechanical Equipment
Type - Pset_QuantityTakeOff - Reference: Standard
Type - Pset_ProvisionForVoid - Width: 53.975 mm; Height: 38.1 mm; Depth: 76.2 mm
Pset_BuildingElementProxyCommon - sets with these values: 2
Pset_ProductRequirements - Category: Generic Models
Pset_ProvisionForVoid - Width: 0.0164516 mm
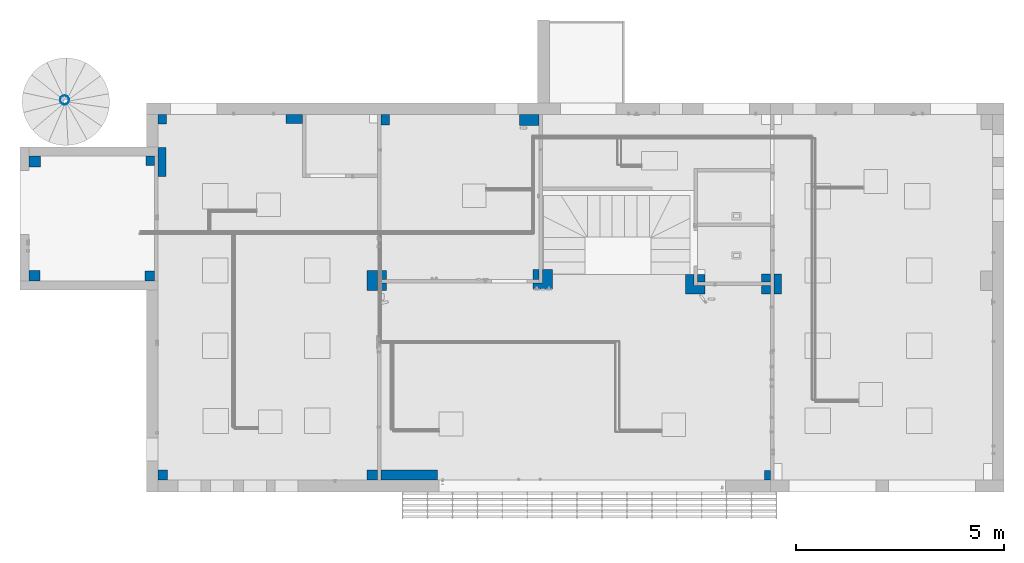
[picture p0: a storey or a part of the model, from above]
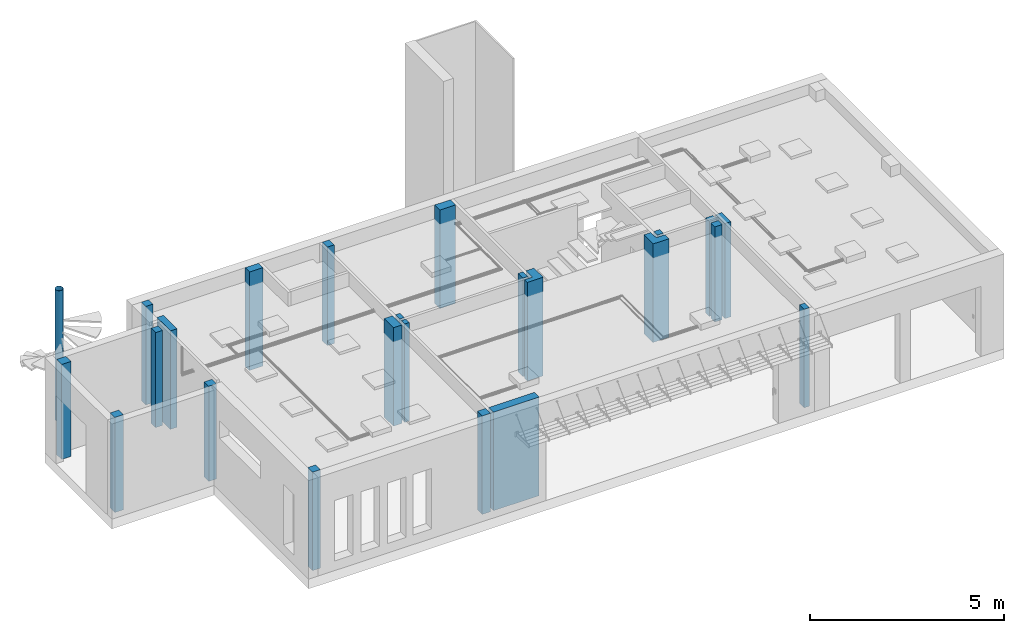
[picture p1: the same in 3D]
Properties of the parts of a building model (IFC2X3), part 3 of 5

# IfcBuildingElementProxy: Thermostat Kripis v3:Standard:1027406:Standard:1027406 : Thermostat Kripis v3:Standard:1027406:324668, Thermostat Kripis v3:Standard:1027406:Standard:1027406 : Thermostat Kripis v3:Standard:1027406:324668:Standard:1027406:Standard:1027406 : Thermostat Kripis v3:Standard:1027406:324668 : Thermostat Kripis v3:Standard:1027406:Standard:1027406 : Thermostat Kripis v3:Standard:1027406:324668:323820
In: Level 1
Type - Material: <Unnamed> (2)
Type - Pset_BuildingElementProxyCommon - Reference: Standard
Type - Pset_ProductRequirements - Name: Thermostat_F; Category: Mechanical Equipment
Type - Pset_QuantityTakeOff - Reference: Standard
Type - Pset_ProvisionForVoid - Width: 53.975 mm; Height: 38.1 mm; Depth: 76.2 mm
Pset_BuildingElementProxyCommon - sets with these values: 2
Pset_ProductRequirements - Category: Generic Models
Pset_ProvisionForVoid - Width: 0.0164516 mm

# IfcBuildingElementProxy: Thermostat Kripis v3:Standard:1027407:Standard:1027407 : Thermostat Kripis v3:Standard:1027407:325523, Thermostat Kripis v3:Standard:1027407:Standard:1027407 : Thermostat Kripis v3:Standard:1027407:325523:Standard:1027407:Standard:1027407 : Thermostat Kripis v3:Standard:1027407:325523 : Thermostat Kripis v3:Standard:1027407:Standard:1027407 : Thermostat Kripis v3:Standard:1027407:325523:324299
In: Level 1
Type - Material: <Unnamed> (2)
Type - Pset_BuildingElementProxyCommon - Reference: Standard
Type - Pset_ProductRequirements - Name: Thermostat_G; Category: Mechanical Equipment
Type - Pset_QuantityTakeOff - Reference: Standard
Type - Pset_ProvisionForVoid - Width: 53.975 mm; Height: 38.1 mm; Depth: 76.2 mm
Pset_BuildingElementProxyCommon - sets with these values: 2
Pset_ProductRequirements - Category: Generic Models
Pset_ProvisionForVoid - Width: 0.0164516 mm

# IfcBuildingElementProxy: Thermostat Kripis v3:Standard:1027408:Standard:1027408 : Thermostat Kripis v3:Standard:1027408:327906, Thermostat Kripis v3:Standard:1027408:Standard:1027408 : Thermostat Kripis v3:Standard:1027408:327906:Standard:1027408:Standard:1027408 : Thermostat Kripis v3:Standard:1027408:327906 : Thermostat Kripis v3:Standard:1027408:Standard:1027408 : Thermostat Kripis v3:Standard:1027408:327906:326901
In: Level 2
Type - Material: <Unnamed> (2)
Type - Pset_BuildingElementProxyCommon - Reference: Standard
Type - Pset_ProductRequirements - Name: Thermostat_I; Category: Mechanical Equipment
Type - Pset_QuantityTakeOff - Reference: Standard
Type - Pset_ProvisionForVoid - Width: 53.975 mm; Height: 38.1 mm; Depth: 76.2 mm
Pset_BuildingElementProxyCommon - sets with these values: 2
Pset_ProductRequirements - Category: Generic Models
Pset_ProvisionForVoid - Width: 0.0164516 mm

# IfcBuildingElementProxy: Thermostat Kripis v3:Standard:1027410:Standard:1027410 : Thermostat Kripis v3:Standard:1027410:327927, Thermostat Kripis v3:Standard:1027410:Standard:1027410 : Thermostat Kripis v3:Standard:1027410:327927:Standard:1027410:Standard:1027410 : Thermostat Kripis v3:Standard:1027410:327927 : Thermostat Kripis v3:Standard:1027410:Standard:1027410 : Thermostat Kripis v3:Standard:1027410:327927:326922
In: Level 2
Type - Material: <Unnamed> (2)
Type - Pset_BuildingElementProxyCommon - Reference: Standard
Type - Pset_ProductRequirements - Name: Thermostat_J; Category: Mechanical Equipment
Type - Pset_QuantityTakeOff - Reference: Standard
Type - Pset_ProvisionForVoid - Width: 53.975 mm; Height: 38.1 mm; Depth: 76.2 mm
Pset_BuildingElementProxyCommon - sets with these values: 2
Pset_ProductRequirements - Category: Generic Models
Pset_ProvisionForVoid - Width: 0.0164516 mm

# IfcBuildingElementProxy: Thermostat Kripis v3:Standard:1027411:Standard:1027411 : Thermostat Kripis v3:Standard:1027411:328494, Thermostat Kripis v3:Standard:1027411:Standard:1027411 : Thermostat Kripis v3:Standard:1027411:328494:Standard:1027411:Standard:1027411 : Thermostat Kripis v3:Standard:1027411:328494 : Thermostat Kripis v3:Standard:1027411:Standard:1027411 : Thermostat Kripis v3:Standard:1027411:328494:327345
In: Level 2
Type - Material: <Unnamed> (2)
Type - Pset_BuildingElementProxyCommon - Reference: Standard
Type - Pset_ProductRequirements - Name: Thermostat_K; Category: Mechanical Equipment
Type - Pset_QuantityTakeOff - Reference: Standard
Type - Pset_ProvisionForVoid - Width: 53.975 mm; Height: 38.1 mm; Depth: 76.2 mm
Pset_BuildingElementProxyCommon - sets with these values: 2
Pset_ProductRequirements - Category: Generic Models
Pset_ProvisionForVoid - Width: 0.0164516 mm

# IfcBuildingElementProxy: Thermostat Kripis v3:Standard:1027412:Standard:1027412 : Thermostat Kripis v3:Standard:1027412:328690, Thermostat Kripis v3:Standard:1027412:Standard:1027412 : Thermostat Kripis v3:Standard:1027412:328690:Standard:1027412:Standard:1027412 : Thermostat Kripis v3:Standard:1027412:328690 : Thermostat Kripis v3:Standard:1027412:Standard:1027412 : Thermostat Kripis v3:Standard:1027412:328690:327435
In: Level 2
Type - Material: <Unnamed> (2)
Type - Pset_BuildingElementProxyCommon - Reference: Standard
Type - Pset_ProductRequirements - Name: Thermostat_L; Category: Mechanical Equipment
Type - Pset_QuantityTakeOff - Reference: Standard
Type - Pset_ProvisionForVoid - Width: 53.975 mm; Height: 38.1 mm; Depth: 76.2 mm
Pset_BuildingElementProxyCommon - sets with these values: 2
Pset_ProductRequirements - Category: Generic Models
Pset_ProvisionForVoid - Width: 0.0164516 mm

# IfcBuildingElementProxy: Thermostat Kripis v3:Standard:1027413:Standard:1027413 : Thermostat Kripis v3:Standard:1027413:328861, Thermostat Kripis v3:Standard:1027413:Standard:1027413 : Thermostat Kripis v3:Standard:1027413:328861:Standard:1027413:Standard:1027413 : Thermostat Kripis v3:Standard:1027413:328861 : Thermostat Kripis v3:Standard:1027413:Standard:1027413 : Thermostat Kripis v3:Standard:1027413:328861:327546
In: Level 2
Type - Material: <Unnamed> (2)
Type - Pset_BuildingElementProxyCommon - Reference: Standard
Type - Pset_ProductRequirements - Name: Thermostat_M; Category: Mechanical Equipment
Type - Pset_QuantityTakeOff - Reference: Standard
Type - Pset_ProvisionForVoid - Width: 53.975 mm; Height: 38.1 mm; Depth: 76.2 mm
Pset_BuildingElementProxyCommon - sets with these values: 2
Pset_ProductRequirements - Category: Generic Models
Pset_ProvisionForVoid - Width: 0.0164516 mm

# IfcBuildingElementProxy: Thermostat Kripis v3:Standard:1027414:Standard:1027414 : Thermostat Kripis v3:Standard:1027414:329094, Thermostat Kripis v3:Standard:1027414:Standard:1027414 : Thermostat Kripis v3:Standard:1027414:329094:Standard:1027414:Standard:1027414 : Thermostat Kripis v3:Standard:1027414:329094 : Thermostat Kripis v3:Standard:1027414:Standard:1027414 : Thermostat Kripis v3:Standard:1027414:329094:327678
In: Level 2
Type - Material: <Unnamed> (2)
Type - Pset_BuildingElementProxyCommon - Reference: Standard
Type - Pset_ProductRequirements - Name: Thermostat_N; Category: Mechanical Equipment
Type - Pset_QuantityTakeOff - Reference: Standard
Type - Pset_ProvisionForVoid - Width: 53.975 mm; Height: 38.1 mm; Depth: 76.2 mm
Pset_BuildingElementProxyCommon - sets with these values: 2
Pset_ProductRequirements - Category: Generic Models
Pset_ProvisionForVoid - Width: 0.0164516 mm

# IfcBuildingElementProxy: Thermostat Kripis v3:Standard:1027415:Standard:1027415 : Thermostat Kripis v3:Standard:1027415:325544, Thermostat Kripis v3:Standard:1027415:Standard:1027415 : Thermostat Kripis v3:Standard:1027415:325544:Standard:1027415:Standard:1027415 : Thermostat Kripis v3:Standard:1027415:325544 : Thermostat Kripis v3:Standard:1027415:Standard:1027415 : Thermostat Kripis v3:Standard:1027415:325544:324320
In: Level 1
Type - Material: <Unnamed> (2)
Type - Pset_BuildingElementProxyCommon - Reference: Standard
Type - Pset_ProductRequirements - Name: Thermostat_H; Category: Mechanical Equipment
Type - Pset_QuantityTakeOff - Reference: Standard
Type - Pset_ProvisionForVoid - Width: 53.975 mm; Height: 38.1 mm; Depth: 76.2 mm
Pset_BuildingElementProxyCommon - sets with these values: 2
Pset_ProductRequirements - Category: Generic Models
Pset_ProvisionForVoid - Width: 0.0164516 mm

# IfcBuildingElementProxy: Thermostat Kripis v3:Standard:1027534:Standard:1027534 : Thermostat Kripis v3:Standard:1027534:324689, Thermostat Kripis v3:Standard:1027534:Standard:1027534 : Thermostat Kripis v3:Standard:1027534:324689:Standard:1027534:Standard:1027534 : Thermostat Kripis v3:Standard:1027534:324689 : Thermostat Kripis v3:Standard:1027534:Standard:1027534 : Thermostat Kripis v3:Standard:1027534:324689:323841
In: Level 1
Type - Material: <Unnamed> (2)
Type - Pset_BuildingElementProxyCommon - Reference: Standard
Type - Pset_ProductRequirements - Name: Thermostat_E; Category: Mechanical Equipment
Type - Pset_QuantityTakeOff - Reference: Standard
Type - Pset_ProvisionForVoid - Width: 53.975 mm; Height: 38.1 mm; Depth: 76.2 mm
Pset_BuildingElementProxyCommon - sets with these values: 2
Pset_ProductRequirements - Category: Generic Models
Pset_ProvisionForVoid - Width: 0.0164516 mm

# IfcBuildingElementProxy: Thermostat Kripis v3:Standard:1027536:Standard:1027536 : Thermostat Kripis v3:Standard:1027536:324710, Thermostat Kripis v3:Standard:1027536:Standard:1027536 : Thermostat Kripis v3:Standard:1027536:324710:Standard:1027536:Standard:1027536 : Thermostat Kripis v3:Standard:1027536:324710 : Thermostat Kripis v3:Standard:1027536:Standard:1027536 : Thermostat Kripis v3:Standard:1027536:324710:323862
In: Level 1
Type - Material: <Unnamed> (2)
Type - Pset_BuildingElementProxyCommon - Reference: Standard
Type - Pset_ProductRequirements - Name: Thermostat_A; Category: Mechanical Equipment
Type - Pset_QuantityTakeOff - Reference: Standard
Type - Pset_ProvisionForVoid - Width: 53.975 mm; Height: 38.1 mm; Depth: 76.2 mm
Pset_BuildingElementProxyCommon - sets with these values: 2
Pset_ProductRequirements - Category: Generic Models
Pset_ProvisionForVoid - Width: 0.0164516 mm

# IfcBuildingElementProxy: Thermostat Kripis v3:Standard:1027538:Standard:1027538 : Thermostat Kripis v3:Standard:1027538:323715, Thermostat Kripis v3:Standard:1027538:Standard:1027538 : Thermostat Kripis v3:Standard:1027538:323715:Standard:1027538:Standard:1027538 : Thermostat Kripis v3:Standard:1027538:323715 : Thermostat Kripis v3:Standard:1027538:Standard:1027538 : Thermostat Kripis v3:Standard:1027538:323715:323313
In: Level 1
Type - Material: <Unnamed> (2)
Type - Pset_BuildingElementProxyCommon - Reference: Standard
Type - Pset_ProductRequirements - Name: Thermostat_D; Category: Mechanical Equipment
Type - Pset_QuantityTakeOff - Reference: Standard
Type - Pset_ProvisionForVoid - Width: 53.975 mm; Height: 38.1 mm; Depth: 76.2 mm
Pset_BuildingElementProxyCommon - sets with these values: 2
Pset_ProductRequirements - Category: Generic Models
Pset_ProvisionForVoid - Width: 0.0164516 mm

# IfcBuildingElementProxy: Water Heater Storage v1:Water Heater Storage v1:1027417:Water Heater Storage v1:1027417 : Water Heater Storage v1:Water Heater Storage v1:1027417:329310, Water Heater Storage v1:Water Heater Storage v1:1027417:Water Heater Storage v1:1027417 : Water Heater Storage v1:Water Heater Storage v1:1027417:329310:Water Heater Storage v1:1027417:Water Heater Storage v1:1027417 : Water Heater Storage v1:Water Heater Storage v1:1027417:329310 : Water Heater Storage v1:Water Heater Storage v1:1027417:Water Heater Storage v1:1027417 : Water Heater Storage v1:Water Heater Storage v1:1027417:329310:328003
In: Top
Type - Material: <Unnamed>
Type - Pset_BuildingElementProxyCommon - Reference: Water Heater Storage v1
Type - Pset_ProductRequirements - Category: Mechanical Equipment
Type - Pset_QuantityTakeOff - Reference: Water Heater Storage v1
Type - Pset_ProvisionForVoid - Depth: 1275 mm
Pset_BuildingElementProxyCommon - sets with these values: 2
Pset_ProductRequirements - Category: Generic Models

# IfcBuildingElementProxy: rac_advanced_sample_family:M_Solar_Shade_Complete:1027154:M_Solar_Shade_Complete:1027154 : rac_advanced_sample_family:M_Solar_Shade_Complete:1027154:322006, rac_advanced_sample_family:M_Solar_Shade_Complete:1027154:M_Solar_Shade_Complete:1027154 : rac_advanced_sample_family:M_Solar_Shade_Complete:1027154:322006:M_Solar_Shade_Complete:1027154:M_Solar_Shade_Complete:1027154 : rac_advanced_sample_family:M_Solar_Shade_Complete:1027154:322006 : rac_advanced_sample_family:M_Solar_Shade_Complete:1027154:M_Solar_Shade_Complete:1027154 : rac_advanced_sample_family:M_Solar_Shade_Complete:1027154:322006:321797
In: Level 1
Type - Material: Metal - Aluminum (32), Metal - Steel, Galvinized (16), Metal - Steel, Painted Maroon (32), Metal - Aluminum, Painted White (5)
Type - Pset_BuildingElementProxyCommon - Reference: M_Solar_Shade_Complete
Type - Pset_ProductRequirements - Category: Generic Models
Type - Pset_QuantityTakeOff - Reference: M_Solar_Shade_Complete
Type - Pset_ProvisionForVoid - Width: 653 mm; Height: 20 mm; Depth: 15 mm
Pset_BuildingElementProxyCommon - sets with these values: 2
Pset_ProvisionForVoid - Width: 0.199034 mm

# IfcBuildingElementProxy: radiator 18 v1:Type 1:1027418:Type 1:1027418 : radiator 18 v1:Type 1:1027418:328952, radiator 18 v1:Type 1:1027418:Type 1:1027418 : radiator 18 v1:Type 1:1027418:328952:Type 1:1027418:Type 1:1027418 : radiator 18 v1:Type 1:1027418:328952 : radiator 18 v1:Type 1:1027418:Type 1:1027418 : radiator 18 v1:Type 1:1027418:328952:327849
In: 13
Type - Material: <Unnamed>
Type - Pset_BuildingElementProxyCommon - Reference: Type 1
Type - Pset_ProductRequirements - Category: Mechanical Equipment
Type - Pset_QuantityTakeOff - Reference: Type 1
Type - Pset_ProvisionForVoid - Width: 125 mm; Height: 500 mm; Depth: 1800 mm
Pset_BuildingElementProxyCommon - sets with these values: 2
Pset_ProductRequirements - Category: Generic Models
Pset_ProvisionForVoid - Width: 0.0381 mm

# IfcColumn: Circular Hollow Sections-Column:TRON219x6.3:TRON219x6.3 : Circular Hollow Sections-Column:TRON219x6.3, Circular Hollow Sections-Column:TRON219x6.3:1027130
In: Level 1
Type - PredefinedType: COLUMN; Material: Polished Steel
Type - Pset_ColumnCommon - IsExternal: no; LoadBearing: yes
Type - Pset_ProductRequirements - Category: Structural Columns
Pset_ColumnCommon - Reference: TRON219x6.3
Pset_QuantityTakeOff - Reference: TRON219x6.3; sets with these values: 2

# IfcColumn: M_Rectangular Column:200 x 400mm 31511:200 x 400mm 31511 : M_Rectangular Column:200 x 400mm 31511, M_Rectangular Column:200 x 400mm:1026737
In: Level 2
Type - PredefinedType: COLUMN; Material: FIBRAN gyps SUPER
Type - Pset_ColumnCommon - IsExternal: no
Pset_ColumnCommon - Reference: 200 x 400mm
Pset_ProductRequirements - Category: Columns
Pset_QuantityTakeOff - Reference: 200 x 400mm; sets with these values: 2

# IfcColumn: M_Rectangular Column:200 x 400mm 31542:200 x 400mm 31542 : M_Rectangular Column:200 x 400mm 31542, M_Rectangular Column:200 x 400mm:1026736
In: Level 2
Type - PredefinedType: COLUMN; Material: FIBRAN gyps SUPER
Type - Pset_ColumnCommon - IsExternal: no
Pset_ColumnCommon - Reference: 200 x 400mm
Pset_ProductRequirements - Category: Columns
Pset_QuantityTakeOff - Reference: 200 x 400mm; sets with these values: 2

# IfcColumn: M_Rectangular Column:200 x 400mm 31573:200 x 400mm 31573 : M_Rectangular Column:200 x 400mm 31573, M_Rectangular Column:200 x 400mm:1026735
In: Level 2
Type - PredefinedType: COLUMN; Material: FIBRAN gyps SUPER
Type - Pset_ColumnCommon - IsExternal: no
Pset_ColumnCommon - Reference: 200 x 400mm
Pset_ProductRequirements - Category: Columns
Pset_QuantityTakeOff - Reference: 200 x 400mm; sets with these values: 2

# IfcColumn: M_Rectangular Column:200 x 400mm 31604:200 x 400mm 31604 : M_Rectangular Column:200 x 400mm 31604, M_Rectangular Column:200 x 400mm:1026734
In: Level 2
Type - PredefinedType: COLUMN; Material: FIBRAN gyps SUPER
Type - Pset_ColumnCommon - IsExternal: no
Pset_ColumnCommon - Reference: 200 x 400mm
Pset_ProductRequirements - Category: Columns
Pset_QuantityTakeOff - Reference: 200 x 400mm; sets with these values: 2

# IfcColumn: M_Rectangular Column:200 x 400mm 31708:200 x 400mm 31708 : M_Rectangular Column:200 x 400mm 31708, M_Rectangular Column:200 x 400mm:1026730
In: Level 2
Type - PredefinedType: COLUMN; Material: FIBRAN gyps SUPER
Type - Pset_ColumnCommon - IsExternal: no
Pset_ColumnCommon - Reference: 200 x 400mm
Pset_ProductRequirements - Category: Columns
Pset_QuantityTakeOff - Reference: 200 x 400mm; sets with these values: 2

# IfcColumn: M_Rectangular Column:200 x 400mm 31802:200 x 400mm 31802 : M_Rectangular Column:200 x 400mm 31802, M_Rectangular Column:200 x 400mm:1026726
In: Level 2
Type - PredefinedType: COLUMN; Material: FIBRAN gyps SUPER
Type - Pset_ColumnCommon - IsExternal: no
Pset_ColumnCommon - Reference: 200 x 400mm
Pset_ProductRequirements - Category: Columns
Pset_QuantityTakeOff - Reference: 200 x 400mm; sets with these values: 2

# IfcColumn: M_Rectangular Column:200 x 400mm 31833:200 x 400mm 31833 : M_Rectangular Column:200 x 400mm 31833, M_Rectangular Column:200 x 400mm:1026722
In: Level 2
Type - PredefinedType: COLUMN; Material: FIBRAN gyps SUPER
Type - Pset_ColumnCommon - IsExternal: no
Pset_ColumnCommon - Reference: 200 x 400mm
Pset_ProductRequirements - Category: Columns
Pset_QuantityTakeOff - Reference: 200 x 400mm; sets with these values: 2

# IfcColumn: M_Rectangular Column:200 x 400mm 31864:200 x 400mm 31864 : M_Rectangular Column:200 x 400mm 31864, M_Rectangular Column:200 x 400mm:1026721
In: Level 2
Type - PredefinedType: COLUMN; Material: FIBRAN gyps SUPER
Type - Pset_ColumnCommon - IsExternal: no
Pset_ColumnCommon - Reference: 200 x 400mm
Pset_ProductRequirements - Category: Columns
Pset_QuantityTakeOff - Reference: 200 x 400mm; sets with these values: 2

# IfcColumn: M_Rectangular Column:200 x 400mm 31895:200 x 400mm 31895 : M_Rectangular Column:200 x 400mm 31895, M_Rectangular Column:200 x 400mm:1026718
In: Level 2
Type - PredefinedType: COLUMN; Material: FIBRAN gyps SUPER
Type - Pset_ColumnCommon - IsExternal: no
Pset_ColumnCommon - Reference: 200 x 400mm
Pset_ProductRequirements - Category: Columns
Pset_QuantityTakeOff - Reference: 200 x 400mm; sets with these values: 2

# IfcColumn: M_Rectangular Column:200 x 400mm:200 x 400mm : M_Rectangular Column:200 x 400mm, M_Rectangular Column:200 x 400mm:1026738
In: Level 2
Type - PredefinedType: COLUMN; Material: FIBRAN gyps SUPER
Type - Pset_ColumnCommon - IsExternal: no
Pset_ColumnCommon - Reference: 200 x 400mm
Pset_ProductRequirements - Category: Columns
Pset_QuantityTakeOff - Reference: 200 x 400mm; sets with these values: 2

# IfcColumn: M_Rectangular Column:220 x 240mm 32246:220 x 240mm 32246 : M_Rectangular Column:220 x 240mm 32246, M_Rectangular Column:220 x 240mm:1026704
In: Level 1
Type - PredefinedType: COLUMN; Material: FIBRAN gyps SUPER
Type - Pset_ColumnCommon - IsExternal: no
Pset_ColumnCommon - Reference: 220 x 240mm
Pset_ProductRequirements - Category: Columns
Pset_QuantityTakeOff - Reference: 220 x 240mm; sets with these values: 2

# IfcColumn: M_Rectangular Column:220 x 240mm 32396:220 x 240mm 32396 : M_Rectangular Column:220 x 240mm 32396, M_Rectangular Column:220 x 240mm:1026699
In: Level 1
Type - PredefinedType: COLUMN; Material: FIBRAN gyps SUPER
Type - Pset_ColumnCommon - IsExternal: no
Pset_ColumnCommon - Reference: 220 x 240mm
Pset_ProductRequirements - Category: Columns
Pset_QuantityTakeOff - Reference: 220 x 240mm; sets with these values: 2

# IfcColumn: M_Rectangular Column:220 x 240mm:220 x 240mm : M_Rectangular Column:220 x 240mm, M_Rectangular Column:220 x 240mm:1026717
In: Level 1
Type - PredefinedType: COLUMN; Material: FIBRAN gyps SUPER
Type - Pset_ColumnCommon - IsExternal: no
Pset_ColumnCommon - Reference: 220 x 240mm
Pset_ProductRequirements - Category: Columns
Pset_QuantityTakeOff - Reference: 220 x 240mm; sets with these values: 2

# IfcColumn: M_Rectangular Column:260 x 260mm 31926:260 x 260mm 31926 : M_Rectangular Column:260 x 260mm 31926, M_Rectangular Column:260 x 260mm:1027325
In: Level 1
Type - PredefinedType: COLUMN; Material: FIBRAN gyps SUPER
Type - Pset_ColumnCommon - IsExternal: no
Pset_ColumnCommon - Reference: 260 x 260mm
Pset_ProductRequirements - Category: Columns
Pset_QuantityTakeOff - Reference: 260 x 260mm; sets with these values: 2

# IfcColumn: M_Rectangular Column:260 x 260mm 32186:260 x 260mm 32186 : M_Rectangular Column:260 x 260mm 32186, M_Rectangular Column:260 x 260mm:1026708
In: Level 1
Type - PredefinedType: COLUMN; Material: FIBRAN gyps SUPER
Type - Pset_ColumnCommon - IsExternal: no
Pset_ColumnCommon - Reference: 260 x 260mm
Pset_ProductRequirements - Category: Columns
Pset_QuantityTakeOff - Reference: 260 x 260mm; sets with these values: 2

# IfcColumn: M_Rectangular Column:260 x 260mm 32276:260 x 260mm 32276 : M_Rectangular Column:260 x 260mm 32276, M_Rectangular Column:260 x 260mm:1026703
In: Level 1
Type - PredefinedType: COLUMN; Material: FIBRAN gyps SUPER
Type - Pset_ColumnCommon - IsExternal: no
Pset_ColumnCommon - Reference: 260 x 260mm
Pset_ProductRequirements - Category: Columns
Pset_QuantityTakeOff - Reference: 260 x 260mm; sets with these values: 2

# IfcColumn: M_Rectangular Column:260 x 260mm 32306:260 x 260mm 32306 : M_Rectangular Column:260 x 260mm 32306, M_Rectangular Column:260 x 260mm:1026702
In: Level 1
Type - PredefinedType: COLUMN; Material: FIBRAN gyps SUPER
Type - Pset_ColumnCommon - IsExternal: no
Pset_ColumnCommon - Reference: 260 x 260mm
Pset_ProductRequirements - Category: Columns
Pset_QuantityTakeOff - Reference: 260 x 260mm; sets with these values: 2

# IfcColumn: M_Rectangular Column:260 x 260mm 32366:260 x 260mm 32366 : M_Rectangular Column:260 x 260mm 32366, M_Rectangular Column:260 x 260mm:1026700
In: Level 1
Type - PredefinedType: COLUMN; Material: FIBRAN gyps SUPER
Type - Pset_ColumnCommon - IsExternal: no
Pset_ColumnCommon - Reference: 260 x 260mm
Pset_ProductRequirements - Category: Columns
Pset_QuantityTakeOff - Reference: 260 x 260mm; sets with these values: 2

# IfcColumn: M_Rectangular Column:260 x 260mm:260 x 260mm : M_Rectangular Column:260 x 260mm, M_Rectangular Column:260 x 260mm:1026727
In: Level 2
Type - PredefinedType: COLUMN; Material: FIBRAN gyps SUPER
Type - Pset_ColumnCommon - IsExternal: no
Pset_ColumnCommon - Reference: 260 x 260mm
Pset_ProductRequirements - Category: Columns
Pset_QuantityTakeOff - Reference: 260 x 260mm; sets with these values: 2

# IfcColumn: M_Rectangular Column:475 x 475mm 32096:475 x 475mm 32096 : M_Rectangular Column:475 x 475mm 32096, M_Rectangular Column:475 x 475mm:1026715
In: Level 1
Type - PredefinedType: COLUMN; Material: FIBRAN gyps SUPER
Type - Pset_ColumnCommon - IsExternal: no
Pset_ColumnCommon - Reference: 475 x 475mm
Pset_ProductRequirements - Category: Columns
Pset_QuantityTakeOff - Reference: 475 x 475mm; sets with these values: 2

# IfcColumn: M_Rectangular Column:475 x 475mm 32126:475 x 475mm 32126 : M_Rectangular Column:475 x 475mm 32126, M_Rectangular Column:475 x 475mm:1026714
In: Level 1
Type - PredefinedType: COLUMN; Material: FIBRAN gyps SUPER
Type - Pset_ColumnCommon - IsExternal: no
Pset_ColumnCommon - Reference: 475 x 475mm
Pset_ProductRequirements - Category: Columns
Pset_QuantityTakeOff - Reference: 475 x 475mm; sets with these values: 2

# IfcColumn: M_Rectangular Column:475 x 475mm 32156:475 x 475mm 32156 : M_Rectangular Column:475 x 475mm 32156, M_Rectangular Column:475 x 475mm:1026709
In: Level 1
Type - PredefinedType: COLUMN; Material: FIBRAN gyps SUPER
Type - Pset_ColumnCommon - IsExternal: no
Pset_ColumnCommon - Reference: 475 x 475mm
Pset_ProductRequirements - Category: Columns
Pset_QuantityTakeOff - Reference: 475 x 475mm; sets with these values: 2

# IfcColumn: M_Rectangular Column:475 x 475mm 32216:475 x 475mm 32216 : M_Rectangular Column:475 x 475mm 32216, M_Rectangular Column:475 x 475mm:1026705
In: Level 1
Type - PredefinedType: COLUMN; Material: FIBRAN gyps SUPER
Type - Pset_ColumnCommon - IsExternal: no
Pset_ColumnCommon - Reference: 475 x 475mm
Pset_ProductRequirements - Category: Columns
Pset_QuantityTakeOff - Reference: 475 x 475mm; sets with these values: 2

# IfcColumn: M_Rectangular Column:475 x 475mm 32336:475 x 475mm 32336 : M_Rectangular Column:475 x 475mm 32336, M_Rectangular Column:475 x 475mm:1026701
In: Level 1
Type - PredefinedType: COLUMN; Material: FIBRAN gyps SUPER
Type - Pset_ColumnCommon - IsExternal: no
Pset_ColumnCommon - Reference: 475 x 475mm
Pset_ProductRequirements - Category: Columns
Pset_QuantityTakeOff - Reference: 475 x 475mm; sets with these values: 2

# IfcColumn: M_Rectangular Column:475 x 475mm:1026706:475 x 475mm:1026706 : M_Rectangular Column:475 x 475mm:1026706:321618, M_Rectangular Column:475 x 475mm:1026706:475 x 475mm:1026706 : M_Rectangular Column:475 x 475mm:1026706:321618:475 x 475mm:1026706:475 x 475mm:1026706 : M_Rectangular Column:475 x 475mm:1026706:321618 : M_Rectangular Column:475 x 475mm:1026706:475 x 475mm:1026706 : M_Rectangular Column:475 x 475mm:1026706:321618:321452
In: Level 1
Type - PredefinedType: COLUMN; Material: FIBRAN gyps SUPER
Type - Pset_ColumnCommon - IsExternal: no; Reference: 475 x 475mm
Type - Pset_ProductRequirements - Category: Columns
Type - Pset_QuantityTakeOff - Reference: 475 x 475mm
Type - Pset_ReinforcementBarPitchOfColumn - Reference: 475 x 475mm
Pset_QuantityTakeOff - sets with these values: 2

# IfcColumn: M_Rectangular Column:475 x 475mm:1026710:475 x 475mm:1026710 : M_Rectangular Column:475 x 475mm:1026710:321663, M_Rectangular Column:475 x 475mm:1026710:475 x 475mm:1026710 : M_Rectangular Column:475 x 475mm:1026710:321663:475 x 475mm:1026710:475 x 475mm:1026710 : M_Rectangular Column:475 x 475mm:1026710:321663 : M_Rectangular Column:475 x 475mm:1026710:475 x 475mm:1026710 : M_Rectangular Column:475 x 475mm:1026710:321663:321488
In: Level 1
Type - PredefinedType: COLUMN; Material: FIBRAN gyps SUPER
Type - Pset_ColumnCommon - IsExternal: no; Reference: 475 x 475mm
Type - Pset_ProductRequirements - Category: Columns
Type - Pset_QuantityTakeOff - Reference: 475 x 475mm
Type - Pset_ReinforcementBarPitchOfColumn - Reference: 475 x 475mm
Pset_QuantityTakeOff - sets with these values: 2

# IfcColumn: M_Rectangular Column:475 x 475mm:1026711:475 x 475mm:1026711 : M_Rectangular Column:475 x 475mm:1026711:321686, M_Rectangular Column:475 x 475mm:1026711:475 x 475mm:1026711 : M_Rectangular Column:475 x 475mm:1026711:321686:475 x 475mm:1026711:475 x 475mm:1026711 : M_Rectangular Column:475 x 475mm:1026711:321686 : M_Rectangular Column:475 x 475mm:1026711:475 x 475mm:1026711 : M_Rectangular Column:475 x 475mm:1026711:321686:321511
In: Level 1
Type - PredefinedType: COLUMN; Material: FIBRAN gyps SUPER
Type - Pset_ColumnCommon - IsExternal: no; Reference: 475 x 475mm
Type - Pset_ProductRequirements - Category: Columns
Type - Pset_QuantityTakeOff - Reference: 475 x 475mm
Type - Pset_ReinforcementBarPitchOfColumn - Reference: 475 x 475mm
Pset_QuantityTakeOff - sets with these values: 2

# IfcColumn: M_Rectangular Column:475 x 475mm:1026712:475 x 475mm:1026712 : M_Rectangular Column:475 x 475mm:1026712:321709, M_Rectangular Column:475 x 475mm:1026712:475 x 475mm:1026712 : M_Rectangular Column:475 x 475mm:1026712:321709:475 x 475mm:1026712:475 x 475mm:1026712 : M_Rectangular Column:475 x 475mm:1026712:321709 : M_Rectangular Column:475 x 475mm:1026712:475 x 475mm:1026712 : M_Rectangular Column:475 x 475mm:1026712:321709:321534
In: Level 1
Type - PredefinedType: COLUMN; Material: FIBRAN gyps SUPER
Type - Pset_ColumnCommon - IsExternal: no; Reference: 475 x 475mm
Type - Pset_ProductRequirements - Category: Columns
Type - Pset_QuantityTakeOff - Reference: 475 x 475mm
Type - Pset_ReinforcementBarPitchOfColumn - Reference: 475 x 475mm
Pset_QuantityTakeOff - sets with these values: 2

# IfcColumn: M_Rectangular Column:475 x 475mm:1026731:475 x 475mm:1026731 : M_Rectangular Column:475 x 475mm:1026731:326489, M_Rectangular Column:475 x 475mm:1026731:475 x 475mm:1026731 : M_Rectangular Column:475 x 475mm:1026731:326489:475 x 475mm:1026731:475 x 475mm:1026731 : M_Rectangular Column:475 x 475mm:1026731:326489 : M_Rectangular Column:475 x 475mm:1026731:475 x 475mm:1026731 : M_Rectangular Column:475 x 475mm:1026731:326489:325829
In: Level 2
Type - PredefinedType: COLUMN; Material: FIBRAN gyps SUPER
Type - Pset_ColumnCommon - IsExternal: no; Reference: 475 x 475mm
Type - Pset_ProductRequirements - Category: Columns
Type - Pset_QuantityTakeOff - Reference: 475 x 475mm
Type - Pset_ReinforcementBarPitchOfColumn - Reference: 475 x 475mm
Pset_QuantityTakeOff - sets with these values: 2

# IfcColumn: M_Rectangular Column:475 x 475mm:475 x 475mm : M_Rectangular Column:475 x 475mm, M_Rectangular Column:475 x 475mm:1026729
In: Level 2
Type - PredefinedType: COLUMN; Material: FIBRAN gyps SUPER
Type - Pset_ColumnCommon - IsExternal: no
Pset_ColumnCommon - Reference: 475 x 475mm
Pset_ProductRequirements - Category: Columns
Pset_QuantityTakeOff - Reference: 475 x 475mm; sets with these values: 2

# IfcColumn: M_Rectangular Column:My toixio 200x700 mm 32035:My toixio 200x700 mm 32035 : M_Rectangular Column:My toixio 200x700 mm 32035, M_Rectangular Column:My toixio 200x700 mm:1026719
In: Level 1
Type - PredefinedType: COLUMN; Material: PAINT inside 31636
Type - Pset_ColumnCommon - IsExternal: no
Pset_ColumnCommon - Reference: My toixio 200x700 mm
Pset_ProductRequirements - Category: Columns
Pset_QuantityTakeOff - Reference: My toixio 200x700 mm; sets with these values: 2

# IfcColumn: M_Rectangular Column:My toixio 200x700 mm:My toixio 200x700 mm : M_Rectangular Column:My toixio 200x700 mm, M_Rectangular Column:My toixio 200x700 mm:1026733
In: Level 2
Type - PredefinedType: COLUMN; Material: PAINT inside 31636
Type - Pset_ColumnCommon - IsExternal: no
Pset_ColumnCommon - Reference: My toixio 200x700 mm
Pset_ProductRequirements - Category: Columns
Pset_QuantityTakeOff - Reference: My toixio 200x700 mm; sets with these values: 2

# IfcColumn: M_Rectangular Column:My toixio 300 x 1400 m:My toixio 300 x 1400 m : M_Rectangular Column:My toixio 300 x 1400 m, M_Rectangular Column:My toixio 300 x 1400 m:1026720
In: Level 1
Type - PredefinedType: COLUMN; Material: Gypsum Wall Board
Type - Pset_ColumnCommon - IsExternal: no
Pset_ColumnCommon - Reference: My toixio 300 x 1400 m
Pset_ProductRequirements - Category: Columns
Pset_QuantityTakeOff - Reference: My toixio 300 x 1400 m; sets with these values: 2

# IfcColumn: M_Rectangular Column:My toixio 300 x 900:My toixio 300 x 900 : M_Rectangular Column:My toixio 300 x 900, M_Rectangular Column:My toixio 300 x 900:1026732
In: Level 2
Type - PredefinedType: COLUMN; Material: PAINT inside 31636
Type - Pset_ColumnCommon - IsExternal: no
Pset_ColumnCommon - Reference: My toixio 300 x 900
Pset_ProductRequirements - Category: Columns
Pset_QuantityTakeOff - Reference: My toixio 300 x 900; sets with these values: 2

# IfcFlowFitting: M_Transition - Generic:Standard:1032318:Standard:1032318 : M_Transition - Generic:Standard:1032318:322880, M_Transition - Generic:Standard:1032318:Standard:1032318 : M_Transition - Generic:Standard:1032318:322880:Standard:1032318:Standard:1032318 : M_Transition - Generic:Standard:1032318:322880 : M_Transition - Generic:Standard:1032318:Standard:1032318 : M_Transition - Generic:Standard:1032318:322880:325270
In: Level 2
Type - Material: <Unnamed>
Type - Pset_DistributionFlowElementCommon - Reference: Standard
Type - Pset_ProductRequirements - Category: Pipe Fittings
Type - Pset_QuantityTakeOff - Reference: Standard
Pset_DistributionFlowElementCommon - sets with these values: 2

# IfcFlowFitting: M_Transition - Generic:Standard:922603:Standard:922603 : M_Transition - Generic:Standard:922603:328753, M_Transition - Generic:Standard:922603:Standard:922603 : M_Transition - Generic:Standard:922603:328753:Standard:922603:Standard:922603 : M_Transition - Generic:Standard:922603:328753 : M_Transition - Generic:Standard:922603:Standard:922603 : M_Transition - Generic:Standard:922603:328753:327470
In: Level 2
Type - Material: <Unnamed>
Type - Pset_DistributionFlowElementCommon - Reference: Standard
Type - Pset_ProductRequirements - Category: Pipe Fittings
Type - Pset_QuantityTakeOff - Reference: Standard
Pset_DistributionFlowElementCommon - sets with these values: 2

# IfcFlowFitting: M_Transition - Generic:Standard:922801:Standard:922801 : M_Transition - Generic:Standard:922801:328571, M_Transition - Generic:Standard:922801:Standard:922801 : M_Transition - Generic:Standard:922801:328571:Standard:922801:Standard:922801 : M_Transition - Generic:Standard:922801:328571 : M_Transition - Generic:Standard:922801:Standard:922801 : M_Transition - Generic:Standard:922801:328571:327380
In: Level 2
Type - Material: <Unnamed>
Type - Pset_DistributionFlowElementCommon - Reference: Standard
Type - Pset_ProductRequirements - Category: Pipe Fittings
Type - Pset_QuantityTakeOff - Reference: Standard
Pset_DistributionFlowElementCommon - sets with these values: 2

# IfcFlowFitting: M_Transition - Generic:Standard:922882:Standard:922882 : M_Transition - Generic:Standard:922882:328994, M_Transition - Generic:Standard:922882:Standard:922882 : M_Transition - Generic:Standard:922882:328994:Standard:922882:Standard:922882 : M_Transition - Generic:Standard:922882:328994 : M_Transition - Generic:Standard:922882:Standard:922882 : M_Transition - Generic:Standard:922882:328994:327602
In: Level 2
Type - Material: <Unnamed>
Type - Pset_DistributionFlowElementCommon - Reference: Standard
Type - Pset_ProductRequirements - Category: Pipe Fittings
Type - Pset_QuantityTakeOff - Reference: Standard
Pset_DistributionFlowElementCommon - sets with these values: 2

# IfcFlowFitting: M_Transition - Generic:Standard:923531:Standard:923531 : M_Transition - Generic:Standard:923531:328386, M_Transition - Generic:Standard:923531:Standard:923531 : M_Transition - Generic:Standard:923531:328386:Standard:923531:Standard:923531 : M_Transition - Generic:Standard:923531:328386 : M_Transition - Generic:Standard:923531:Standard:923531 : M_Transition - Generic:Standard:923531:328386:327269
In: Level 2
Type - Material: <Unnamed>
Type - Pset_DistributionFlowElementCommon - Reference: Standard
Type - Pset_ProductRequirements - Category: Pipe Fittings
Type - Pset_QuantityTakeOff - Reference: Standard
Pset_DistributionFlowElementCommon - sets with these values: 2

# IfcFlowFitting: M_Transition - Generic:Standard:923592:Standard:923592 : M_Transition - Generic:Standard:923592:327718, M_Transition - Generic:Standard:923592:Standard:923592 : M_Transition - Generic:Standard:923592:327718:Standard:923592:Standard:923592 : M_Transition - Generic:Standard:923592:327718 : M_Transition - Generic:Standard:923592:Standard:923592 : M_Transition - Generic:Standard:923592:327718:326833
In: Level 2
Type - Material: <Unnamed>
Type - Pset_DistributionFlowElementCommon - Reference: Standard
Type - Pset_ProductRequirements - Category: Pipe Fittings
Type - Pset_QuantityTakeOff - Reference: Standard
Pset_DistributionFlowElementCommon - sets with these values: 2

# IfcFlowFitting: M_Transition - Generic:Standard:924065:Standard:924065 : M_Transition - Generic:Standard:924065:327739, M_Transition - Generic:Standard:924065:Standard:924065 : M_Transition - Generic:Standard:924065:327739:Standard:924065:Standard:924065 : M_Transition - Generic:Standard:924065:327739 : M_Transition - Generic:Standard:924065:Standard:924065 : M_Transition - Generic:Standard:924065:327739:326846
In: Level 2
Type - Material: <Unnamed>
Type - Pset_DistributionFlowElementCommon - Reference: Standard
Type - Pset_ProductRequirements - Category: Pipe Fittings
Type - Pset_QuantityTakeOff - Reference: Standard
Pset_DistributionFlowElementCommon - sets with these values: 2

# IfcFlowFitting: M_Transition - Generic:Standard:932233:Standard:932233 : M_Transition - Generic:Standard:932233:325173, M_Transition - Generic:Standard:932233:Standard:932233 : M_Transition - Generic:Standard:932233:325173:Standard:932233:Standard:932233 : M_Transition - Generic:Standard:932233:325173 : M_Transition - Generic:Standard:932233:Standard:932233 : M_Transition - Generic:Standard:932233:325173:324021
In: Level 1
Type - Material: <Unnamed>
Type - Pset_DistributionFlowElementCommon - Reference: Standard
Type - Pset_ProductRequirements - Category: Pipe Fittings
Type - Pset_QuantityTakeOff - Reference: Standard
Pset_DistributionFlowElementCommon - sets with these values: 2

# IfcFlowFitting: M_Transition - Generic:Standard:932393:Standard:932393 : M_Transition - Generic:Standard:932393:325234, M_Transition - Generic:Standard:932393:Standard:932393 : M_Transition - Generic:Standard:932393:325234:Standard:932393:Standard:932393 : M_Transition - Generic:Standard:932393:325234 : M_Transition - Generic:Standard:932393:Standard:932393 : M_Transition - Generic:Standard:932393:325234:324034
In: Level 1
Type - Material: <Unnamed>
Type - Pset_DistributionFlowElementCommon - Reference: Standard
Type - Pset_ProductRequirements - Category: Pipe Fittings
Type - Pset_QuantityTakeOff - Reference: Standard
Pset_DistributionFlowElementCommon - sets with these values: 2

# IfcFlowFitting: M_Transition - Generic:Standard:932540:Standard:932540 : M_Transition - Generic:Standard:932540:324181, M_Transition - Generic:Standard:932540:Standard:932540 : M_Transition - Generic:Standard:932540:324181:Standard:932540:Standard:932540 : M_Transition - Generic:Standard:932540:324181 : M_Transition - Generic:Standard:932540:Standard:932540 : M_Transition - Generic:Standard:932540:324181:323494
In: Level 1
Type - Material: <Unnamed>
Type - Pset_DistributionFlowElementCommon - Reference: Standard
Type - Pset_ProductRequirements - Category: Pipe Fittings
Type - Pset_QuantityTakeOff - Reference: Standard
Pset_DistributionFlowElementCommon - sets with these values: 2

# IfcFlowFitting: M_Transition - Generic:Standard:932586:Standard:932586 : M_Transition - Generic:Standard:932586:324210, M_Transition - Generic:Standard:932586:Standard:932586 : M_Transition - Generic:Standard:932586:324210:Standard:932586:Standard:932586 : M_Transition - Generic:Standard:932586:324210 : M_Transition - Generic:Standard:932586:Standard:932586 : M_Transition - Generic:Standard:932586:324210:323507
In: Level 1
Type - Material: <Unnamed>
Type - Pset_DistributionFlowElementCommon - Reference: Standard
Type - Pset_ProductRequirements - Category: Pipe Fittings
Type - Pset_QuantityTakeOff - Reference: Standard
Pset_DistributionFlowElementCommon - sets with these values: 2

# IfcFlowFitting: M_Transition - Generic:Standard:933241:Standard:933241 : M_Transition - Generic:Standard:933241:323774, M_Transition - Generic:Standard:933241:Standard:933241 : M_Transition - Generic:Standard:933241:323774:Standard:933241:Standard:933241 : M_Transition - Generic:Standard:933241:323774 : M_Transition - Generic:Standard:933241:Standard:933241 : M_Transition - Generic:Standard:933241:323774:323348
In: Level 1
Type - Material: <Unnamed>
Type - Pset_DistributionFlowElementCommon - Reference: Standard
Type - Pset_ProductRequirements - Category: Pipe Fittings
Type - Pset_QuantityTakeOff - Reference: Standard
Pset_DistributionFlowElementCommon - sets with these values: 2

# IfcFlowFitting: M_Transition - Generic:Standard:934209:Standard:934209 : M_Transition - Generic:Standard:934209:322940, M_Transition - Generic:Standard:934209:Standard:934209 : M_Transition - Generic:Standard:934209:322940:Standard:934209:Standard:934209 : M_Transition - Generic:Standard:934209:322940 : M_Transition - Generic:Standard:934209:Standard:934209 : M_Transition - Generic:Standard:934209:322940:322664
In: Level 1
Type - Material: <Unnamed>
Type - Pset_DistributionFlowElementCommon - Reference: Standard
Type - Pset_ProductRequirements - Category: Pipe Fittings
Type - Pset_QuantityTakeOff - Reference: Standard
Pset_DistributionFlowElementCommon - sets with these values: 2

# IfcFlowFitting: M_Transition - Generic:Standard:934833:Standard:934833 : M_Transition - Generic:Standard:934833:322985, M_Transition - Generic:Standard:934833:Standard:934833 : M_Transition - Generic:Standard:934833:322985:Standard:934833:Standard:934833 : M_Transition - Generic:Standard:934833:322985 : M_Transition - Generic:Standard:934833:Standard:934833 : M_Transition - Generic:Standard:934833:322985:322682
In: Level 1
Type - Material: <Unnamed>
Type - Pset_DistributionFlowElementCommon - Reference: Standard
Type - Pset_ProductRequirements - Category: Pipe Fittings
Type - Pset_QuantityTakeOff - Reference: Standard
Pset_DistributionFlowElementCommon - sets with these values: 2

# IfcFlowFitting: M_Transition - Generic:Standard:940761:Standard:940761 : M_Transition - Generic:Standard:940761:324366, M_Transition - Generic:Standard:940761:Standard:940761 : M_Transition - Generic:Standard:940761:324366:Standard:940761:Standard:940761 : M_Transition - Generic:Standard:940761:324366 : M_Transition - Generic:Standard:940761:Standard:940761 : M_Transition - Generic:Standard:940761:324366:323534
In: Level 1
Type - Material: <Unnamed>
Type - Pset_DistributionFlowElementCommon - Reference: Standard
Type - Pset_ProductRequirements - Category: Pipe Fittings
Type - Pset_QuantityTakeOff - Reference: Standard
Pset_DistributionFlowElementCommon - sets with these values: 2

# IfcFlowSegment: Pipe Types:Standard:1031046:Standard:1031046 : Pipe Types:Standard:1031046:327387, Pipe Types:Standard:1031046:Standard:1031046 : Pipe Types:Standard:1031046:327387:Standard:1031046:Standard:1031046 : Pipe Types:Standard:1031046:327387 : Pipe Types:Standard:1031046:Standard:1031046 : Pipe Types:Standard:1031046:327387:326709
In: Level 2
Type - Material: <Unnamed>
Type - Pset_DistributionFlowElementCommon - Reference: Standard
Type - Pset_FlowSegmentDuctSegment - Length: 322.27 mm
Type - Pset_FlowSegmentPipeSegment - Length: 322.27 mm; InvertElevation: 3538.62 mm
Type - Pset_ProductRequirements - Category: Pipes
Type - Pset_QuantityTakeOff - Reference: Standard
Pset_DistributionFlowElementCommon - sets with these values: 2
Pset_FlowSegmentDuctSegment - sets with these values: 2

# IfcFlowSegment: Pipe Types:Standard:1031110:Standard:1031110 : Pipe Types:Standard:1031110:327399, Pipe Types:Standard:1031110:Standard:1031110 : Pipe Types:Standard:1031110:327399:Standard:1031110:Standard:1031110 : Pipe Types:Standard:1031110:327399 : Pipe Types:Standard:1031110:Standard:1031110 : Pipe Types:Standard:1031110:327399:326721
In: Level 2
Type - Material: <Unnamed>
Type - Pset_DistributionFlowElementCommon - Reference: Standard
Type - Pset_FlowSegmentDuctSegment - Length: 272.034 mm
Type - Pset_FlowSegmentPipeSegment - Length: 272.034 mm; InvertElevation: 3545.48 mm
Type - Pset_ProductRequirements - Category: Pipes
Type - Pset_QuantityTakeOff - Reference: Standard
Pset_DistributionFlowElementCommon - sets with these values: 2
Pset_FlowSegmentDuctSegment - sets with these values: 2

# IfcFlowSegment: Pipe Types:Standard:1031223:Standard:1031223 : Pipe Types:Standard:1031223:327411, Pipe Types:Standard:1031223:Standard:1031223 : Pipe Types:Standard:1031223:327411:Standard:1031223:Standard:1031223 : Pipe Types:Standard:1031223:327411 : Pipe Types:Standard:1031223:Standard:1031223 : Pipe Types:Standard:1031223:327411:326733
In: Level 2
Type - Material: <Unnamed>
Type - Pset_DistributionFlowElementCommon - Reference: Standard
Type - Pset_FlowSegmentDuctSegment - Length: 463.274 mm
Type - Pset_FlowSegmentPipeSegment - Length: 463.274 mm; InvertElevation: 3547.02 mm
Type - Pset_ProductRequirements - Category: Pipes
Type - Pset_QuantityTakeOff - Reference: Standard
Pset_DistributionFlowElementCommon - sets with these values: 2
Pset_FlowSegmentDuctSegment - sets with these values: 2

# IfcFlowSegment: Pipe Types:Standard:1031301:Standard:1031301 : Pipe Types:Standard:1031301:327423, Pipe Types:Standard:1031301:Standard:1031301 : Pipe Types:Standard:1031301:327423:Standard:1031301:Standard:1031301 : Pipe Types:Standard:1031301:327423 : Pipe Types:Standard:1031301:Standard:1031301 : Pipe Types:Standard:1031301:327423:326745
In: Level 2
Type - Material: <Unnamed>
Type - Pset_DistributionFlowElementCommon - Reference: Standard
Type - Pset_FlowSegmentDuctSegment - Length: 471.828 mm
Type - Pset_FlowSegmentPipeSegment - Length: 471.828 mm; InvertElevation: 3540.15 mm
Type - Pset_ProductRequirements - Category: Pipes
Type - Pset_QuantityTakeOff - Reference: Standard
Pset_DistributionFlowElementCommon - sets with these values: 2
Pset_FlowSegmentDuctSegment - sets with these values: 2

# IfcFlowSegment: Pipe Types:Standard:1033536:Standard:1033536 : Pipe Types:Standard:1033536:327435, Pipe Types:Standard:1033536:Standard:1033536 : Pipe Types:Standard:1033536:327435:Standard:1033536:Standard:1033536 : Pipe Types:Standard:1033536:327435 : Pipe Types:Standard:1033536:Standard:1033536 : Pipe Types:Standard:1033536:327435:326757
In: Level 2
Type - Material: <Unnamed>
Type - Pset_DistributionFlowElementCommon - Reference: Standard
Type - Pset_FlowSegmentDuctSegment - Length: 2335.69 mm
Type - Pset_FlowSegmentPipeSegment - Length: 2335.69 mm; InvertElevation: 4099.14 mm
Type - Pset_ProductRequirements - Category: Pipes
Type - Pset_QuantityTakeOff - Reference: Standard
Pset_DistributionFlowElementCommon - sets with these values: 2
Pset_FlowSegmentDuctSegment - sets with these values: 2

# IfcFlowSegment: Pipe Types:Standard:1033567:Standard:1033567 : Pipe Types:Standard:1033567:327447, Pipe Types:Standard:1033567:Standard:1033567 : Pipe Types:Standard:1033567:327447:Standard:1033567:Standard:1033567 : Pipe Types:Standard:1033567:327447 : Pipe Types:Standard:1033567:Standard:1033567 : Pipe Types:Standard:1033567:327447:326769
In: Level 2
Type - Material: <Unnamed>
Type - Pset_DistributionFlowElementCommon - Reference: Standard
Type - Pset_FlowSegmentDuctSegment - Length: 2323.3 mm
Type - Pset_FlowSegmentPipeSegment - Length: 2323.3 mm; InvertElevation: 4103.5 mm
Type - Pset_ProductRequirements - Category: Pipes
Type - Pset_QuantityTakeOff - Reference: Standard
Pset_DistributionFlowElementCommon - sets with these values: 2
Pset_FlowSegmentDuctSegment - sets with these values: 2

# IfcFlowSegment: Pipe Types:Standard:1033703:Standard:1033703 : Pipe Types:Standard:1033703:327467, Pipe Types:Standard:1033703:Standard:1033703 : Pipe Types:Standard:1033703:327467:Standard:1033703:Standard:1033703 : Pipe Types:Standard:1033703:327467 : Pipe Types:Standard:1033703:Standard:1033703 : Pipe Types:Standard:1033703:327467:326781
In: Level 2
Type - Material: <Unnamed>
Type - Pset_DistributionFlowElementCommon - Reference: Standard
Type - Pset_FlowSegmentDuctSegment - Length: 532.621 mm
Type - Pset_FlowSegmentPipeSegment - Length: 532.621 mm; InvertElevation: 3561.92 mm
Type - Pset_ProductRequirements - Category: Pipes
Type - Pset_QuantityTakeOff - Reference: Standard
Pset_DistributionFlowElementCommon - sets with these values: 2
Pset_FlowSegmentDuctSegment - sets with these values: 2

# IfcFlowSegment: Pipe Types:Standard:1033766:Standard:1033766 : Pipe Types:Standard:1033766:327495, Pipe Types:Standard:1033766:Standard:1033766 : Pipe Types:Standard:1033766:327495:Standard:1033766:Standard:1033766 : Pipe Types:Standard:1033766:327495 : Pipe Types:Standard:1033766:Standard:1033766 : Pipe Types:Standard:1033766:327495:326793
In: Level 2
Type - Material: <Unnamed>
Type - Pset_DistributionFlowElementCommon - Reference: Standard
Type - Pset_FlowSegmentDuctSegment - Length: 525.596 mm
Type - Pset_FlowSegmentPipeSegment - Length: 525.596 mm; InvertElevation: 3564.18 mm
Type - Pset_ProductRequirements - Category: Pipes
Type - Pset_QuantityTakeOff - Reference: Standard
Pset_DistributionFlowElementCommon - sets with these values: 2
Pset_FlowSegmentDuctSegment - sets with these values: 2

# IfcFlowSegment: Pipe Types:Standard:922588:Standard:922588 : Pipe Types:Standard:922588:325877, Pipe Types:Standard:922588:Standard:922588 : Pipe Types:Standard:922588:325877:Standard:922588:Standard:922588 : Pipe Types:Standard:922588:325877 : Pipe Types:Standard:922588:Standard:922588 : Pipe Types:Standard:922588:325877:325287
In: Level 2
Type - Material: <Unnamed>
Type - Pset_DistributionFlowElementCommon - Reference: Standard
Type - Pset_FlowSegmentDuctSegment - Length: 501.901 mm
Type - Pset_FlowSegmentPipeSegment - Length: 501.901 mm; InvertElevation: 6004.67 mm
Type - Pset_ProductRequirements - Category: Pipes
Type - Pset_QuantityTakeOff - Reference: Standard
Pset_DistributionFlowElementCommon - sets with these values: 2
Pset_FlowSegmentDuctSegment - sets with these values: 2

# IfcFlowSegment: Pipe Types:Standard:922636:Standard:922636 : Pipe Types:Standard:922636:325889, Pipe Types:Standard:922636:Standard:922636 : Pipe Types:Standard:922636:325889:Standard:922636:Standard:922636 : Pipe Types:Standard:922636:325889 : Pipe Types:Standard:922636:Standard:922636 : Pipe Types:Standard:922636:325889:325299
In: Level 2
Type - Material: <Unnamed>
Type - Pset_DistributionFlowElementCommon - Reference: Standard
Type - Pset_FlowSegmentDuctSegment - Length: 550.475 mm
Type - Pset_FlowSegmentPipeSegment - Length: 550.475 mm; InvertElevation: 5987.73 mm
Type - Pset_ProductRequirements - Category: Pipes
Type - Pset_QuantityTakeOff - Reference: Standard
Pset_DistributionFlowElementCommon - sets with these values: 2
Pset_FlowSegmentDuctSegment - sets with these values: 2

# IfcFlowSegment: Pipe Types:Standard:922674:Standard:922674 : Pipe Types:Standard:922674:325901, Pipe Types:Standard:922674:Standard:922674 : Pipe Types:Standard:922674:325901:Standard:922674:Standard:922674 : Pipe Types:Standard:922674:325901 : Pipe Types:Standard:922674:Standard:922674 : Pipe Types:Standard:922674:325901:325311
In: Level 2
Type - Material: <Unnamed>
Type - Pset_DistributionFlowElementCommon - Reference: Standard
Type - Pset_FlowSegmentDuctSegment - Length: 2185.18 mm
Type - Pset_FlowSegmentPipeSegment - Length: 2185.18 mm; InvertElevation: 6004.67 mm
Type - Pset_ProductRequirements - Category: Pipes
Type - Pset_QuantityTakeOff - Reference: Standard
Pset_DistributionFlowElementCommon - sets with these values: 2
Pset_FlowSegmentDuctSegment - sets with these values: 2

# IfcFlowSegment: Pipe Types:Standard:922688:Standard:922688 : Pipe Types:Standard:922688:325913, Pipe Types:Standard:922688:Standard:922688 : Pipe Types:Standard:922688:325913:Standard:922688:Standard:922688 : Pipe Types:Standard:922688:325913 : Pipe Types:Standard:922688:Standard:922688 : Pipe Types:Standard:922688:325913:325323
In: Level 2
Type - Material: <Unnamed>
Type - Pset_DistributionFlowElementCommon - Reference: Standard
Type - Pset_FlowSegmentDuctSegment - Length: 283.062 mm
Type - Pset_FlowSegmentPipeSegment - Length: 283.062 mm; InvertElevation: 6003.28 mm
Type - Pset_ProductRequirements - Category: Pipes
Type - Pset_QuantityTakeOff - Reference: Standard
Pset_DistributionFlowElementCommon - sets with these values: 2
Pset_FlowSegmentDuctSegment - sets with these values: 2

# IfcFlowSegment: Pipe Types:Standard:922743:Standard:922743 : Pipe Types:Standard:922743:325933, Pipe Types:Standard:922743:Standard:922743 : Pipe Types:Standard:922743:325933:Standard:922743:Standard:922743 : Pipe Types:Standard:922743:325933 : Pipe Types:Standard:922743:Standard:922743 : Pipe Types:Standard:922743:325933:325335
In: Level 2
Type - Material: <Unnamed>
Type - Pset_DistributionFlowElementCommon - Reference: Standard
Type - Pset_FlowSegmentDuctSegment - Length: 2189.99 mm
Type - Pset_FlowSegmentPipeSegment - Length: 2189.99 mm; InvertElevation: 5987.73 mm
Type - Pset_ProductRequirements - Category: Pipes
Type - Pset_QuantityTakeOff - Reference: Standard
Pset_DistributionFlowElementCommon - sets with these values: 2
Pset_FlowSegmentDuctSegment - sets with these values: 2

# IfcFlowSegment: Pipe Types:Standard:922757:Standard:922757 : Pipe Types:Standard:922757:325945, Pipe Types:Standard:922757:Standard:922757 : Pipe Types:Standard:922757:325945:Standard:922757:Standard:922757 : Pipe Types:Standard:922757:325945 : Pipe Types:Standard:922757:Standard:922757 : Pipe Types:Standard:922757:325945:325347
In: Level 2
Type - Material: <Unnamed>
Type - Pset_DistributionFlowElementCommon - Reference: Standard
Type - Pset_FlowSegmentDuctSegment - Length: 264.125 mm
Type - Pset_FlowSegmentPipeSegment - Length: 264.125 mm; InvertElevation: 5986.26 mm
Type - Pset_ProductRequirements - Category: Pipes
Type - Pset_QuantityTakeOff - Reference: Standard
Pset_DistributionFlowElementCommon - sets with these values: 2
Pset_FlowSegmentDuctSegment - sets with these values: 2

# IfcFlowSegment: Pipe Types:Standard:922793:Standard:922793 : Pipe Types:Standard:922793:325957, Pipe Types:Standard:922793:Standard:922793 : Pipe Types:Standard:922793:325957:Standard:922793:Standard:922793 : Pipe Types:Standard:922793:325957 : Pipe Types:Standard:922793:Standard:922793 : Pipe Types:Standard:922793:325957:325359
In: Level 2
Type - Material: <Unnamed>
Type - Pset_DistributionFlowElementCommon - Reference: Standard
Type - Pset_FlowSegmentDuctSegment - Length: 1121.74 mm
Type - Pset_FlowSegmentPipeSegment - Length: 1121.74 mm; InvertElevation: 6004.67 mm
Type - Pset_ProductRequirements - Category: Pipes
Type - Pset_QuantityTakeOff - Reference: Standard
Pset_DistributionFlowElementCommon - sets with these values: 2
Pset_FlowSegmentDuctSegment - sets with these values: 2

# IfcFlowSegment: Pipe Types:Standard:922803:Standard:922803 : Pipe Types:Standard:922803:325969, Pipe Types:Standard:922803:Standard:922803 : Pipe Types:Standard:922803:325969:Standard:922803:Standard:922803 : Pipe Types:Standard:922803:325969 : Pipe Types:Standard:922803:Standard:922803 : Pipe Types:Standard:922803:325969:325371
In: Level 2
Type - Material: <Unnamed>
Type - Pset_DistributionFlowElementCommon - Reference: Standard
Type - Pset_FlowSegmentDuctSegment - Length: 2138.62 mm
Type - Pset_FlowSegmentPipeSegment - Length: 2138.62 mm; InvertElevation: 6004.67 mm
Type - Pset_ProductRequirements - Category: Pipes
Type - Pset_QuantityTakeOff - Reference: Standard
Pset_DistributionFlowElementCommon - sets with these values: 2
Pset_FlowSegmentDuctSegment - sets with these values: 2

# IfcFlowSegment: Pipe Types:Standard:922816:Standard:922816 : Pipe Types:Standard:922816:325981, Pipe Types:Standard:922816:Standard:922816 : Pipe Types:Standard:922816:325981:Standard:922816:Standard:922816 : Pipe Types:Standard:922816:325981 : Pipe Types:Standard:922816:Standard:922816 : Pipe Types:Standard:922816:325981:325383
In: Level 2
Type - Material: <Unnamed>
Type - Pset_DistributionFlowElementCommon - Reference: Standard
Type - Pset_FlowSegmentDuctSegment - Length: 5436.42 mm
Type - Pset_FlowSegmentPipeSegment - Length: 5436.42 mm; InvertElevation: 6004.67 mm
Type - Pset_ProductRequirements - Category: Pipes
Type - Pset_QuantityTakeOff - Reference: Standard
Pset_DistributionFlowElementCommon - sets with these values: 2
Pset_FlowSegmentDuctSegment - sets with these values: 2

# IfcFlowSegment: Pipe Types:Standard:922828:Standard:922828 : Pipe Types:Standard:922828:325993, Pipe Types:Standard:922828:Standard:922828 : Pipe Types:Standard:922828:325993:Standard:922828:Standard:922828 : Pipe Types:Standard:922828:325993 : Pipe Types:Standard:922828:Standard:922828 : Pipe Types:Standard:922828:325993:325395
In: Level 2
Type - Material: <Unnamed>
Type - Pset_DistributionFlowElementCommon - Reference: Standard
Type - Pset_FlowSegmentDuctSegment - Length: 1048.08 mm
Type - Pset_FlowSegmentPipeSegment - Length: 1048.08 mm; InvertElevation: 5987.73 mm
Type - Pset_ProductRequirements - Category: Pipes
Type - Pset_QuantityTakeOff - Reference: Standard
Pset_DistributionFlowElementCommon - sets with these values: 2
Pset_FlowSegmentDuctSegment - sets with these values: 2

# IfcFlowSegment: Pipe Types:Standard:922840:Standard:922840 : Pipe Types:Standard:922840:326005, Pipe Types:Standard:922840:Standard:922840 : Pipe Types:Standard:922840:326005:Standard:922840:Standard:922840 : Pipe Types:Standard:922840:326005 : Pipe Types:Standard:922840:Standard:922840 : Pipe Types:Standard:922840:326005:325407
In: Level 2
Type - Material: <Unnamed>
Type - Pset_DistributionFlowElementCommon - Reference: Standard
Type - Pset_FlowSegmentDuctSegment - Length: 2143.43 mm
Type - Pset_FlowSegmentPipeSegment - Length: 2143.43 mm; InvertElevation: 5987.73 mm
Type - Pset_ProductRequirements - Category: Pipes
Type - Pset_QuantityTakeOff - Reference: Standard
Pset_DistributionFlowElementCommon - sets with these values: 2
Pset_FlowSegmentDuctSegment - sets with these values: 2

# IfcFlowSegment: Pipe Types:Standard:922861:Standard:922861 : Pipe Types:Standard:922861:326017, Pipe Types:Standard:922861:Standard:922861 : Pipe Types:Standard:922861:326017:Standard:922861:Standard:922861 : Pipe Types:Standard:922861:326017 : Pipe Types:Standard:922861:Standard:922861 : Pipe Types:Standard:922861:326017:325419
In: Level 2
Type - Material: <Unnamed>
Type - Pset_DistributionFlowElementCommon - Reference: Standard
Type - Pset_FlowSegmentDuctSegment - Length: 5323.71 mm
Type - Pset_FlowSegmentPipeSegment - Length: 5323.71 mm; InvertElevation: 5987.73 mm
Type - Pset_ProductRequirements - Category: Pipes
Type - Pset_QuantityTakeOff - Reference: Standard
Pset_DistributionFlowElementCommon - sets with these values: 2
Pset_FlowSegmentDuctSegment - sets with these values: 2

# IfcFlowSegment: Pipe Types:Standard:922872:Standard:922872 : Pipe Types:Standard:922872:326029, Pipe Types:Standard:922872:Standard:922872 : Pipe Types:Standard:922872:326029:Standard:922872:Standard:922872 : Pipe Types:Standard:922872:326029 : Pipe Types:Standard:922872:Standard:922872 : Pipe Types:Standard:922872:326029:325431
In: Level 2
Type - Material: <Unnamed>
Type - Pset_DistributionFlowElementCommon - Reference: Standard
Type - Pset_FlowSegmentDuctSegment - Length: 245.782 mm
Type - Pset_FlowSegmentPipeSegment - Length: 245.782 mm; InvertElevation: 6004.67 mm
Type - Pset_ProductRequirements - Category: Pipes
Type - Pset_QuantityTakeOff - Reference: Standard
Pset_DistributionFlowElementCommon - sets with these values: 2
Pset_FlowSegmentDuctSegment - sets with these values: 2

# IfcFlowSegment: Pipe Types:Standard:922884:Standard:922884 : Pipe Types:Standard:922884:326041, Pipe Types:Standard:922884:Standard:922884 : Pipe Types:Standard:922884:326041:Standard:922884:Standard:922884 : Pipe Types:Standard:922884:326041 : Pipe Types:Standard:922884:Standard:922884 : Pipe Types:Standard:922884:326041:325443
In: Level 2
Type - Material: <Unnamed>
Type - Pset_DistributionFlowElementCommon - Reference: Standard
Type - Pset_FlowSegmentDuctSegment - Length: 2717.68 mm
Type - Pset_FlowSegmentPipeSegment - Length: 2717.68 mm; InvertElevation: 6004.67 mm
Type - Pset_ProductRequirements - Category: Pipes
Type - Pset_QuantityTakeOff - Reference: Standard
Pset_DistributionFlowElementCommon - sets with these values: 2
Pset_FlowSegmentDuctSegment - sets with these values: 2

# IfcFlowSegment: Pipe Types:Standard:922892:Standard:922892 : Pipe Types:Standard:922892:326053, Pipe Types:Standard:922892:Standard:922892 : Pipe Types:Standard:922892:326053:Standard:922892:Standard:922892 : Pipe Types:Standard:922892:326053 : Pipe Types:Standard:922892:Standard:922892 : Pipe Types:Standard:922892:326053:325455
In: Level 2
Type - Material: <Unnamed>
Type - Pset_DistributionFlowElementCommon - Reference: Standard
Type - Pset_FlowSegmentDuctSegment - Length: 2348.21 mm
Type - Pset_FlowSegmentPipeSegment - Length: 2348.21 mm; InvertElevation: 6004.67 mm
Type - Pset_ProductRequirements - Category: Pipes
Type - Pset_QuantityTakeOff - Reference: Standard
Pset_DistributionFlowElementCommon - sets with these values: 2
Pset_FlowSegmentDuctSegment - sets with these values: 2

# IfcFlowSegment: Pipe Types:Standard:922926:Standard:922926 : Pipe Types:Standard:922926:326065, Pipe Types:Standard:922926:Standard:922926 : Pipe Types:Standard:922926:326065:Standard:922926:Standard:922926 : Pipe Types:Standard:922926:326065 : Pipe Types:Standard:922926:Standard:922926 : Pipe Types:Standard:922926:326065:325467
In: Level 2
Type - Material: <Unnamed>
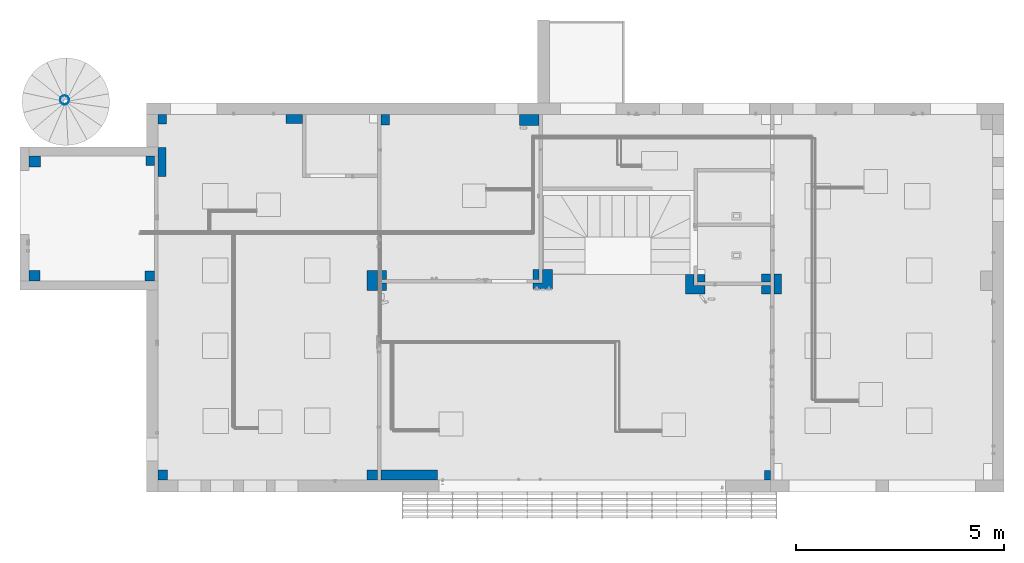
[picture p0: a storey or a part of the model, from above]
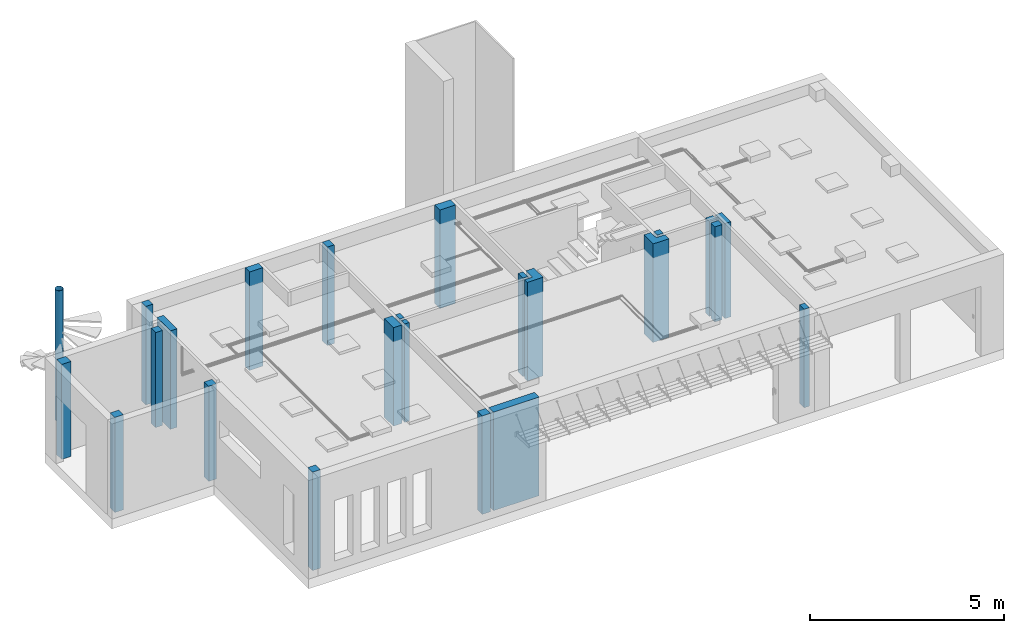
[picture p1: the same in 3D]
Properties of the parts of a building model (IFC2X3), part 4 of 5

# IfcFlowSegment: Pipe Types:Standard:922926:Standard:922926 : Pipe Types:Standard:922926:326065, Pipe Types:Standard:922926:Standard:922926 : Pipe Types:Standard:922926:326065:Standard:922926:Standard:922926 : Pipe Types:Standard:922926:326065 : Pipe Types:Standard:922926:Standard:922926 : Pipe Types:Standard:922926:326065:325467
Type - Pset_DistributionFlowElementCommon - Reference: Standard
Type - Pset_FlowSegmentDuctSegment - Length: 219.34 mm
Type - Pset_FlowSegmentPipeSegment - Length: 219.34 mm; InvertElevation: 5987.73 mm
Type - Pset_ProductRequirements - Category: Pipes
Type - Pset_QuantityTakeOff - Reference: Standard
Pset_DistributionFlowElementCommon - sets with these values: 2
Pset_FlowSegmentDuctSegment - sets with these values: 2

# IfcFlowSegment: Pipe Types:Standard:922971:Standard:922971 : Pipe Types:Standard:922971:326077, Pipe Types:Standard:922971:Standard:922971 : Pipe Types:Standard:922971:326077:Standard:922971:Standard:922971 : Pipe Types:Standard:922971:326077 : Pipe Types:Standard:922971:Standard:922971 : Pipe Types:Standard:922971:326077:325479
In: Level 2
Type - Material: <Unnamed>
Type - Pset_DistributionFlowElementCommon - Reference: Standard
Type - Pset_FlowSegmentDuctSegment - Length: 2622.83 mm
Type - Pset_FlowSegmentPipeSegment - Length: 2622.83 mm; InvertElevation: 5987.73 mm
Type - Pset_ProductRequirements - Category: Pipes
Type - Pset_QuantityTakeOff - Reference: Standard
Pset_DistributionFlowElementCommon - sets with these values: 2
Pset_FlowSegmentDuctSegment - sets with these values: 2

# IfcFlowSegment: Pipe Types:Standard:922981:Standard:922981 : Pipe Types:Standard:922981:326089, Pipe Types:Standard:922981:Standard:922981 : Pipe Types:Standard:922981:326089:Standard:922981:Standard:922981 : Pipe Types:Standard:922981:326089 : Pipe Types:Standard:922981:Standard:922981 : Pipe Types:Standard:922981:326089:325491
In: Level 2
Type - Material: <Unnamed>
Type - Pset_DistributionFlowElementCommon - Reference: Standard
Type - Pset_FlowSegmentDuctSegment - Length: 2358.04 mm
Type - Pset_FlowSegmentPipeSegment - Length: 2358.04 mm; InvertElevation: 5987.73 mm
Type - Pset_ProductRequirements - Category: Pipes
Type - Pset_QuantityTakeOff - Reference: Standard
Pset_DistributionFlowElementCommon - sets with these values: 2
Pset_FlowSegmentDuctSegment - sets with these values: 2

# IfcFlowSegment: Pipe Types:Standard:923016:Standard:923016 : Pipe Types:Standard:923016:326101, Pipe Types:Standard:923016:Standard:923016 : Pipe Types:Standard:923016:326101:Standard:923016:Standard:923016 : Pipe Types:Standard:923016:326101 : Pipe Types:Standard:923016:Standard:923016 : Pipe Types:Standard:923016:326101:325503
In: Level 2
Type - Material: <Unnamed>
Type - Pset_DistributionFlowElementCommon - Reference: Standard
Type - Pset_FlowSegmentDuctSegment - Length: 1608.08 mm
Type - Pset_FlowSegmentPipeSegment - Length: 1608.08 mm; InvertElevation: 5987.73 mm
Type - Pset_ProductRequirements - Category: Pipes
Type - Pset_QuantityTakeOff - Reference: Standard
Pset_DistributionFlowElementCommon - sets with these values: 2
Pset_FlowSegmentDuctSegment - sets with these values: 2

# IfcFlowSegment: Pipe Types:Standard:923086:Standard:923086 : Pipe Types:Standard:923086:326113, Pipe Types:Standard:923086:Standard:923086 : Pipe Types:Standard:923086:326113:Standard:923086:Standard:923086 : Pipe Types:Standard:923086:326113 : Pipe Types:Standard:923086:Standard:923086 : Pipe Types:Standard:923086:326113:325515
In: Level 2
Type - Material: <Unnamed>
Type - Pset_DistributionFlowElementCommon - Reference: Standard
Type - Pset_FlowSegmentDuctSegment - Length: 1008.41 mm
Type - Pset_FlowSegmentPipeSegment - Length: 1008.41 mm; InvertElevation: 5987.73 mm
Type - Pset_ProductRequirements - Category: Pipes
Type - Pset_QuantityTakeOff - Reference: Standard
Pset_DistributionFlowElementCommon - sets with these values: 2
Pset_FlowSegmentDuctSegment - sets with these values: 2

# IfcFlowSegment: Pipe Types:Standard:923097:Standard:923097 : Pipe Types:Standard:923097:326125, Pipe Types:Standard:923097:Standard:923097 : Pipe Types:Standard:923097:326125:Standard:923097:Standard:923097 : Pipe Types:Standard:923097:326125 : Pipe Types:Standard:923097:Standard:923097 : Pipe Types:Standard:923097:326125:325527
In: Level 2
Type - Material: <Unnamed>
Type - Pset_DistributionFlowElementCommon - Reference: Standard
Type - Pset_FlowSegmentDuctSegment - Length: 127.903 mm
Type - Pset_FlowSegmentPipeSegment - Length: 127.903 mm; InvertElevation: 5987.73 mm
Type - Pset_ProductRequirements - Category: Pipes
Type - Pset_QuantityTakeOff - Reference: Standard
Pset_DistributionFlowElementCommon - sets with these values: 2
Pset_FlowSegmentDuctSegment - sets with these values: 2

# IfcFlowSegment: Pipe Types:Standard:923263:Standard:923263 : Pipe Types:Standard:923263:326137, Pipe Types:Standard:923263:Standard:923263 : Pipe Types:Standard:923263:326137:Standard:923263:Standard:923263 : Pipe Types:Standard:923263:326137 : Pipe Types:Standard:923263:Standard:923263 : Pipe Types:Standard:923263:326137:325539
In: Level 2
Type - Material: <Unnamed>
Type - Pset_DistributionFlowElementCommon - Reference: Standard
Type - Pset_FlowSegmentDuctSegment - Length: 1931.73 mm
Type - Pset_FlowSegmentPipeSegment - Length: 1931.73 mm; InvertElevation: 6003.28 mm
Type - Pset_ProductRequirements - Category: Pipes
Type - Pset_QuantityTakeOff - Reference: Standard
Pset_DistributionFlowElementCommon - sets with these values: 2
Pset_FlowSegmentDuctSegment - sets with these values: 2

# IfcFlowSegment: Pipe Types:Standard:923278:Standard:923278 : Pipe Types:Standard:923278:326149, Pipe Types:Standard:923278:Standard:923278 : Pipe Types:Standard:923278:326149:Standard:923278:Standard:923278 : Pipe Types:Standard:923278:326149 : Pipe Types:Standard:923278:Standard:923278 : Pipe Types:Standard:923278:326149:325551
In: Level 2
Type - Material: <Unnamed>
Type - Pset_DistributionFlowElementCommon - Reference: Standard
Type - Pset_FlowSegmentDuctSegment - Length: 3618.31 mm
Type - Pset_FlowSegmentPipeSegment - Length: 3618.31 mm; InvertElevation: 6004.67 mm
Type - Pset_ProductRequirements - Category: Pipes
Type - Pset_QuantityTakeOff - Reference: Standard
Pset_DistributionFlowElementCommon - sets with these values: 2
Pset_FlowSegmentDuctSegment - sets with these values: 2

# IfcFlowSegment: Pipe Types:Standard:923347:Standard:923347 : Pipe Types:Standard:923347:326169, Pipe Types:Standard:923347:Standard:923347 : Pipe Types:Standard:923347:326169:Standard:923347:Standard:923347 : Pipe Types:Standard:923347:326169 : Pipe Types:Standard:923347:Standard:923347 : Pipe Types:Standard:923347:326169:325563
In: Level 2
Type - Material: <Unnamed>
Type - Pset_DistributionFlowElementCommon - Reference: Standard
Type - Pset_FlowSegmentDuctSegment - Length: 1959.95 mm
Type - Pset_FlowSegmentPipeSegment - Length: 1959.95 mm; InvertElevation: 5986.26 mm
Type - Pset_ProductRequirements - Category: Pipes
Type - Pset_QuantityTakeOff - Reference: Standard
Pset_DistributionFlowElementCommon - sets with these values: 2
Pset_FlowSegmentDuctSegment - sets with these values: 2

# IfcFlowSegment: Pipe Types:Standard:923521:Standard:923521 : Pipe Types:Standard:923521:326189, Pipe Types:Standard:923521:Standard:923521 : Pipe Types:Standard:923521:326189:Standard:923521:Standard:923521 : Pipe Types:Standard:923521:326189 : Pipe Types:Standard:923521:Standard:923521 : Pipe Types:Standard:923521:326189:325575
In: Level 2
Type - Material: <Unnamed>
Type - Pset_DistributionFlowElementCommon - Reference: Standard
Type - Pset_FlowSegmentDuctSegment - Length: 1626.74 mm
Type - Pset_FlowSegmentPipeSegment - Length: 1626.74 mm; InvertElevation: 6004.67 mm
Type - Pset_ProductRequirements - Category: Pipes
Type - Pset_QuantityTakeOff - Reference: Standard
Pset_DistributionFlowElementCommon - sets with these values: 2
Pset_FlowSegmentDuctSegment - sets with these values: 2

# IfcFlowSegment: Pipe Types:Standard:923533:Standard:923533 : Pipe Types:Standard:923533:326201, Pipe Types:Standard:923533:Standard:923533 : Pipe Types:Standard:923533:326201:Standard:923533:Standard:923533 : Pipe Types:Standard:923533:326201 : Pipe Types:Standard:923533:Standard:923533 : Pipe Types:Standard:923533:326201:325587
In: Level 2
Type - Material: <Unnamed>
Type - Pset_DistributionFlowElementCommon - Reference: Standard
Type - Pset_FlowSegmentDuctSegment - Length: 917.674 mm
Type - Pset_FlowSegmentPipeSegment - Length: 917.674 mm; InvertElevation: 6004.67 mm
Type - Pset_ProductRequirements - Category: Pipes
Type - Pset_QuantityTakeOff - Reference: Standard
Pset_DistributionFlowElementCommon - sets with these values: 2
Pset_FlowSegmentDuctSegment - sets with these values: 2

# IfcFlowSegment: Pipe Types:Standard:923544:Standard:923544 : Pipe Types:Standard:923544:326213, Pipe Types:Standard:923544:Standard:923544 : Pipe Types:Standard:923544:326213:Standard:923544:Standard:923544 : Pipe Types:Standard:923544:326213 : Pipe Types:Standard:923544:Standard:923544 : Pipe Types:Standard:923544:326213:325599
In: Level 2
Type - Material: <Unnamed>
Type - Pset_DistributionFlowElementCommon - Reference: Standard
Type - Pset_FlowSegmentDuctSegment - Length: 37.128 mm
Type - Pset_FlowSegmentPipeSegment - Length: 37.128 mm; InvertElevation: 6004.67 mm
Type - Pset_ProductRequirements - Category: Pipes
Type - Pset_QuantityTakeOff - Reference: Standard
Pset_DistributionFlowElementCommon - sets with these values: 2
Pset_FlowSegmentDuctSegment - sets with these values: 2

# IfcFlowSegment: Pipe Types:Standard:923576:Standard:923576 : Pipe Types:Standard:923576:326225, Pipe Types:Standard:923576:Standard:923576 : Pipe Types:Standard:923576:326225:Standard:923576:Standard:923576 : Pipe Types:Standard:923576:326225 : Pipe Types:Standard:923576:Standard:923576 : Pipe Types:Standard:923576:326225:325611
In: Level 2
Type - Material: <Unnamed>
Type - Pset_DistributionFlowElementCommon - Reference: Standard
Type - Pset_FlowSegmentDuctSegment - Length: 1185.71 mm
Type - Pset_FlowSegmentPipeSegment - Length: 1185.71 mm; InvertElevation: 6004.67 mm
Type - Pset_ProductRequirements - Category: Pipes
Type - Pset_QuantityTakeOff - Reference: Standard
Pset_DistributionFlowElementCommon - sets with these values: 2
Pset_FlowSegmentDuctSegment - sets with these values: 2

# IfcFlowSegment: Pipe Types:Standard:923610:Standard:923610 : Pipe Types:Standard:923610:326237, Pipe Types:Standard:923610:Standard:923610 : Pipe Types:Standard:923610:326237:Standard:923610:Standard:923610 : Pipe Types:Standard:923610:326237 : Pipe Types:Standard:923610:Standard:923610 : Pipe Types:Standard:923610:326237:325623
In: Level 2
Type - Material: <Unnamed>
Type - Pset_DistributionFlowElementCommon - Reference: Standard
Type - Pset_FlowSegmentDuctSegment - Length: 1100.96 mm
Type - Pset_FlowSegmentPipeSegment - Length: 1100.96 mm; InvertElevation: 5987.73 mm
Type - Pset_ProductRequirements - Category: Pipes
Type - Pset_QuantityTakeOff - Reference: Standard
Pset_DistributionFlowElementCommon - sets with these values: 2
Pset_FlowSegmentDuctSegment - sets with these values: 2

# IfcFlowSegment: Pipe Types:Standard:923913:Standard:923913 : Pipe Types:Standard:923913:326249, Pipe Types:Standard:923913:Standard:923913 : Pipe Types:Standard:923913:326249:Standard:923913:Standard:923913 : Pipe Types:Standard:923913:326249 : Pipe Types:Standard:923913:Standard:923913 : Pipe Types:Standard:923913:326249:325635
In: Level 2
Type - Material: <Unnamed>
Type - Pset_DistributionFlowElementCommon - Reference: Standard
Type - Pset_FlowSegmentDuctSegment - Length: 578.805 mm
Type - Pset_FlowSegmentPipeSegment - Length: 578.805 mm; InvertElevation: 5987.73 mm
Type - Pset_ProductRequirements - Category: Pipes
Type - Pset_QuantityTakeOff - Reference: Standard
Pset_DistributionFlowElementCommon - sets with these values: 2
Pset_FlowSegmentDuctSegment - sets with these values: 2

# IfcFlowSegment: Pipe Types:Standard:924006:Standard:924006 : Pipe Types:Standard:924006:326261, Pipe Types:Standard:924006:Standard:924006 : Pipe Types:Standard:924006:326261:Standard:924006:Standard:924006 : Pipe Types:Standard:924006:326261 : Pipe Types:Standard:924006:Standard:924006 : Pipe Types:Standard:924006:326261:325647
In: Level 2
Type - Material: <Unnamed>
Type - Pset_DistributionFlowElementCommon - Reference: Standard
Type - Pset_FlowSegmentDuctSegment - Length: 580.609 mm
Type - Pset_FlowSegmentPipeSegment - Length: 580.609 mm; InvertElevation: 6004.67 mm
Type - Pset_ProductRequirements - Category: Pipes
Type - Pset_QuantityTakeOff - Reference: Standard
Pset_DistributionFlowElementCommon - sets with these values: 2
Pset_FlowSegmentDuctSegment - sets with these values: 2

# IfcFlowSegment: Pipe Types:Standard:924049:Standard:924049 : Pipe Types:Standard:924049:326273, Pipe Types:Standard:924049:Standard:924049 : Pipe Types:Standard:924049:326273:Standard:924049:Standard:924049 : Pipe Types:Standard:924049:326273 : Pipe Types:Standard:924049:Standard:924049 : Pipe Types:Standard:924049:326273:325659
In: Level 2
Type - Material: <Unnamed>
Type - Pset_DistributionFlowElementCommon - Reference: Standard
Type - Pset_FlowSegmentDuctSegment - Length: 601.744 mm
Type - Pset_FlowSegmentPipeSegment - Length: 601.744 mm; InvertElevation: 6004.67 mm
Type - Pset_ProductRequirements - Category: Pipes
Type - Pset_QuantityTakeOff - Reference: Standard
Pset_DistributionFlowElementCommon - sets with these values: 2
Pset_FlowSegmentDuctSegment - sets with these values: 2

# IfcFlowSegment: Pipe Types:Standard:924103:Standard:924103 : Pipe Types:Standard:924103:326285, Pipe Types:Standard:924103:Standard:924103 : Pipe Types:Standard:924103:326285:Standard:924103:Standard:924103 : Pipe Types:Standard:924103:326285 : Pipe Types:Standard:924103:Standard:924103 : Pipe Types:Standard:924103:326285:325671
In: Level 2
Type - Material: <Unnamed>
Type - Pset_DistributionFlowElementCommon - Reference: Standard
Type - Pset_FlowSegmentDuctSegment - Length: 4075.04 mm
Type - Pset_FlowSegmentPipeSegment - Length: 4075.04 mm; InvertElevation: 6004.67 mm
Type - Pset_ProductRequirements - Category: Pipes
Type - Pset_QuantityTakeOff - Reference: Standard
Pset_DistributionFlowElementCommon - sets with these values: 2
Pset_FlowSegmentDuctSegment - sets with these values: 2

# IfcFlowSegment: Pipe Types:Standard:924135:Standard:924135 : Pipe Types:Standard:924135:326297, Pipe Types:Standard:924135:Standard:924135 : Pipe Types:Standard:924135:326297:Standard:924135:Standard:924135 : Pipe Types:Standard:924135:326297 : Pipe Types:Standard:924135:Standard:924135 : Pipe Types:Standard:924135:326297:325683
In: Level 2
Type - Material: <Unnamed>
Type - Pset_DistributionFlowElementCommon - Reference: Standard
Type - Pset_FlowSegmentDuctSegment - Length: 528.081 mm
Type - Pset_FlowSegmentPipeSegment - Length: 528.081 mm; InvertElevation: 5987.73 mm
Type - Pset_ProductRequirements - Category: Pipes
Type - Pset_QuantityTakeOff - Reference: Standard
Pset_DistributionFlowElementCommon - sets with these values: 2
Pset_FlowSegmentDuctSegment - sets with these values: 2

# IfcFlowSegment: Pipe Types:Standard:924147:Standard:924147 : Pipe Types:Standard:924147:326309, Pipe Types:Standard:924147:Standard:924147 : Pipe Types:Standard:924147:326309:Standard:924147:Standard:924147 : Pipe Types:Standard:924147:326309 : Pipe Types:Standard:924147:Standard:924147 : Pipe Types:Standard:924147:326309:325695
In: Level 2
Type - Material: <Unnamed>
Type - Pset_DistributionFlowElementCommon - Reference: Standard
Type - Pset_FlowSegmentDuctSegment - Length: 4101.98 mm
Type - Pset_FlowSegmentPipeSegment - Length: 4101.98 mm; InvertElevation: 5987.73 mm
Type - Pset_ProductRequirements - Category: Pipes
Type - Pset_QuantityTakeOff - Reference: Standard
Pset_DistributionFlowElementCommon - sets with these values: 2
Pset_FlowSegmentDuctSegment - sets with these values: 2

# IfcFlowSegment: Pipe Types:Standard:929839:Standard:929839 : Pipe Types:Standard:929839:326321, Pipe Types:Standard:929839:Standard:929839 : Pipe Types:Standard:929839:326321:Standard:929839:Standard:929839 : Pipe Types:Standard:929839:326321 : Pipe Types:Standard:929839:Standard:929839 : Pipe Types:Standard:929839:326321:325707
In: Level 2
Type - Material: <Unnamed>
Type - Pset_DistributionFlowElementCommon - Reference: Standard
Type - Pset_FlowSegmentDuctSegment - Length: 3430.24 mm
Type - Pset_FlowSegmentPipeSegment - Length: 3430.24 mm; InvertElevation: 6001.89 mm
Type - Pset_ProductRequirements - Category: Pipes
Type - Pset_QuantityTakeOff - Reference: Standard
Pset_DistributionFlowElementCommon - sets with these values: 2
Pset_FlowSegmentDuctSegment - sets with these values: 2

# IfcFlowSegment: Pipe Types:Standard:929868:Standard:929868 : Pipe Types:Standard:929868:326333, Pipe Types:Standard:929868:Standard:929868 : Pipe Types:Standard:929868:326333:Standard:929868:Standard:929868 : Pipe Types:Standard:929868:326333 : Pipe Types:Standard:929868:Standard:929868 : Pipe Types:Standard:929868:326333:325719
In: Level 2
Type - Material: <Unnamed>
Type - Pset_DistributionFlowElementCommon - Reference: Standard
Type - Pset_FlowSegmentDuctSegment - Length: 1725.78 mm
Type - Pset_FlowSegmentPipeSegment - Length: 1725.78 mm; InvertElevation: 6001.89 mm
Type - Pset_ProductRequirements - Category: Pipes
Type - Pset_QuantityTakeOff - Reference: Standard
Pset_DistributionFlowElementCommon - sets with these values: 2
Pset_FlowSegmentDuctSegment - sets with these values: 2

# IfcFlowSegment: Pipe Types:Standard:929880:Standard:929880 : Pipe Types:Standard:929880:326345, Pipe Types:Standard:929880:Standard:929880 : Pipe Types:Standard:929880:326345:Standard:929880:Standard:929880 : Pipe Types:Standard:929880:326345 : Pipe Types:Standard:929880:Standard:929880 : Pipe Types:Standard:929880:326345:325731
In: Level 2
Type - Material: <Unnamed>
Type - Pset_DistributionFlowElementCommon - Reference: Standard
Type - Pset_FlowSegmentDuctSegment - Length: 563.148 mm
Type - Pset_FlowSegmentPipeSegment - Length: 563.148 mm; InvertElevation: 6001.89 mm
Type - Pset_ProductRequirements - Category: Pipes
Type - Pset_QuantityTakeOff - Reference: Standard
Pset_DistributionFlowElementCommon - sets with these values: 2
Pset_FlowSegmentDuctSegment - sets with these values: 2

# IfcFlowSegment: Pipe Types:Standard:930016:Standard:930016 : Pipe Types:Standard:930016:326357, Pipe Types:Standard:930016:Standard:930016 : Pipe Types:Standard:930016:326357:Standard:930016:Standard:930016 : Pipe Types:Standard:930016:326357 : Pipe Types:Standard:930016:Standard:930016 : Pipe Types:Standard:930016:326357:325743
In: Level 2
Type - Material: <Unnamed>
Type - Pset_DistributionFlowElementCommon - Reference: Standard
Type - Pset_FlowSegmentDuctSegment - Length: 3494.37 mm
Type - Pset_FlowSegmentPipeSegment - Length: 3494.37 mm; InvertElevation: 5986.26 mm
Type - Pset_ProductRequirements - Category: Pipes
Type - Pset_QuantityTakeOff - Reference: Standard
Pset_DistributionFlowElementCommon - sets with these values: 2
Pset_FlowSegmentDuctSegment - sets with these values: 2

# IfcFlowSegment: Pipe Types:Standard:930140:Standard:930140 : Pipe Types:Standard:930140:326369, Pipe Types:Standard:930140:Standard:930140 : Pipe Types:Standard:930140:326369:Standard:930140:Standard:930140 : Pipe Types:Standard:930140:326369 : Pipe Types:Standard:930140:Standard:930140 : Pipe Types:Standard:930140:326369:325755
In: Level 2
Type - Material: <Unnamed>
Type - Pset_DistributionFlowElementCommon - Reference: Standard
Type - Pset_FlowSegmentDuctSegment - Length: 3474.85 mm
Type - Pset_FlowSegmentPipeSegment - Length: 3474.85 mm; InvertElevation: 5986.26 mm
Type - Pset_ProductRequirements - Category: Pipes
Type - Pset_QuantityTakeOff - Reference: Standard
Pset_DistributionFlowElementCommon - sets with these values: 2
Pset_FlowSegmentDuctSegment - sets with these values: 2

# IfcFlowSegment: Pipe Types:Standard:930211:Standard:930211 : Pipe Types:Standard:930211:326381, Pipe Types:Standard:930211:Standard:930211 : Pipe Types:Standard:930211:326381:Standard:930211:Standard:930211 : Pipe Types:Standard:930211:326381 : Pipe Types:Standard:930211:Standard:930211 : Pipe Types:Standard:930211:326381:325767
In: Level 2
Type - Material: <Unnamed>
Type - Pset_DistributionFlowElementCommon - Reference: Standard
Type - Pset_FlowSegmentDuctSegment - Length: 561.581 mm
Type - Pset_FlowSegmentPipeSegment - Length: 561.581 mm; InvertElevation: 5986.26 mm
Type - Pset_ProductRequirements - Category: Pipes
Type - Pset_QuantityTakeOff - Reference: Standard
Pset_DistributionFlowElementCommon - sets with these values: 2
Pset_FlowSegmentDuctSegment - sets with these values: 2

# IfcFlowSegment: Pipe Types:Standard:930244:Standard:930244 : Pipe Types:Standard:930244:326393, Pipe Types:Standard:930244:Standard:930244 : Pipe Types:Standard:930244:326393:Standard:930244:Standard:930244 : Pipe Types:Standard:930244:326393 : Pipe Types:Standard:930244:Standard:930244 : Pipe Types:Standard:930244:326393:325779
In: Level 2
Type - Material: <Unnamed>
Type - Pset_DistributionFlowElementCommon - Reference: Standard
Type - Pset_FlowSegmentDuctSegment - Length: 1881.39 mm
Type - Pset_FlowSegmentPipeSegment - Length: 1881.39 mm; InvertElevation: 5986.26 mm
Type - Pset_ProductRequirements - Category: Pipes
Type - Pset_QuantityTakeOff - Reference: Standard
Pset_DistributionFlowElementCommon - sets with these values: 2
Pset_FlowSegmentDuctSegment - sets with these values: 2

# IfcFlowSegment: Pipe Types:Standard:930412:Standard:930412 : Pipe Types:Standard:930412:326405, Pipe Types:Standard:930412:Standard:930412 : Pipe Types:Standard:930412:326405:Standard:930412:Standard:930412 : Pipe Types:Standard:930412:326405 : Pipe Types:Standard:930412:Standard:930412 : Pipe Types:Standard:930412:326405:325791
In: Level 2
Type - Material: <Unnamed>
Type - Pset_DistributionFlowElementCommon - Reference: Standard
Type - Pset_FlowSegmentDuctSegment - Length: 1857.36 mm
Type - Pset_FlowSegmentPipeSegment - Length: 1857.36 mm; InvertElevation: 4119.94 mm
Type - Pset_ProductRequirements - Category: Pipes
Type - Pset_QuantityTakeOff - Reference: Standard
Pset_DistributionFlowElementCommon - sets with these values: 2
Pset_FlowSegmentDuctSegment - sets with these values: 2

# IfcFlowSegment: Pipe Types:Standard:930478:Standard:930478 : Pipe Types:Standard:930478:326417, Pipe Types:Standard:930478:Standard:930478 : Pipe Types:Standard:930478:326417:Standard:930478:Standard:930478 : Pipe Types:Standard:930478:326417 : Pipe Types:Standard:930478:Standard:930478 : Pipe Types:Standard:930478:326417:325803
In: Level 2
Type - Material: <Unnamed>
Type - Pset_DistributionFlowElementCommon - Reference: Standard
Type - Pset_FlowSegmentDuctSegment - Length: 1867.83 mm
Type - Pset_FlowSegmentPipeSegment - Length: 1867.83 mm; InvertElevation: 4124.7 mm
Type - Pset_ProductRequirements - Category: Pipes
Type - Pset_QuantityTakeOff - Reference: Standard
Pset_DistributionFlowElementCommon - sets with these values: 2
Pset_FlowSegmentDuctSegment - sets with these values: 2

# IfcFlowSegment: Pipe Types:Standard:932219:Standard:932219 : Pipe Types:Standard:932219:320665, Pipe Types:Standard:932219:Standard:932219 : Pipe Types:Standard:932219:320665:Standard:932219:Standard:932219 : Pipe Types:Standard:932219:320665 : Pipe Types:Standard:932219:Standard:932219 : Pipe Types:Standard:932219:320665:320657
In: Level 1
Type - Material: <Unnamed>
Type - Pset_DistributionFlowElementCommon - Reference: Standard
Type - Pset_FlowSegmentDuctSegment - Length: 1101.74 mm
Type - Pset_FlowSegmentPipeSegment - Length: 1101.74 mm; InvertElevation: 2704.67 mm
Type - Pset_ProductRequirements - Category: Pipes
Type - Pset_QuantityTakeOff - Reference: Standard
Pset_DistributionFlowElementCommon - sets with these values: 2
Pset_FlowSegmentDuctSegment - sets with these values: 2

# IfcFlowSegment: Pipe Types:Standard:932235:Standard:932235 : Pipe Types:Standard:932235:320697, Pipe Types:Standard:932235:Standard:932235 : Pipe Types:Standard:932235:320697:Standard:932235:Standard:932235 : Pipe Types:Standard:932235:320697 : Pipe Types:Standard:932235:Standard:932235 : Pipe Types:Standard:932235:320697:320683
In: Level 1
Type - Material: <Unnamed>
Type - Pset_DistributionFlowElementCommon - Reference: Standard
Type - Pset_FlowSegmentDuctSegment - Length: 1188.41 mm
Type - Pset_FlowSegmentPipeSegment - Length: 1188.41 mm; InvertElevation: 2704.67 mm
Type - Pset_ProductRequirements - Category: Pipes
Type - Pset_QuantityTakeOff - Reference: Standard
Pset_DistributionFlowElementCommon - sets with these values: 2
Pset_FlowSegmentDuctSegment - sets with these values: 2

# IfcFlowSegment: Pipe Types:Standard:932265:Standard:932265 : Pipe Types:Standard:932265:320709, Pipe Types:Standard:932265:Standard:932265 : Pipe Types:Standard:932265:320709:Standard:932265:Standard:932265 : Pipe Types:Standard:932265:320709 : Pipe Types:Standard:932265:Standard:932265 : Pipe Types:Standard:932265:320709:320695
In: Level 1
Type - Material: <Unnamed>
Type - Pset_DistributionFlowElementCommon - Reference: Standard
Type - Pset_FlowSegmentDuctSegment - Length: 1028.08 mm
Type - Pset_FlowSegmentPipeSegment - Length: 1028.08 mm; InvertElevation: 2687.73 mm
Type - Pset_ProductRequirements - Category: Pipes
Type - Pset_QuantityTakeOff - Reference: Standard
Pset_DistributionFlowElementCommon - sets with these values: 2
Pset_FlowSegmentDuctSegment - sets with these values: 2

# IfcFlowSegment: Pipe Types:Standard:932299:Standard:932299 : Pipe Types:Standard:932299:320721, Pipe Types:Standard:932299:Standard:932299 : Pipe Types:Standard:932299:320721:Standard:932299:Standard:932299 : Pipe Types:Standard:932299:320721 : Pipe Types:Standard:932299:Standard:932299 : Pipe Types:Standard:932299:320721:320707
In: Level 1
Type - Material: <Unnamed>
Type - Pset_DistributionFlowElementCommon - Reference: Standard
Type - Pset_FlowSegmentDuctSegment - Length: 1183.13 mm
Type - Pset_FlowSegmentPipeSegment - Length: 1183.13 mm; InvertElevation: 2686.94 mm
Type - Pset_ProductRequirements - Category: Pipes
Type - Pset_QuantityTakeOff - Reference: Standard
Pset_DistributionFlowElementCommon - sets with these values: 2
Pset_FlowSegmentDuctSegment - sets with these values: 2

# IfcFlowSegment: Pipe Types:Standard:932337:Standard:932337 : Pipe Types:Standard:932337:320733, Pipe Types:Standard:932337:Standard:932337 : Pipe Types:Standard:932337:320733:Standard:932337:Standard:932337 : Pipe Types:Standard:932337:320733 : Pipe Types:Standard:932337:Standard:932337 : Pipe Types:Standard:932337:320733:320719
In: Level 1
Type - Material: <Unnamed>
Type - Pset_DistributionFlowElementCommon - Reference: Standard
Type - Pset_FlowSegmentDuctSegment - Length: 1143.58 mm
Type - Pset_FlowSegmentPipeSegment - Length: 1143.58 mm; InvertElevation: 2687.73 mm
Type - Pset_ProductRequirements - Category: Pipes
Type - Pset_QuantityTakeOff - Reference: Standard
Pset_DistributionFlowElementCommon - sets with these values: 2
Pset_FlowSegmentDuctSegment - sets with these values: 2

# IfcFlowSegment: Pipe Types:Standard:932354:Standard:932354 : Pipe Types:Standard:932354:320745, Pipe Types:Standard:932354:Standard:932354 : Pipe Types:Standard:932354:320745:Standard:932354:Standard:932354 : Pipe Types:Standard:932354:320745 : Pipe Types:Standard:932354:Standard:932354 : Pipe Types:Standard:932354:320745:320731
In: Level 1
Type - Material: <Unnamed>
Type - Pset_DistributionFlowElementCommon - Reference: Standard
Type - Pset_FlowSegmentDuctSegment - Length: 5105.02 mm
Type - Pset_FlowSegmentPipeSegment - Length: 5105.02 mm; InvertElevation: 2687.73 mm
Type - Pset_ProductRequirements - Category: Pipes
Type - Pset_QuantityTakeOff - Reference: Standard
Pset_DistributionFlowElementCommon - sets with these values: 2
Pset_FlowSegmentDuctSegment - sets with these values: 2

# IfcFlowSegment: Pipe Types:Standard:932373:Standard:932373 : Pipe Types:Standard:932373:320757, Pipe Types:Standard:932373:Standard:932373 : Pipe Types:Standard:932373:320757:Standard:932373:Standard:932373 : Pipe Types:Standard:932373:320757 : Pipe Types:Standard:932373:Standard:932373 : Pipe Types:Standard:932373:320757:320743
In: Level 1
Type - Material: <Unnamed>
Type - Pset_DistributionFlowElementCommon - Reference: Standard
Type - Pset_FlowSegmentDuctSegment - Length: 1217.25 mm
Type - Pset_FlowSegmentPipeSegment - Length: 1217.25 mm; InvertElevation: 2704.67 mm
Type - Pset_ProductRequirements - Category: Pipes
Type - Pset_QuantityTakeOff - Reference: Standard
Pset_DistributionFlowElementCommon - sets with these values: 2
Pset_FlowSegmentDuctSegment - sets with these values: 2

# IfcFlowSegment: Pipe Types:Standard:932390:Standard:932390 : Pipe Types:Standard:932390:320769, Pipe Types:Standard:932390:Standard:932390 : Pipe Types:Standard:932390:320769:Standard:932390:Standard:932390 : Pipe Types:Standard:932390:320769 : Pipe Types:Standard:932390:Standard:932390 : Pipe Types:Standard:932390:320769:320755
In: Level 1
Type - Material: <Unnamed>
Type - Pset_DistributionFlowElementCommon - Reference: Standard
Type - Pset_FlowSegmentDuctSegment - Length: 5095.49 mm
Type - Pset_FlowSegmentPipeSegment - Length: 5095.49 mm; InvertElevation: 2704.67 mm
Type - Pset_ProductRequirements - Category: Pipes
Type - Pset_QuantityTakeOff - Reference: Standard
Pset_DistributionFlowElementCommon - sets with these values: 2
Pset_FlowSegmentDuctSegment - sets with these values: 2

# IfcFlowSegment: Pipe Types:Standard:932428:Standard:932428 : Pipe Types:Standard:932428:320781, Pipe Types:Standard:932428:Standard:932428 : Pipe Types:Standard:932428:320781:Standard:932428:Standard:932428 : Pipe Types:Standard:932428:320781 : Pipe Types:Standard:932428:Standard:932428 : Pipe Types:Standard:932428:320781:320767
In: Level 1
Type - Material: <Unnamed>
Type - Pset_DistributionFlowElementCommon - Reference: Standard
Type - Pset_FlowSegmentDuctSegment - Length: 4649.37 mm
Type - Pset_FlowSegmentPipeSegment - Length: 4649.37 mm; InvertElevation: 2686.94 mm
Type - Pset_ProductRequirements - Category: Pipes
Type - Pset_QuantityTakeOff - Reference: Standard
Pset_DistributionFlowElementCommon - sets with these values: 2
Pset_FlowSegmentDuctSegment - sets with these values: 2

# IfcFlowSegment: Pipe Types:Standard:932466:Standard:932466 : Pipe Types:Standard:932466:320793, Pipe Types:Standard:932466:Standard:932466 : Pipe Types:Standard:932466:320793:Standard:932466:Standard:932466 : Pipe Types:Standard:932466:320793 : Pipe Types:Standard:932466:Standard:932466 : Pipe Types:Standard:932466:320793:320779
In: Level 1
Type - Material: <Unnamed>
Type - Pset_DistributionFlowElementCommon - Reference: Standard
Type - Pset_FlowSegmentDuctSegment - Length: 2017.25 mm
Type - Pset_FlowSegmentPipeSegment - Length: 2017.25 mm; InvertElevation: 2704.67 mm
Type - Pset_ProductRequirements - Category: Pipes
Type - Pset_QuantityTakeOff - Reference: Standard
Pset_DistributionFlowElementCommon - sets with these values: 2
Pset_FlowSegmentDuctSegment - sets with these values: 2

# IfcFlowSegment: Pipe Types:Standard:932532:Standard:932532 : Pipe Types:Standard:932532:320805, Pipe Types:Standard:932532:Standard:932532 : Pipe Types:Standard:932532:320805:Standard:932532:Standard:932532 : Pipe Types:Standard:932532:320805 : Pipe Types:Standard:932532:Standard:932532 : Pipe Types:Standard:932532:320805:320791
In: Level 1
Type - Material: <Unnamed>
Type - Pset_DistributionFlowElementCommon - Reference: Standard
Type - Pset_FlowSegmentDuctSegment - Length: 1001.74 mm
Type - Pset_FlowSegmentPipeSegment - Length: 1001.74 mm; InvertElevation: 2704.67 mm
Type - Pset_ProductRequirements - Category: Pipes
Type - Pset_QuantityTakeOff - Reference: Standard
Pset_DistributionFlowElementCommon - sets with these values: 2
Pset_FlowSegmentDuctSegment - sets with these values: 2

# IfcFlowSegment: Pipe Types:Standard:932542:Standard:932542 : Pipe Types:Standard:932542:320817, Pipe Types:Standard:932542:Standard:932542 : Pipe Types:Standard:932542:320817:Standard:932542:Standard:932542 : Pipe Types:Standard:932542:320817 : Pipe Types:Standard:932542:Standard:932542 : Pipe Types:Standard:932542:320817:320803
In: Level 1
Type - Material: <Unnamed>
Type - Pset_DistributionFlowElementCommon - Reference: Standard
Type - Pset_FlowSegmentDuctSegment - Length: 2105.18 mm
Type - Pset_FlowSegmentPipeSegment - Length: 2105.18 mm; InvertElevation: 2704.67 mm
Type - Pset_ProductRequirements - Category: Pipes
Type - Pset_QuantityTakeOff - Reference: Standard
Pset_DistributionFlowElementCommon - sets with these values: 2
Pset_FlowSegmentDuctSegment - sets with these values: 2

# IfcFlowSegment: Pipe Types:Standard:932552:Standard:932552 : Pipe Types:Standard:932552:320829, Pipe Types:Standard:932552:Standard:932552 : Pipe Types:Standard:932552:320829:Standard:932552:Standard:932552 : Pipe Types:Standard:932552:320829 : Pipe Types:Standard:932552:Standard:932552 : Pipe Types:Standard:932552:320829:320815
In: Level 1
Type - Material: <Unnamed>
Type - Pset_DistributionFlowElementCommon - Reference: Standard
Type - Pset_FlowSegmentDuctSegment - Length: 254.762 mm
Type - Pset_FlowSegmentPipeSegment - Length: 254.762 mm; InvertElevation: 2704.67 mm
Type - Pset_ProductRequirements - Category: Pipes
Type - Pset_QuantityTakeOff - Reference: Standard
Pset_DistributionFlowElementCommon - sets with these values: 2
Pset_FlowSegmentDuctSegment - sets with these values: 2

# IfcFlowSegment: Pipe Types:Standard:932578:Standard:932578 : Pipe Types:Standard:932578:320841, Pipe Types:Standard:932578:Standard:932578 : Pipe Types:Standard:932578:320841:Standard:932578:Standard:932578 : Pipe Types:Standard:932578:320841 : Pipe Types:Standard:932578:Standard:932578 : Pipe Types:Standard:932578:320841:320827
In: Level 1
Type - Material: <Unnamed>
Type - Pset_DistributionFlowElementCommon - Reference: Standard
Type - Pset_FlowSegmentDuctSegment - Length: 1146.74 mm
Type - Pset_FlowSegmentPipeSegment - Length: 1146.74 mm; InvertElevation: 2704.67 mm
Type - Pset_ProductRequirements - Category: Pipes
Type - Pset_QuantityTakeOff - Reference: Standard
Pset_DistributionFlowElementCommon - sets with these values: 2
Pset_FlowSegmentDuctSegment - sets with these values: 2

# IfcFlowSegment: Pipe Types:Standard:932588:Standard:932588 : Pipe Types:Standard:932588:320853, Pipe Types:Standard:932588:Standard:932588 : Pipe Types:Standard:932588:320853:Standard:932588:Standard:932588 : Pipe Types:Standard:932588:320853 : Pipe Types:Standard:932588:Standard:932588 : Pipe Types:Standard:932588:320853:320839
In: Level 1
Type - Material: <Unnamed>
Type - Pset_DistributionFlowElementCommon - Reference: Standard
Type - Pset_FlowSegmentDuctSegment - Length: 2084.4 mm
Type - Pset_FlowSegmentPipeSegment - Length: 2084.4 mm; InvertElevation: 2704.67 mm
Type - Pset_ProductRequirements - Category: Pipes
Type - Pset_QuantityTakeOff - Reference: Standard
Pset_DistributionFlowElementCommon - sets with these values: 2
Pset_FlowSegmentDuctSegment - sets with these values: 2

# IfcFlowSegment: Pipe Types:Standard:932604:Standard:932604 : Pipe Types:Standard:932604:320865, Pipe Types:Standard:932604:Standard:932604 : Pipe Types:Standard:932604:320865:Standard:932604:Standard:932604 : Pipe Types:Standard:932604:320865 : Pipe Types:Standard:932604:Standard:932604 : Pipe Types:Standard:932604:320865:320851
In: Level 1
Type - Material: <Unnamed>
Type - Pset_DistributionFlowElementCommon - Reference: Standard
Type - Pset_FlowSegmentDuctSegment - Length: 5475.39 mm
Type - Pset_FlowSegmentPipeSegment - Length: 5475.39 mm; InvertElevation: 2704.67 mm
Type - Pset_ProductRequirements - Category: Pipes
Type - Pset_QuantityTakeOff - Reference: Standard
Pset_DistributionFlowElementCommon - sets with these values: 2
Pset_FlowSegmentDuctSegment - sets with these values: 2

# IfcFlowSegment: Pipe Types:Standard:932638:Standard:932638 : Pipe Types:Standard:932638:320877, Pipe Types:Standard:932638:Standard:932638 : Pipe Types:Standard:932638:320877:Standard:932638:Standard:932638 : Pipe Types:Standard:932638:320877 : Pipe Types:Standard:932638:Standard:932638 : Pipe Types:Standard:932638:320877:320863
In: Level 1
Type - Material: <Unnamed>
Type - Pset_DistributionFlowElementCommon - Reference: Standard
Type - Pset_FlowSegmentDuctSegment - Length: 1105.7 mm
Type - Pset_FlowSegmentPipeSegment - Length: 1105.7 mm; InvertElevation: 2686.94 mm
Type - Pset_ProductRequirements - Category: Pipes
Type - Pset_QuantityTakeOff - Reference: Standard
Pset_DistributionFlowElementCommon - sets with these values: 2
Pset_FlowSegmentDuctSegment - sets with these values: 2

# IfcFlowSegment: Pipe Types:Standard:932649:Standard:932649 : Pipe Types:Standard:932649:320889, Pipe Types:Standard:932649:Standard:932649 : Pipe Types:Standard:932649:320889:Standard:932649:Standard:932649 : Pipe Types:Standard:932649:320889 : Pipe Types:Standard:932649:Standard:932649 : Pipe Types:Standard:932649:320889:320875
In: Level 1
Type - Material: <Unnamed>
Type - Pset_DistributionFlowElementCommon - Reference: Standard
Type - Pset_FlowSegmentDuctSegment - Length: 2119.08 mm
Type - Pset_FlowSegmentPipeSegment - Length: 2119.08 mm; InvertElevation: 2687.74 mm
Type - Pset_ProductRequirements - Category: Pipes
Type - Pset_QuantityTakeOff - Reference: Standard
Pset_DistributionFlowElementCommon - sets with these values: 2
Pset_FlowSegmentDuctSegment - sets with these values: 2

# IfcFlowSegment: Pipe Types:Standard:932659:Standard:932659 : Pipe Types:Standard:932659:320901, Pipe Types:Standard:932659:Standard:932659 : Pipe Types:Standard:932659:320901:Standard:932659:Standard:932659 : Pipe Types:Standard:932659:320901 : Pipe Types:Standard:932659:Standard:932659 : Pipe Types:Standard:932659:320901:320887
In: Level 1
Type - Material: <Unnamed>
Type - Pset_DistributionFlowElementCommon - Reference: Standard
Type - Pset_FlowSegmentDuctSegment - Length: 268.888 mm
Type - Pset_FlowSegmentPipeSegment - Length: 268.888 mm; InvertElevation: 2686.94 mm
Type - Pset_ProductRequirements - Category: Pipes
Type - Pset_QuantityTakeOff - Reference: Standard
Pset_DistributionFlowElementCommon - sets with these values: 2
Pset_FlowSegmentDuctSegment - sets with these values: 2

# IfcFlowSegment: Pipe Types:Standard:932724:Standard:932724 : Pipe Types:Standard:932724:320913, Pipe Types:Standard:932724:Standard:932724 : Pipe Types:Standard:932724:320913:Standard:932724:Standard:932724 : Pipe Types:Standard:932724:320913 : Pipe Types:Standard:932724:Standard:932724 : Pipe Types:Standard:932724:320913:320899
In: Level 1
Type - Material: <Unnamed>
Type - Pset_DistributionFlowElementCommon - Reference: Standard
Type - Pset_FlowSegmentDuctSegment - Length: 1088.08 mm
Type - Pset_FlowSegmentPipeSegment - Length: 1088.08 mm; InvertElevation: 2687.74 mm
Type - Pset_ProductRequirements - Category: Pipes
Type - Pset_QuantityTakeOff - Reference: Standard
Pset_DistributionFlowElementCommon - sets with these values: 2
Pset_FlowSegmentDuctSegment - sets with these values: 2

# IfcFlowSegment: Pipe Types:Standard:932738:Standard:932738 : Pipe Types:Standard:932738:320925, Pipe Types:Standard:932738:Standard:932738 : Pipe Types:Standard:932738:320925:Standard:932738:Standard:932738 : Pipe Types:Standard:932738:320925 : Pipe Types:Standard:932738:Standard:932738 : Pipe Types:Standard:932738:320925:320911
In: Level 1
Type - Material: <Unnamed>
Type - Pset_DistributionFlowElementCommon - Reference: Standard
Type - Pset_FlowSegmentDuctSegment - Length: 2094.33 mm
Type - Pset_FlowSegmentPipeSegment - Length: 2094.33 mm; InvertElevation: 2687.74 mm
Type - Pset_ProductRequirements - Category: Pipes
Type - Pset_QuantityTakeOff - Reference: Standard
Pset_DistributionFlowElementCommon - sets with these values: 2
Pset_FlowSegmentDuctSegment - sets with these values: 2

# IfcFlowSegment: Pipe Types:Standard:932749:Standard:932749 : Pipe Types:Standard:932749:320937, Pipe Types:Standard:932749:Standard:932749 : Pipe Types:Standard:932749:320937:Standard:932749:Standard:932749 : Pipe Types:Standard:932749:320937 : Pipe Types:Standard:932749:Standard:932749 : Pipe Types:Standard:932749:320937:320923
In: Level 1
Type - Material: <Unnamed>
Type - Pset_DistributionFlowElementCommon - Reference: Standard
Type - Pset_FlowSegmentDuctSegment - Length: 5315.94 mm
Type - Pset_FlowSegmentPipeSegment - Length: 5315.94 mm; InvertElevation: 2687.74 mm
Type - Pset_ProductRequirements - Category: Pipes
Type - Pset_QuantityTakeOff - Reference: Standard
Pset_DistributionFlowElementCommon - sets with these values: 2
Pset_FlowSegmentDuctSegment - sets with these values: 2

# IfcFlowSegment: Pipe Types:Standard:932806:Standard:932806 : Pipe Types:Standard:932806:320949, Pipe Types:Standard:932806:Standard:932806 : Pipe Types:Standard:932806:320949:Standard:932806:Standard:932806 : Pipe Types:Standard:932806:320949 : Pipe Types:Standard:932806:Standard:932806 : Pipe Types:Standard:932806:320949:320935
In: Level 1
Type - Material: <Unnamed>
Type - Pset_DistributionFlowElementCommon - Reference: Standard
Type - Pset_FlowSegmentDuctSegment - Length: 2611.53 mm
Type - Pset_FlowSegmentPipeSegment - Length: 2611.53 mm; InvertElevation: 2704.67 mm
Type - Pset_ProductRequirements - Category: Pipes
Type - Pset_QuantityTakeOff - Reference: Standard
Pset_DistributionFlowElementCommon - sets with these values: 2
Pset_FlowSegmentDuctSegment - sets with these values: 2

# IfcFlowSegment: Pipe Types:Standard:932841:Standard:932841 : Pipe Types:Standard:932841:320961, Pipe Types:Standard:932841:Standard:932841 : Pipe Types:Standard:932841:320961:Standard:932841:Standard:932841 : Pipe Types:Standard:932841:320961 : Pipe Types:Standard:932841:Standard:932841 : Pipe Types:Standard:932841:320961:320947
In: Level 1
Type - Material: <Unnamed>
Type - Pset_DistributionFlowElementCommon - Reference: Standard
Type - Pset_FlowSegmentDuctSegment - Length: 2597.05 mm
Type - Pset_FlowSegmentPipeSegment - Length: 2597.05 mm; InvertElevation: 2686.94 mm
Type - Pset_ProductRequirements - Category: Pipes
Type - Pset_QuantityTakeOff - Reference: Standard
Pset_DistributionFlowElementCommon - sets with these values: 2
Pset_FlowSegmentDuctSegment - sets with these values: 2

# IfcFlowSegment: Pipe Types:Standard:932903:Standard:932903 : Pipe Types:Standard:932903:320973, Pipe Types:Standard:932903:Standard:932903 : Pipe Types:Standard:932903:320973:Standard:932903:Standard:932903 : Pipe Types:Standard:932903:320973 : Pipe Types:Standard:932903:Standard:932903 : Pipe Types:Standard:932903:320973:320959
In: Level 1
Type - Material: <Unnamed>
Type - Pset_DistributionFlowElementCommon - Reference: Standard
Type - Pset_FlowSegmentDuctSegment - Length: 1086.23 mm
Type - Pset_FlowSegmentPipeSegment - Length: 1086.23 mm; InvertElevation: 2704.67 mm
Type - Pset_ProductRequirements - Category: Pipes
Type - Pset_QuantityTakeOff - Reference: Standard
Pset_DistributionFlowElementCommon - sets with these values: 2
Pset_FlowSegmentDuctSegment - sets with these values: 2

# IfcFlowSegment: Pipe Types:Standard:932957:Standard:932957 : Pipe Types:Standard:932957:320985, Pipe Types:Standard:932957:Standard:932957 : Pipe Types:Standard:932957:320985:Standard:932957:Standard:932957 : Pipe Types:Standard:932957:320985 : Pipe Types:Standard:932957:Standard:932957 : Pipe Types:Standard:932957:320985:320971
In: Level 1
Type - Material: <Unnamed>
Type - Pset_DistributionFlowElementCommon - Reference: Standard
Type - Pset_FlowSegmentDuctSegment - Length: 1127.22 mm
Type - Pset_FlowSegmentPipeSegment - Length: 1127.22 mm; InvertElevation: 2687.74 mm
Type - Pset_ProductRequirements - Category: Pipes
Type - Pset_QuantityTakeOff - Reference: Standard
Pset_DistributionFlowElementCommon - sets with these values: 2
Pset_FlowSegmentDuctSegment - sets with these values: 2

# IfcFlowSegment: Pipe Types:Standard:933189:Standard:933189 : Pipe Types:Standard:933189:320997, Pipe Types:Standard:933189:Standard:933189 : Pipe Types:Standard:933189:320997:Standard:933189:Standard:933189 : Pipe Types:Standard:933189:320997 : Pipe Types:Standard:933189:Standard:933189 : Pipe Types:Standard:933189:320997:320983
In: Level 1
Type - Material: <Unnamed>
Type - Pset_DistributionFlowElementCommon - Reference: Standard
Type - Pset_FlowSegmentDuctSegment - Length: 1064.13 mm
Type - Pset_FlowSegmentPipeSegment - Length: 1064.13 mm; InvertElevation: 2686.26 mm
Type - Pset_ProductRequirements - Category: Pipes
Type - Pset_QuantityTakeOff - Reference: Standard
Pset_DistributionFlowElementCommon - sets with these values: 2
Pset_FlowSegmentDuctSegment - sets with these values: 2

# IfcFlowSegment: Pipe Types:Standard:933203:Standard:933203 : Pipe Types:Standard:933203:321009, Pipe Types:Standard:933203:Standard:933203 : Pipe Types:Standard:933203:321009:Standard:933203:Standard:933203 : Pipe Types:Standard:933203:321009 : Pipe Types:Standard:933203:Standard:933203 : Pipe Types:Standard:933203:321009:320995
In: Level 1
Type - Material: <Unnamed>
Type - Pset_DistributionFlowElementCommon - Reference: Standard
Type - Pset_FlowSegmentDuctSegment - Length: 1172.95 mm
Type - Pset_FlowSegmentPipeSegment - Length: 1172.95 mm; InvertElevation: 2686.94 mm
Type - Pset_ProductRequirements - Category: Pipes
Type - Pset_QuantityTakeOff - Reference: Standard
Pset_DistributionFlowElementCommon - sets with these values: 2
Pset_FlowSegmentDuctSegment - sets with these values: 2

# IfcFlowSegment: Pipe Types:Standard:933234:Standard:933234 : Pipe Types:Standard:933234:321021, Pipe Types:Standard:933234:Standard:933234 : Pipe Types:Standard:933234:321021:Standard:933234:Standard:933234 : Pipe Types:Standard:933234:321021 : Pipe Types:Standard:933234:Standard:933234 : Pipe Types:Standard:933234:321021:321007
In: Level 1
Type - Material: <Unnamed>
Type - Pset_DistributionFlowElementCommon - Reference: Standard
Type - Pset_FlowSegmentDuctSegment - Length: 955.424 mm
Type - Pset_FlowSegmentPipeSegment - Length: 955.424 mm; InvertElevation: 2704.67 mm
Type - Pset_ProductRequirements - Category: Pipes
Type - Pset_QuantityTakeOff - Reference: Standard
Pset_DistributionFlowElementCommon - sets with these values: 2
Pset_FlowSegmentDuctSegment - sets with these values: 2

# IfcFlowSegment: Pipe Types:Standard:933244:Standard:933244 : Pipe Types:Standard:933244:321033, Pipe Types:Standard:933244:Standard:933244 : Pipe Types:Standard:933244:321033:Standard:933244:Standard:933244 : Pipe Types:Standard:933244:321033 : Pipe Types:Standard:933244:Standard:933244 : Pipe Types:Standard:933244:321033:321019
In: Level 1
Type - Material: <Unnamed>
Type - Pset_DistributionFlowElementCommon - Reference: Standard
Type - Pset_FlowSegmentDuctSegment - Length: 1273.68 mm
Type - Pset_FlowSegmentPipeSegment - Length: 1273.68 mm; InvertElevation: 2704.67 mm
Type - Pset_ProductRequirements - Category: Pipes
Type - Pset_QuantityTakeOff - Reference: Standard
Pset_DistributionFlowElementCommon - sets with these values: 2
Pset_FlowSegmentDuctSegment - sets with these values: 2

# IfcFlowSegment: Pipe Types:Standard:933316:Standard:933316 : Pipe Types:Standard:933316:321078, Pipe Types:Standard:933316:Standard:933316 : Pipe Types:Standard:933316:321078:Standard:933316:Standard:933316 : Pipe Types:Standard:933316:321078 : Pipe Types:Standard:933316:Standard:933316 : Pipe Types:Standard:933316:321078:321031
In: Level 1
Type - Material: <Unnamed>
Type - Pset_DistributionFlowElementCommon - Reference: Standard
Type - Pset_FlowSegmentDuctSegment - Length: 3662.85 mm
Type - Pset_FlowSegmentPipeSegment - Length: 3662.85 mm; InvertElevation: 2704.67 mm
Type - Pset_ProductRequirements - Category: Pipes
Type - Pset_QuantityTakeOff - Reference: Standard
Pset_DistributionFlowElementCommon - sets with these values: 2
Pset_FlowSegmentDuctSegment - sets with these values: 2

# IfcFlowSegment: Pipe Types:Standard:933586:Standard:933586 : Pipe Types:Standard:933586:321090, Pipe Types:Standard:933586:Standard:933586 : Pipe Types:Standard:933586:321090:Standard:933586:Standard:933586 : Pipe Types:Standard:933586:321090 : Pipe Types:Standard:933586:Standard:933586 : Pipe Types:Standard:933586:321090:321043
In: Level 1
Type - Material: <Unnamed>
Type - Pset_DistributionFlowElementCommon - Reference: Standard
Type - Pset_FlowSegmentDuctSegment - Length: 3647.42 mm
Type - Pset_FlowSegmentPipeSegment - Length: 3647.42 mm; InvertElevation: 2686.26 mm
Type - Pset_ProductRequirements - Category: Pipes
Type - Pset_QuantityTakeOff - Reference: Standard
Pset_DistributionFlowElementCommon - sets with these values: 2
Pset_FlowSegmentDuctSegment - sets with these values: 2

# IfcFlowSegment: Pipe Types:Standard:934197:Standard:934197 : Pipe Types:Standard:934197:321102, Pipe Types:Standard:934197:Standard:934197 : Pipe Types:Standard:934197:321102:Standard:934197:Standard:934197 : Pipe Types:Standard:934197:321102 : Pipe Types:Standard:934197:Standard:934197 : Pipe Types:Standard:934197:321102:321055
In: Level 1
Type - Material: <Unnamed>
Type - Pset_DistributionFlowElementCommon - Reference: Standard
Type - Pset_FlowSegmentDuctSegment - Length: 1145.71 mm
Type - Pset_FlowSegmentPipeSegment - Length: 1145.71 mm; InvertElevation: 2704.67 mm
Type - Pset_ProductRequirements - Category: Pipes
Type - Pset_QuantityTakeOff - Reference: Standard
Pset_DistributionFlowElementCommon - sets with these values: 2
Pset_FlowSegmentDuctSegment - sets with these values: 2

# IfcFlowSegment: Pipe Types:Standard:934227:Standard:934227 : Pipe Types:Standard:934227:321114, Pipe Types:Standard:934227:Standard:934227 : Pipe Types:Standard:934227:321114:Standard:934227:Standard:934227 : Pipe Types:Standard:934227:321114 : Pipe Types:Standard:934227:Standard:934227 : Pipe Types:Standard:934227:321114:321067
In: Level 1
Type - Material: <Unnamed>
Type - Pset_DistributionFlowElementCommon - Reference: Standard
Type - Pset_FlowSegmentDuctSegment - Length: 1100.24 mm
Type - Pset_FlowSegmentPipeSegment - Length: 1100.24 mm; InvertElevation: 2687.74 mm
Type - Pset_ProductRequirements - Category: Pipes
Type - Pset_QuantityTakeOff - Reference: Standard
Pset_DistributionFlowElementCommon - sets with these values: 2
Pset_FlowSegmentDuctSegment - sets with these values: 2

# IfcFlowSegment: Pipe Types:Standard:934327:Standard:934327 : Pipe Types:Standard:934327:321126, Pipe Types:Standard:934327:Standard:934327 : Pipe Types:Standard:934327:321126:Standard:934327:Standard:934327 : Pipe Types:Standard:934327:321126 : Pipe Types:Standard:934327:Standard:934327 : Pipe Types:Standard:934327:321126:321079
In: Level 1
Type - Material: <Unnamed>
Type - Pset_DistributionFlowElementCommon - Reference: Standard
Type - Pset_FlowSegmentDuctSegment - Length: 493.794 mm
Type - Pset_FlowSegmentPipeSegment - Length: 493.794 mm; InvertElevation: 2687.74 mm
Type - Pset_ProductRequirements - Category: Pipes
Type - Pset_QuantityTakeOff - Reference: Standard
Pset_DistributionFlowElementCommon - sets with these values: 2
Pset_FlowSegmentDuctSegment - sets with these values: 2

# IfcFlowSegment: Pipe Types:Standard:934351:Standard:934351 : Pipe Types:Standard:934351:321138, Pipe Types:Standard:934351:Standard:934351 : Pipe Types:Standard:934351:321138:Standard:934351:Standard:934351 : Pipe Types:Standard:934351:321138 : Pipe Types:Standard:934351:Standard:934351 : Pipe Types:Standard:934351:321138:321091
In: Level 1
Type - Material: <Unnamed>
Type - Pset_DistributionFlowElementCommon - Reference: Standard
Type - Pset_FlowSegmentDuctSegment - Length: 472.894 mm
Type - Pset_FlowSegmentPipeSegment - Length: 472.894 mm; InvertElevation: 2704.67 mm
Type - Pset_ProductRequirements - Category: Pipes
Type - Pset_QuantityTakeOff - Reference: Standard
Pset_DistributionFlowElementCommon - sets with these values: 2
Pset_FlowSegmentDuctSegment - sets with these values: 2

# IfcFlowSegment: Pipe Types:Standard:934787:Standard:934787 : Pipe Types:Standard:934787:321174, Pipe Types:Standard:934787:Standard:934787 : Pipe Types:Standard:934787:321174:Standard:934787:Standard:934787 : Pipe Types:Standard:934787:321174 : Pipe Types:Standard:934787:Standard:934787 : Pipe Types:Standard:934787:321174:321103
In: Level 1
Type - Material: <Unnamed>
Type - Pset_DistributionFlowElementCommon - Reference: Standard
Type - Pset_FlowSegmentDuctSegment - Length: 1680.63 mm
Type - Pset_FlowSegmentPipeSegment - Length: 1680.63 mm; InvertElevation: 2686.26 mm
Type - Pset_ProductRequirements - Category: Pipes
Type - Pset_QuantityTakeOff - Reference: Standard
Pset_DistributionFlowElementCommon - sets with these values: 2
Pset_FlowSegmentDuctSegment - sets with these values: 2

# IfcFlowSegment: Pipe Types:Standard:934799:Standard:934799 : Pipe Types:Standard:934799:321186, Pipe Types:Standard:934799:Standard:934799 : Pipe Types:Standard:934799:321186:Standard:934799:Standard:934799 : Pipe Types:Standard:934799:321186 : Pipe Types:Standard:934799:Standard:934799 : Pipe Types:Standard:934799:321186:321115
In: Level 1
Type - Material: <Unnamed>
Type - Pset_DistributionFlowElementCommon - Reference: Standard
Type - Pset_FlowSegmentDuctSegment - Length: 552.206 mm
Type - Pset_FlowSegmentPipeSegment - Length: 552.206 mm; InvertElevation: 2686.26 mm
Type - Pset_ProductRequirements - Category: Pipes
Type - Pset_QuantityTakeOff - Reference: Standard
Pset_DistributionFlowElementCommon - sets with these values: 2
Pset_FlowSegmentDuctSegment - sets with these values: 2

# IfcFlowSegment: Pipe Types:Standard:934825:Standard:934825 : Pipe Types:Standard:934825:321198, Pipe Types:Standard:934825:Standard:934825 : Pipe Types:Standard:934825:321198:Standard:934825:Standard:934825 : Pipe Types:Standard:934825:321198 : Pipe Types:Standard:934825:Standard:934825 : Pipe Types:Standard:934825:321198:321127
In: Level 1
Type - Material: <Unnamed>
Type - Pset_DistributionFlowElementCommon - Reference: Standard
Type - Pset_FlowSegmentDuctSegment - Length: 601.744 mm
Type - Pset_FlowSegmentPipeSegment - Length: 601.744 mm; InvertElevation: 2704.67 mm
Type - Pset_ProductRequirements - Category: Pipes
Type - Pset_QuantityTakeOff - Reference: Standard
Pset_DistributionFlowElementCommon - sets with these values: 2
Pset_FlowSegmentDuctSegment - sets with these values: 2

# IfcFlowSegment: Pipe Types:Standard:934835:Standard:934835 : Pipe Types:Standard:934835:321210, Pipe Types:Standard:934835:Standard:934835 : Pipe Types:Standard:934835:321210:Standard:934835:Standard:934835 : Pipe Types:Standard:934835:321210 : Pipe Types:Standard:934835:Standard:934835 : Pipe Types:Standard:934835:321210:321139
In: Level 1
Type - Material: <Unnamed>
Type - Pset_DistributionFlowElementCommon - Reference: Standard
Type - Pset_FlowSegmentDuctSegment - Length: 4670.21 mm
Type - Pset_FlowSegmentPipeSegment - Length: 4670.21 mm; InvertElevation: 2704.67 mm
Type - Pset_ProductRequirements - Category: Pipes
Type - Pset_QuantityTakeOff - Reference: Standard
Pset_DistributionFlowElementCommon - sets with these values: 2
Pset_FlowSegmentDuctSegment - sets with these values: 2

# IfcFlowSegment: Pipe Types:Standard:934846:Standard:934846 : Pipe Types:Standard:934846:321222, Pipe Types:Standard:934846:Standard:934846 : Pipe Types:Standard:934846:321222:Standard:934846:Standard:934846 : Pipe Types:Standard:934846:321222 : Pipe Types:Standard:934846:Standard:934846 : Pipe Types:Standard:934846:321222:321151
In: Level 1
Type - Material: <Unnamed>
Type - Pset_DistributionFlowElementCommon - Reference: Standard
Type - Pset_FlowSegmentDuctSegment - Length: 3470.87 mm
Type - Pset_FlowSegmentPipeSegment - Length: 3470.87 mm; InvertElevation: 2701.89 mm
Type - Pset_ProductRequirements - Category: Pipes
Type - Pset_QuantityTakeOff - Reference: Standard
Pset_DistributionFlowElementCommon - sets with these values: 2
Pset_FlowSegmentDuctSegment - sets with these values: 2

# IfcFlowSegment: Pipe Types:Standard:934862:Standard:934862 : Pipe Types:Standard:934862:321234, Pipe Types:Standard:934862:Standard:934862 : Pipe Types:Standard:934862:321234:Standard:934862:Standard:934862 : Pipe Types:Standard:934862:321234 : Pipe Types:Standard:934862:Standard:934862 : Pipe Types:Standard:934862:321234:321163
In: Level 1
Type - Material: <Unnamed>
Type - Pset_DistributionFlowElementCommon - Reference: Standard
Type - Pset_FlowSegmentDuctSegment - Length: 548.081 mm
Type - Pset_FlowSegmentPipeSegment - Length: 548.081 mm; InvertElevation: 2687.74 mm
Type - Pset_ProductRequirements - Category: Pipes
Type - Pset_QuantityTakeOff - Reference: Standard
Pset_DistributionFlowElementCommon - sets with these values: 2
Pset_FlowSegmentDuctSegment - sets with these values: 2

# IfcFlowSegment: Pipe Types:Standard:934876:Standard:934876 : Pipe Types:Standard:934876:321246, Pipe Types:Standard:934876:Standard:934876 : Pipe Types:Standard:934876:321246:Standard:934876:Standard:934876 : Pipe Types:Standard:934876:321246 : Pipe Types:Standard:934876:Standard:934876 : Pipe Types:Standard:934876:321246:321175
In: Level 1
Type - Material: <Unnamed>
Type - Pset_DistributionFlowElementCommon - Reference: Standard
Type - Pset_FlowSegmentDuctSegment - Length: 4671.25 mm
Type - Pset_FlowSegmentPipeSegment - Length: 4671.25 mm; InvertElevation: 2687.74 mm
Type - Pset_ProductRequirements - Category: Pipes
Type - Pset_QuantityTakeOff - Reference: Standard
Pset_DistributionFlowElementCommon - sets with these values: 2
Pset_FlowSegmentDuctSegment - sets with these values: 2

# IfcFlowSegment: Pipe Types:Standard:934892:Standard:934892 : Pipe Types:Standard:934892:321258, Pipe Types:Standard:934892:Standard:934892 : Pipe Types:Standard:934892:321258:Standard:934892:Standard:934892 : Pipe Types:Standard:934892:321258 : Pipe Types:Standard:934892:Standard:934892 : Pipe Types:Standard:934892:321258:321187
In: Level 1
Type - Material: <Unnamed>
Type - Pset_DistributionFlowElementCommon - Reference: Standard
Type - Pset_FlowSegmentDuctSegment - Length: 3480 mm
Type - Pset_FlowSegmentPipeSegment - Length: 3480 mm; InvertElevation: 2686.26 mm
Type - Pset_ProductRequirements - Category: Pipes
Type - Pset_QuantityTakeOff - Reference: Standard
Pset_DistributionFlowElementCommon - sets with these values: 2
Pset_FlowSegmentDuctSegment - sets with these values: 2

# IfcFlowSegment: Pipe Types:Standard:935063:Standard:935063 : Pipe Types:Standard:935063:321270, Pipe Types:Standard:935063:Standard:935063 : Pipe Types:Standard:935063:321270:Standard:935063:Standard:935063 : Pipe Types:Standard:935063:321270 : Pipe Types:Standard:935063:Standard:935063 : Pipe Types:Standard:935063:321270:321199
In: Level 1
Type - Material: <Unnamed>
Type - Pset_DistributionFlowElementCommon - Reference: Standard
Type - Pset_FlowSegmentDuctSegment - Length: 803.332 mm
Type - Pset_FlowSegmentPipeSegment - Length: 803.332 mm; InvertElevation: 2727.46 mm
Type - Pset_ProductRequirements - Category: Pipes
Type - Pset_QuantityTakeOff - Reference: Standard
Pset_DistributionFlowElementCommon - sets with these values: 2
Pset_FlowSegmentDuctSegment - sets with these values: 2

# IfcFlowSegment: Pipe Types:Standard:935098:Standard:935098 : Pipe Types:Standard:935098:321282, Pipe Types:Standard:935098:Standard:935098 : Pipe Types:Standard:935098:321282:Standard:935098:Standard:935098 : Pipe Types:Standard:935098:321282 : Pipe Types:Standard:935098:Standard:935098 : Pipe Types:Standard:935098:321282:321211
In: Level 1
Type - Material: <Unnamed>
Type - Pset_DistributionFlowElementCommon - Reference: Standard
Type - Pset_FlowSegmentDuctSegment - Length: 835.357 mm
Type - Pset_FlowSegmentPipeSegment - Length: 835.357 mm; InvertElevation: 2702.7 mm
Type - Pset_ProductRequirements - Category: Pipes
Type - Pset_QuantityTakeOff - Reference: Standard
Pset_DistributionFlowElementCommon - sets with these values: 2
Pset_FlowSegmentDuctSegment - sets with these values: 2
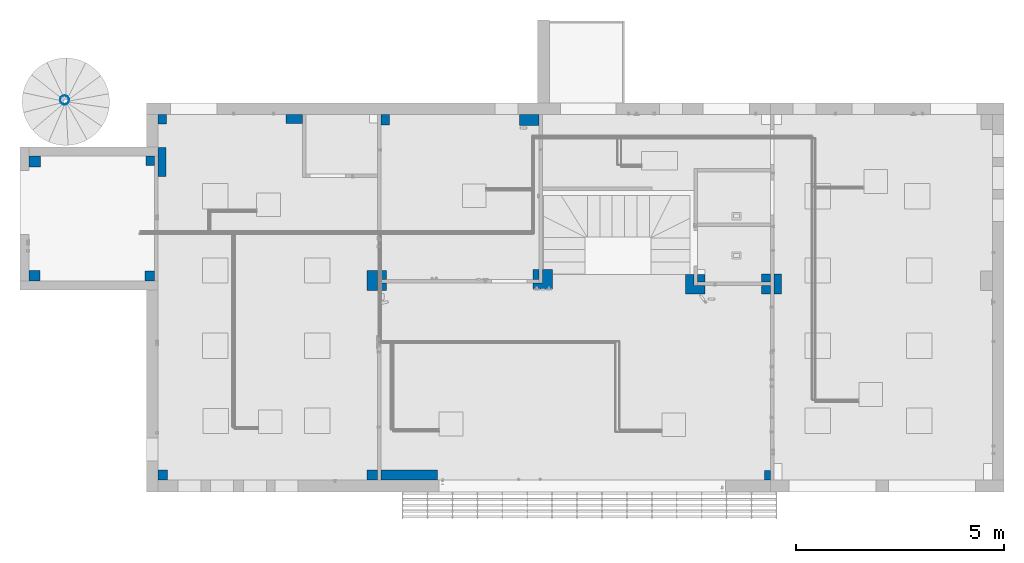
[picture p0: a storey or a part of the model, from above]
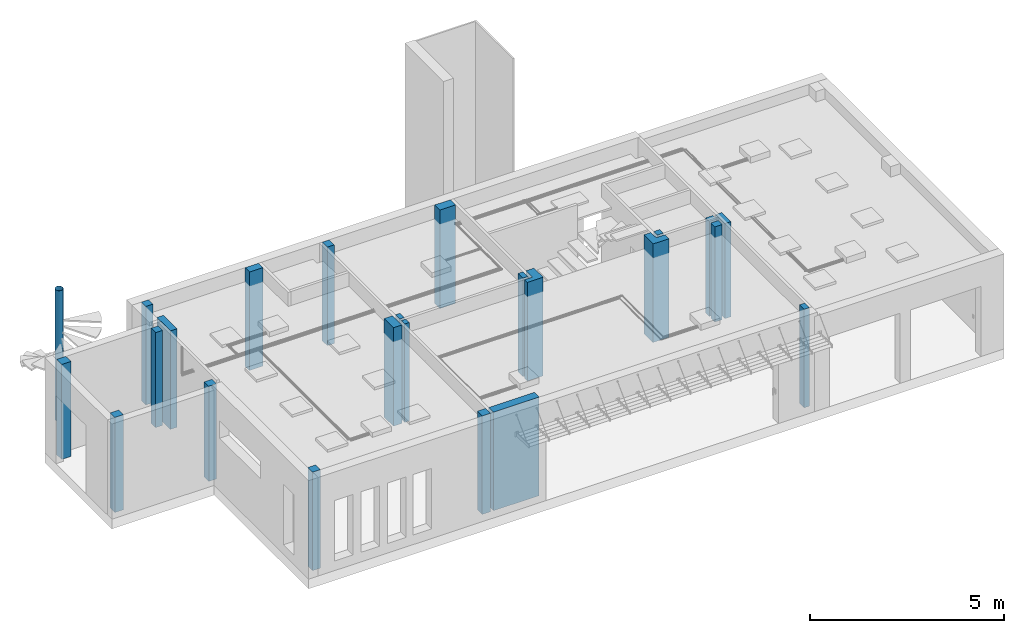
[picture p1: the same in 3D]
Properties of the parts of a building model (IFC2X3), part 5 of 5

# IfcFlowSegment: Pipe Types:Standard:935828:Standard:935828 : Pipe Types:Standard:935828:321294, Pipe Types:Standard:935828:Standard:935828 : Pipe Types:Standard:935828:321294:Standard:935828:Standard:935828 : Pipe Types:Standard:935828:321294 : Pipe Types:Standard:935828:Standard:935828 : Pipe Types:Standard:935828:321294:321223
In: Level 1
Type - Material: <Unnamed>
Type - Pset_DistributionFlowElementCommon - Reference: Standard
Type - Pset_FlowSegmentDuctSegment - Length: 1600.42 mm
Type - Pset_FlowSegmentPipeSegment - Length: 1600.42 mm; InvertElevation: 2701.89 mm
Type - Pset_ProductRequirements - Category: Pipes
Type - Pset_QuantityTakeOff - Reference: Standard
Pset_DistributionFlowElementCommon - sets with these values: 2
Pset_FlowSegmentDuctSegment - sets with these values: 2

# IfcFlowSegment: Pipe Types:Standard:935840:Standard:935840 : Pipe Types:Standard:935840:321306, Pipe Types:Standard:935840:Standard:935840 : Pipe Types:Standard:935840:321306:Standard:935840:Standard:935840 : Pipe Types:Standard:935840:321306 : Pipe Types:Standard:935840:Standard:935840 : Pipe Types:Standard:935840:321306:321235
In: Level 1
Type - Material: <Unnamed>
Type - Pset_DistributionFlowElementCommon - Reference: Standard
Type - Pset_FlowSegmentDuctSegment - Length: 534.492 mm
Type - Pset_FlowSegmentPipeSegment - Length: 534.492 mm; InvertElevation: 2701.89 mm
Type - Pset_ProductRequirements - Category: Pipes
Type - Pset_QuantityTakeOff - Reference: Standard
Pset_DistributionFlowElementCommon - sets with these values: 2
Pset_FlowSegmentDuctSegment - sets with these values: 2

# IfcFlowSegment: Pipe Types:Standard:937964:Standard:937964 : Pipe Types:Standard:937964:321318, Pipe Types:Standard:937964:Standard:937964 : Pipe Types:Standard:937964:321318:Standard:937964:Standard:937964 : Pipe Types:Standard:937964:321318 : Pipe Types:Standard:937964:Standard:937964 : Pipe Types:Standard:937964:321318:321247
In: Level 1
Type - Material: <Unnamed>
Type - Pset_DistributionFlowElementCommon - Reference: Standard
Type - Pset_FlowSegmentDuctSegment - Length: 478.556 mm
Type - Pset_FlowSegmentPipeSegment - Length: 478.556 mm; InvertElevation: 2687.74 mm
Type - Pset_ProductRequirements - Category: Pipes
Type - Pset_QuantityTakeOff - Reference: Standard
Pset_DistributionFlowElementCommon - sets with these values: 2
Pset_FlowSegmentDuctSegment - sets with these values: 2

# IfcFlowSegment: Pipe Types:Standard:940681:Standard:940681 : Pipe Types:Standard:940681:321330, Pipe Types:Standard:940681:Standard:940681 : Pipe Types:Standard:940681:321330:Standard:940681:Standard:940681 : Pipe Types:Standard:940681:321330 : Pipe Types:Standard:940681:Standard:940681 : Pipe Types:Standard:940681:321330:321259
In: Level 1
Type - Material: <Unnamed>
Type - Pset_DistributionFlowElementCommon - Reference: Standard
Type - Pset_FlowSegmentDuctSegment - Length: 664.267 mm
Type - Pset_FlowSegmentPipeSegment - Length: 664.267 mm; InvertElevation: 2687.74 mm
Type - Pset_ProductRequirements - Category: Pipes
Type - Pset_QuantityTakeOff - Reference: Standard
Pset_DistributionFlowElementCommon - sets with these values: 2
Pset_FlowSegmentDuctSegment - sets with these values: 2

# IfcFlowSegment: Pipe Types:Standard:940694:Standard:940694 : Pipe Types:Standard:940694:321342, Pipe Types:Standard:940694:Standard:940694 : Pipe Types:Standard:940694:321342:Standard:940694:Standard:940694 : Pipe Types:Standard:940694:321342 : Pipe Types:Standard:940694:Standard:940694 : Pipe Types:Standard:940694:321342:321271
In: Level 1
Type - Material: <Unnamed>
Type - Pset_DistributionFlowElementCommon - Reference: Standard
Type - Pset_FlowSegmentDuctSegment - Length: 2074.5 mm
Type - Pset_FlowSegmentPipeSegment - Length: 2074.5 mm; InvertElevation: 2686.94 mm
Type - Pset_ProductRequirements - Category: Pipes
Type - Pset_QuantityTakeOff - Reference: Standard
Pset_DistributionFlowElementCommon - sets with these values: 2
Pset_FlowSegmentDuctSegment - sets with these values: 2

# IfcFlowSegment: Pipe Types:Standard:940753:Standard:940753 : Pipe Types:Standard:940753:321354, Pipe Types:Standard:940753:Standard:940753 : Pipe Types:Standard:940753:321354:Standard:940753:Standard:940753 : Pipe Types:Standard:940753:321354 : Pipe Types:Standard:940753:Standard:940753 : Pipe Types:Standard:940753:321354:321283
In: Level 1
Type - Material: <Unnamed>
Type - Pset_DistributionFlowElementCommon - Reference: Standard
Type - Pset_FlowSegmentDuctSegment - Length: 561.744 mm
Type - Pset_FlowSegmentPipeSegment - Length: 561.744 mm; InvertElevation: 2704.67 mm
Type - Pset_ProductRequirements - Category: Pipes
Type - Pset_QuantityTakeOff - Reference: Standard
Pset_DistributionFlowElementCommon - sets with these values: 2
Pset_FlowSegmentDuctSegment - sets with these values: 2

# IfcFlowSegment: Pipe Types:Standard:941703:Standard:941703 : Pipe Types:Standard:941703:321366, Pipe Types:Standard:941703:Standard:941703 : Pipe Types:Standard:941703:321366:Standard:941703:Standard:941703 : Pipe Types:Standard:941703:321366 : Pipe Types:Standard:941703:Standard:941703 : Pipe Types:Standard:941703:321366:321295
In: Level 1
Type - Material: <Unnamed>
Type - Pset_DistributionFlowElementCommon - Reference: Standard
Type - Pset_FlowSegmentDuctSegment - Length: 667.668 mm
Type - Pset_FlowSegmentPipeSegment - Length: 667.668 mm; InvertElevation: 2704.67 mm
Type - Pset_ProductRequirements - Category: Pipes
Type - Pset_QuantityTakeOff - Reference: Standard
Pset_DistributionFlowElementCommon - sets with these values: 2
Pset_FlowSegmentDuctSegment - sets with these values: 2

# IfcFlowSegment: Pipe Types:Standard:943525:Standard:943525 : Pipe Types:Standard:943525:321378, Pipe Types:Standard:943525:Standard:943525 : Pipe Types:Standard:943525:321378:Standard:943525:Standard:943525 : Pipe Types:Standard:943525:321378 : Pipe Types:Standard:943525:Standard:943525 : Pipe Types:Standard:943525:321378:321307
In: Level 1
Type - Material: <Unnamed>
Type - Pset_DistributionFlowElementCommon - Reference: Standard
Type - Pset_FlowSegmentDuctSegment - Length: 4652.54 mm
Type - Pset_FlowSegmentPipeSegment - Length: 4652.54 mm; InvertElevation: 2704.67 mm
Type - Pset_ProductRequirements - Category: Pipes
Type - Pset_QuantityTakeOff - Reference: Standard
Pset_DistributionFlowElementCommon - sets with these values: 2
Pset_FlowSegmentDuctSegment - sets with these values: 2

# IfcFlowTerminal: M_Return Grille with Trim - Ceiling Mounted:228 mmx178 mm Face 150 mmx100 mm Neck:1027041:228 mmx178 mm Face 150 mmx100 mm Neck:1027041 : M_Return Grille with Trim - Ceiling Mounted:228 mmx178 mm Face 150 mmx100 mm Neck:1027041:325045, M_Return Grille with Trim - Ceiling Mounted:228 mmx178 mm Face 150 mmx100 mm Neck:1027041:228 mmx178 mm Face 150 mmx100 mm Neck:1027041 : M_Return Grille with Trim - Ceiling Mounted:228 mmx178 mm Face 150 mmx100 mm Neck:1027041:325045:228 mmx178 mm Face 150 mmx100 mm Neck:1027041:228 mmx178 mm Face 150 mmx100 mm Neck:1027041 : M_Return Grille with Trim - Ceiling Mounted:228 mmx178 mm Face 150 mmx100 mm Neck:1027041:325045 : M_Return Grille with Trim - Ceiling Mounted:228 mmx178 mm Face 150 mmx100 mm Neck:1027041:228 mmx178 mm Face 150 mmx100 mm Neck:1027041 : M_Return Grille with Trim - Ceiling Mounted:228 mmx178 mm Face 150 mmx100 mm Neck:1027041:325045:323909
In: Level 1
Type - Material: <Unnamed> (2)
Type - Pset_DistributionFlowElementCommon - Reference: 228 mmx178 mm Face 150 mmx100 mm Neck
Type - Pset_ProductRequirements - Category: Air Terminals
Type - Pset_QuantityTakeOff - Reference: 228 mmx178 mm Face 150 mmx100 mm Neck
Pset_DistributionFlowElementCommon - sets with these values: 2

# IfcFlowTerminal: M_Return Grille with Trim - Ceiling Mounted:228 mmx178 mm Face 150 mmx100 mm Neck:1027042:228 mmx178 mm Face 150 mmx100 mm Neck:1027042 : M_Return Grille with Trim - Ceiling Mounted:228 mmx178 mm Face 150 mmx100 mm Neck:1027042:325015, M_Return Grille with Trim - Ceiling Mounted:228 mmx178 mm Face 150 mmx100 mm Neck:1027042:228 mmx178 mm Face 150 mmx100 mm Neck:1027042 : M_Return Grille with Trim - Ceiling Mounted:228 mmx178 mm Face 150 mmx100 mm Neck:1027042:325015:228 mmx178 mm Face 150 mmx100 mm Neck:1027042:228 mmx178 mm Face 150 mmx100 mm Neck:1027042 : M_Return Grille with Trim - Ceiling Mounted:228 mmx178 mm Face 150 mmx100 mm Neck:1027042:325015 : M_Return Grille with Trim - Ceiling Mounted:228 mmx178 mm Face 150 mmx100 mm Neck:1027042:228 mmx178 mm Face 150 mmx100 mm Neck:1027042 : M_Return Grille with Trim - Ceiling Mounted:228 mmx178 mm Face 150 mmx100 mm Neck:1027042:325015:323883
In: Level 1
Type - Material: <Unnamed> (2)
Type - Pset_DistributionFlowElementCommon - Reference: 228 mmx178 mm Face 150 mmx100 mm Neck
Type - Pset_ProductRequirements - Category: Air Terminals
Type - Pset_QuantityTakeOff - Reference: 228 mmx178 mm Face 150 mmx100 mm Neck
Pset_DistributionFlowElementCommon - sets with these values: 2

# IfcFlowTerminal: M_Troffer Light - Parabolic Square control rooms:0600x0600mm(2 Lamp) - 120V:1027467:0600x0600mm(2 Lamp) - 120V:1027467 : M_Troffer Light - Parabolic Square control rooms:0600x0600mm(2 Lamp) - 120V:1027467:323431, M_Troffer Light - Parabolic Square control rooms:0600x0600mm(2 Lamp) - 120V:1027467:0600x0600mm(2 Lamp) - 120V:1027467 : M_Troffer Light - Parabolic Square control rooms:0600x0600mm(2 Lamp) - 120V:1027467:323431:0600x0600mm(2 Lamp) - 120V:1027467:0600x0600mm(2 Lamp) - 120V:1027467 : M_Troffer Light - Parabolic Square control rooms:0600x0600mm(2 Lamp) - 120V:1027467:323431 : M_Troffer Light - Parabolic Square control rooms:0600x0600mm(2 Lamp) - 120V:1027467:0600x0600mm(2 Lamp) - 120V:1027467 : M_Troffer Light - Parabolic Square control rooms:0600x0600mm(2 Lamp) - 120V:1027467:323431:323033
In: Level 1
Type - Material: Glass, White, High Luminance (2), Steel, Chrome Plated 155972 (2)
Type - Pset_DistributionFlowElementCommon - Reference: 0600x0600mm(2 Lamp) - 120V
Type - Pset_ProductRequirements - Category: Lighting Fixtures
Type - Pset_QuantityTakeOff - Reference: 0600x0600mm(2 Lamp) - 120V
Pset_DistributionFlowElementCommon - sets with these values: 2

# IfcFlowTerminal: M_Troffer Light - Parabolic Square control rooms:0600x0600mm(2 Lamp) - 120V:1027469:0600x0600mm(2 Lamp) - 120V:1027469 : M_Troffer Light - Parabolic Square control rooms:0600x0600mm(2 Lamp) - 120V:1027469:323481, M_Troffer Light - Parabolic Square control rooms:0600x0600mm(2 Lamp) - 120V:1027469:0600x0600mm(2 Lamp) - 120V:1027469 : M_Troffer Light - Parabolic Square control rooms:0600x0600mm(2 Lamp) - 120V:1027469:323481:0600x0600mm(2 Lamp) - 120V:1027469:0600x0600mm(2 Lamp) - 120V:1027469 : M_Troffer Light - Parabolic Square control rooms:0600x0600mm(2 Lamp) - 120V:1027469:323481 : M_Troffer Light - Parabolic Square control rooms:0600x0600mm(2 Lamp) - 120V:1027469:0600x0600mm(2 Lamp) - 120V:1027469 : M_Troffer Light - Parabolic Square control rooms:0600x0600mm(2 Lamp) - 120V:1027469:323481:323079
In: Level 1
Type - Material: Glass, White, High Luminance (2), Steel, Chrome Plated 155972 (2)
Type - Pset_DistributionFlowElementCommon - Reference: 0600x0600mm(2 Lamp) - 120V
Type - Pset_ProductRequirements - Category: Lighting Fixtures
Type - Pset_QuantityTakeOff - Reference: 0600x0600mm(2 Lamp) - 120V
Pset_DistributionFlowElementCommon - sets with these values: 2

# IfcFlowTerminal: M_Troffer Light - Parabolic Square control rooms:0600x0600mm(2 Lamp) - 120V:1027470:0600x0600mm(2 Lamp) - 120V:1027470 : M_Troffer Light - Parabolic Square control rooms:0600x0600mm(2 Lamp) - 120V:1027470:323520, M_Troffer Light - Parabolic Square control rooms:0600x0600mm(2 Lamp) - 120V:1027470:0600x0600mm(2 Lamp) - 120V:1027470 : M_Troffer Light - Parabolic Square control rooms:0600x0600mm(2 Lamp) - 120V:1027470:323520:0600x0600mm(2 Lamp) - 120V:1027470:0600x0600mm(2 Lamp) - 120V:1027470 : M_Troffer Light - Parabolic Square control rooms:0600x0600mm(2 Lamp) - 120V:1027470:323520 : M_Troffer Light - Parabolic Square control rooms:0600x0600mm(2 Lamp) - 120V:1027470:0600x0600mm(2 Lamp) - 120V:1027470 : M_Troffer Light - Parabolic Square control rooms:0600x0600mm(2 Lamp) - 120V:1027470:323520:323118
In: Level 1
Type - Material: Glass, White, High Luminance (2), Steel, Chrome Plated 155972 (2)
Type - Pset_DistributionFlowElementCommon - Reference: 0600x0600mm(2 Lamp) - 120V
Type - Pset_ProductRequirements - Category: Lighting Fixtures
Type - Pset_QuantityTakeOff - Reference: 0600x0600mm(2 Lamp) - 120V
Pset_DistributionFlowElementCommon - sets with these values: 2

# IfcFlowTerminal: M_Troffer Light - Parabolic Square control rooms:0600x0600mm(2 Lamp) - 120V:1027471:0600x0600mm(2 Lamp) - 120V:1027471 : M_Troffer Light - Parabolic Square control rooms:0600x0600mm(2 Lamp) - 120V:1027471:323559, M_Troffer Light - Parabolic Square control rooms:0600x0600mm(2 Lamp) - 120V:1027471:0600x0600mm(2 Lamp) - 120V:1027471 : M_Troffer Light - Parabolic Square control rooms:0600x0600mm(2 Lamp) - 120V:1027471:323559:0600x0600mm(2 Lamp) - 120V:1027471:0600x0600mm(2 Lamp) - 120V:1027471 : M_Troffer Light - Parabolic Square control rooms:0600x0600mm(2 Lamp) - 120V:1027471:323559 : M_Troffer Light - Parabolic Square control rooms:0600x0600mm(2 Lamp) - 120V:1027471:0600x0600mm(2 Lamp) - 120V:1027471 : M_Troffer Light - Parabolic Square control rooms:0600x0600mm(2 Lamp) - 120V:1027471:323559:323157
In: Level 1
Type - Material: Glass, White, High Luminance (2), Steel, Chrome Plated 155972 (2)
Type - Pset_DistributionFlowElementCommon - Reference: 0600x0600mm(2 Lamp) - 120V
Type - Pset_ProductRequirements - Category: Lighting Fixtures
Type - Pset_QuantityTakeOff - Reference: 0600x0600mm(2 Lamp) - 120V
Pset_DistributionFlowElementCommon - sets with these values: 2

# IfcFlowTerminal: M_Troffer Light - Parabolic Square control rooms:0600x0600mm(2 Lamp) - 120V:1027472:0600x0600mm(2 Lamp) - 120V:1027472 : M_Troffer Light - Parabolic Square control rooms:0600x0600mm(2 Lamp) - 120V:1027472:323598, M_Troffer Light - Parabolic Square control rooms:0600x0600mm(2 Lamp) - 120V:1027472:0600x0600mm(2 Lamp) - 120V:1027472 : M_Troffer Light - Parabolic Square control rooms:0600x0600mm(2 Lamp) - 120V:1027472:323598:0600x0600mm(2 Lamp) - 120V:1027472:0600x0600mm(2 Lamp) - 120V:1027472 : M_Troffer Light - Parabolic Square control rooms:0600x0600mm(2 Lamp) - 120V:1027472:323598 : M_Troffer Light - Parabolic Square control rooms:0600x0600mm(2 Lamp) - 120V:1027472:0600x0600mm(2 Lamp) - 120V:1027472 : M_Troffer Light - Parabolic Square control rooms:0600x0600mm(2 Lamp) - 120V:1027472:323598:323196
In: Level 1
Type - Material: Glass, White, High Luminance (2), Steel, Chrome Plated 155972 (2)
Type - Pset_DistributionFlowElementCommon - Reference: 0600x0600mm(2 Lamp) - 120V
Type - Pset_ProductRequirements - Category: Lighting Fixtures
Type - Pset_QuantityTakeOff - Reference: 0600x0600mm(2 Lamp) - 120V
Pset_DistributionFlowElementCommon - sets with these values: 2

# IfcFlowTerminal: M_Troffer Light - Parabolic Square control rooms:0600x0600mm(2 Lamp) - 120V:1027473:0600x0600mm(2 Lamp) - 120V:1027473 : M_Troffer Light - Parabolic Square control rooms:0600x0600mm(2 Lamp) - 120V:1027473:323637, M_Troffer Light - Parabolic Square control rooms:0600x0600mm(2 Lamp) - 120V:1027473:0600x0600mm(2 Lamp) - 120V:1027473 : M_Troffer Light - Parabolic Square control rooms:0600x0600mm(2 Lamp) - 120V:1027473:323637:0600x0600mm(2 Lamp) - 120V:1027473:0600x0600mm(2 Lamp) - 120V:1027473 : M_Troffer Light - Parabolic Square control rooms:0600x0600mm(2 Lamp) - 120V:1027473:323637 : M_Troffer Light - Parabolic Square control rooms:0600x0600mm(2 Lamp) - 120V:1027473:0600x0600mm(2 Lamp) - 120V:1027473 : M_Troffer Light - Parabolic Square control rooms:0600x0600mm(2 Lamp) - 120V:1027473:323637:323235
In: Level 1
Type - Material: Glass, White, High Luminance (2), Steel, Chrome Plated 155972 (2)
Type - Pset_DistributionFlowElementCommon - Reference: 0600x0600mm(2 Lamp) - 120V
Type - Pset_ProductRequirements - Category: Lighting Fixtures
Type - Pset_QuantityTakeOff - Reference: 0600x0600mm(2 Lamp) - 120V
Pset_DistributionFlowElementCommon - sets with these values: 2

# IfcFlowTerminal: M_Troffer Light - Parabolic Square control rooms:0600x0600mm(2 Lamp) - 120V:1027474:0600x0600mm(2 Lamp) - 120V:1027474 : M_Troffer Light - Parabolic Square control rooms:0600x0600mm(2 Lamp) - 120V:1027474:323676, M_Troffer Light - Parabolic Square control rooms:0600x0600mm(2 Lamp) - 120V:1027474:0600x0600mm(2 Lamp) - 120V:1027474 : M_Troffer Light - Parabolic Square control rooms:0600x0600mm(2 Lamp) - 120V:1027474:323676:0600x0600mm(2 Lamp) - 120V:1027474:0600x0600mm(2 Lamp) - 120V:1027474 : M_Troffer Light - Parabolic Square control rooms:0600x0600mm(2 Lamp) - 120V:1027474:323676 : M_Troffer Light - Parabolic Square control rooms:0600x0600mm(2 Lamp) - 120V:1027474:0600x0600mm(2 Lamp) - 120V:1027474 : M_Troffer Light - Parabolic Square control rooms:0600x0600mm(2 Lamp) - 120V:1027474:323676:323274
In: Level 1
Type - Material: Glass, White, High Luminance (2), Steel, Chrome Plated 155972 (2)
Type - Pset_DistributionFlowElementCommon - Reference: 0600x0600mm(2 Lamp) - 120V
Type - Pset_ProductRequirements - Category: Lighting Fixtures
Type - Pset_QuantityTakeOff - Reference: 0600x0600mm(2 Lamp) - 120V
Pset_DistributionFlowElementCommon - sets with these values: 2

# IfcFlowTerminal: M_Troffer Light - Parabolic Square control rooms:0600x0600mm(2 Lamp) - 120V:1027475:0600x0600mm(2 Lamp) - 120V:1027475 : M_Troffer Light - Parabolic Square control rooms:0600x0600mm(2 Lamp) - 120V:1027475:325565, M_Troffer Light - Parabolic Square control rooms:0600x0600mm(2 Lamp) - 120V:1027475:0600x0600mm(2 Lamp) - 120V:1027475 : M_Troffer Light - Parabolic Square control rooms:0600x0600mm(2 Lamp) - 120V:1027475:325565:0600x0600mm(2 Lamp) - 120V:1027475:0600x0600mm(2 Lamp) - 120V:1027475 : M_Troffer Light - Parabolic Square control rooms:0600x0600mm(2 Lamp) - 120V:1027475:325565 : M_Troffer Light - Parabolic Square control rooms:0600x0600mm(2 Lamp) - 120V:1027475:0600x0600mm(2 Lamp) - 120V:1027475 : M_Troffer Light - Parabolic Square control rooms:0600x0600mm(2 Lamp) - 120V:1027475:325565:324341
In: Level 1
Type - Material: Glass, White, High Luminance (2), Steel, Chrome Plated 155972 (2)
Type - Pset_DistributionFlowElementCommon - Reference: 0600x0600mm(2 Lamp) - 120V
Type - Pset_ProductRequirements - Category: Lighting Fixtures
Type - Pset_QuantityTakeOff - Reference: 0600x0600mm(2 Lamp) - 120V
Pset_DistributionFlowElementCommon - sets with these values: 2

# IfcFlowTerminal: M_Troffer Light - Parabolic Square control rooms:0600x0600mm(2 Lamp) - 120V:1027476:0600x0600mm(2 Lamp) - 120V:1027476 : M_Troffer Light - Parabolic Square control rooms:0600x0600mm(2 Lamp) - 120V:1027476:325604, M_Troffer Light - Parabolic Square control rooms:0600x0600mm(2 Lamp) - 120V:1027476:0600x0600mm(2 Lamp) - 120V:1027476 : M_Troffer Light - Parabolic Square control rooms:0600x0600mm(2 Lamp) - 120V:1027476:325604:0600x0600mm(2 Lamp) - 120V:1027476:0600x0600mm(2 Lamp) - 120V:1027476 : M_Troffer Light - Parabolic Square control rooms:0600x0600mm(2 Lamp) - 120V:1027476:325604 : M_Troffer Light - Parabolic Square control rooms:0600x0600mm(2 Lamp) - 120V:1027476:0600x0600mm(2 Lamp) - 120V:1027476 : M_Troffer Light - Parabolic Square control rooms:0600x0600mm(2 Lamp) - 120V:1027476:325604:324380
In: Level 1
Type - Material: Glass, White, High Luminance (2), Steel, Chrome Plated 155972 (2)
Type - Pset_DistributionFlowElementCommon - Reference: 0600x0600mm(2 Lamp) - 120V
Type - Pset_ProductRequirements - Category: Lighting Fixtures
Type - Pset_QuantityTakeOff - Reference: 0600x0600mm(2 Lamp) - 120V
Pset_DistributionFlowElementCommon - sets with these values: 2

# IfcFlowTerminal: M_Troffer Light - Parabolic Square control rooms:0600x0600mm(2 Lamp) - 120V:1027477:0600x0600mm(2 Lamp) - 120V:1027477 : M_Troffer Light - Parabolic Square control rooms:0600x0600mm(2 Lamp) - 120V:1027477:325643, M_Troffer Light - Parabolic Square control rooms:0600x0600mm(2 Lamp) - 120V:1027477:0600x0600mm(2 Lamp) - 120V:1027477 : M_Troffer Light - Parabolic Square control rooms:0600x0600mm(2 Lamp) - 120V:1027477:325643:0600x0600mm(2 Lamp) - 120V:1027477:0600x0600mm(2 Lamp) - 120V:1027477 : M_Troffer Light - Parabolic Square control rooms:0600x0600mm(2 Lamp) - 120V:1027477:325643 : M_Troffer Light - Parabolic Square control rooms:0600x0600mm(2 Lamp) - 120V:1027477:0600x0600mm(2 Lamp) - 120V:1027477 : M_Troffer Light - Parabolic Square control rooms:0600x0600mm(2 Lamp) - 120V:1027477:325643:324419
In: Level 1
Type - Material: Glass, White, High Luminance (2), Steel, Chrome Plated 155972 (2)
Type - Pset_DistributionFlowElementCommon - Reference: 0600x0600mm(2 Lamp) - 120V
Type - Pset_ProductRequirements - Category: Lighting Fixtures
Type - Pset_QuantityTakeOff - Reference: 0600x0600mm(2 Lamp) - 120V
Pset_DistributionFlowElementCommon - sets with these values: 2

# IfcFlowTerminal: M_Troffer Light - Parabolic Square control rooms:0600x0600mm(2 Lamp) - 120V:1027478:0600x0600mm(2 Lamp) - 120V:1027478 : M_Troffer Light - Parabolic Square control rooms:0600x0600mm(2 Lamp) - 120V:1027478:325682, M_Troffer Light - Parabolic Square control rooms:0600x0600mm(2 Lamp) - 120V:1027478:0600x0600mm(2 Lamp) - 120V:1027478 : M_Troffer Light - Parabolic Square control rooms:0600x0600mm(2 Lamp) - 120V:1027478:325682:0600x0600mm(2 Lamp) - 120V:1027478:0600x0600mm(2 Lamp) - 120V:1027478 : M_Troffer Light - Parabolic Square control rooms:0600x0600mm(2 Lamp) - 120V:1027478:325682 : M_Troffer Light - Parabolic Square control rooms:0600x0600mm(2 Lamp) - 120V:1027478:0600x0600mm(2 Lamp) - 120V:1027478 : M_Troffer Light - Parabolic Square control rooms:0600x0600mm(2 Lamp) - 120V:1027478:325682:324458
In: Level 1
Type - Material: Glass, White, High Luminance (2), Steel, Chrome Plated 155972 (2)
Type - Pset_DistributionFlowElementCommon - Reference: 0600x0600mm(2 Lamp) - 120V
Type - Pset_ProductRequirements - Category: Lighting Fixtures
Type - Pset_QuantityTakeOff - Reference: 0600x0600mm(2 Lamp) - 120V
Pset_DistributionFlowElementCommon - sets with these values: 2

# IfcFlowTerminal: M_Troffer Light - Parabolic Square control rooms:0600x0600mm(2 Lamp) - 120V:1027479:0600x0600mm(2 Lamp) - 120V:1027479 : M_Troffer Light - Parabolic Square control rooms:0600x0600mm(2 Lamp) - 120V:1027479:325721, M_Troffer Light - Parabolic Square control rooms:0600x0600mm(2 Lamp) - 120V:1027479:0600x0600mm(2 Lamp) - 120V:1027479 : M_Troffer Light - Parabolic Square control rooms:0600x0600mm(2 Lamp) - 120V:1027479:325721:0600x0600mm(2 Lamp) - 120V:1027479:0600x0600mm(2 Lamp) - 120V:1027479 : M_Troffer Light - Parabolic Square control rooms:0600x0600mm(2 Lamp) - 120V:1027479:325721 : M_Troffer Light - Parabolic Square control rooms:0600x0600mm(2 Lamp) - 120V:1027479:0600x0600mm(2 Lamp) - 120V:1027479 : M_Troffer Light - Parabolic Square control rooms:0600x0600mm(2 Lamp) - 120V:1027479:325721:324497
In: Level 1
Type - Material: Glass, White, High Luminance (2), Steel, Chrome Plated 155972 (2)
Type - Pset_DistributionFlowElementCommon - Reference: 0600x0600mm(2 Lamp) - 120V
Type - Pset_ProductRequirements - Category: Lighting Fixtures
Type - Pset_QuantityTakeOff - Reference: 0600x0600mm(2 Lamp) - 120V
Pset_DistributionFlowElementCommon - sets with these values: 2

# IfcFlowTerminal: M_Troffer Light - Parabolic Square control rooms:0600x0600mm(2 Lamp) - 120V:1027480:0600x0600mm(2 Lamp) - 120V:1027480 : M_Troffer Light - Parabolic Square control rooms:0600x0600mm(2 Lamp) - 120V:1027480:325760, M_Troffer Light - Parabolic Square control rooms:0600x0600mm(2 Lamp) - 120V:1027480:0600x0600mm(2 Lamp) - 120V:1027480 : M_Troffer Light - Parabolic Square control rooms:0600x0600mm(2 Lamp) - 120V:1027480:325760:0600x0600mm(2 Lamp) - 120V:1027480:0600x0600mm(2 Lamp) - 120V:1027480 : M_Troffer Light - Parabolic Square control rooms:0600x0600mm(2 Lamp) - 120V:1027480:325760 : M_Troffer Light - Parabolic Square control rooms:0600x0600mm(2 Lamp) - 120V:1027480:0600x0600mm(2 Lamp) - 120V:1027480 : M_Troffer Light - Parabolic Square control rooms:0600x0600mm(2 Lamp) - 120V:1027480:325760:324536
In: Level 1
Type - Material: Glass, White, High Luminance (2), Steel, Chrome Plated 155972 (2)
Type - Pset_DistributionFlowElementCommon - Reference: 0600x0600mm(2 Lamp) - 120V
Type - Pset_ProductRequirements - Category: Lighting Fixtures
Type - Pset_QuantityTakeOff - Reference: 0600x0600mm(2 Lamp) - 120V
Pset_DistributionFlowElementCommon - sets with these values: 2

# IfcFlowTerminal: M_Troffer Light - Parabolic Square control rooms:0600x0600mm(2 Lamp) - 120V:1027481:0600x0600mm(2 Lamp) - 120V:1027481 : M_Troffer Light - Parabolic Square control rooms:0600x0600mm(2 Lamp) - 120V:1027481:325799, M_Troffer Light - Parabolic Square control rooms:0600x0600mm(2 Lamp) - 120V:1027481:0600x0600mm(2 Lamp) - 120V:1027481 : M_Troffer Light - Parabolic Square control rooms:0600x0600mm(2 Lamp) - 120V:1027481:325799:0600x0600mm(2 Lamp) - 120V:1027481:0600x0600mm(2 Lamp) - 120V:1027481 : M_Troffer Light - Parabolic Square control rooms:0600x0600mm(2 Lamp) - 120V:1027481:325799 : M_Troffer Light - Parabolic Square control rooms:0600x0600mm(2 Lamp) - 120V:1027481:0600x0600mm(2 Lamp) - 120V:1027481 : M_Troffer Light - Parabolic Square control rooms:0600x0600mm(2 Lamp) - 120V:1027481:325799:324575
In: Level 1
Type - Material: Glass, White, High Luminance (2), Steel, Chrome Plated 155972 (2)
Type - Pset_DistributionFlowElementCommon - Reference: 0600x0600mm(2 Lamp) - 120V
Type - Pset_ProductRequirements - Category: Lighting Fixtures
Type - Pset_QuantityTakeOff - Reference: 0600x0600mm(2 Lamp) - 120V
Pset_DistributionFlowElementCommon - sets with these values: 2

# IfcFlowTerminal: M_Troffer Light - Parabolic Square control rooms:0600x0600mm(2 Lamp) - 120V:1027483:0600x0600mm(2 Lamp) - 120V:1027483 : M_Troffer Light - Parabolic Square control rooms:0600x0600mm(2 Lamp) - 120V:1027483:325838, M_Troffer Light - Parabolic Square control rooms:0600x0600mm(2 Lamp) - 120V:1027483:0600x0600mm(2 Lamp) - 120V:1027483 : M_Troffer Light - Parabolic Square control rooms:0600x0600mm(2 Lamp) - 120V:1027483:325838:0600x0600mm(2 Lamp) - 120V:1027483:0600x0600mm(2 Lamp) - 120V:1027483 : M_Troffer Light - Parabolic Square control rooms:0600x0600mm(2 Lamp) - 120V:1027483:325838 : M_Troffer Light - Parabolic Square control rooms:0600x0600mm(2 Lamp) - 120V:1027483:0600x0600mm(2 Lamp) - 120V:1027483 : M_Troffer Light - Parabolic Square control rooms:0600x0600mm(2 Lamp) - 120V:1027483:325838:324614
In: Level 1
Type - Material: Glass, White, High Luminance (2), Steel, Chrome Plated 155972 (2)
Type - Pset_DistributionFlowElementCommon - Reference: 0600x0600mm(2 Lamp) - 120V
Type - Pset_ProductRequirements - Category: Lighting Fixtures
Type - Pset_QuantityTakeOff - Reference: 0600x0600mm(2 Lamp) - 120V
Pset_DistributionFlowElementCommon - sets with these values: 2

# IfcFlowTerminal: M_Troffer Light - Parabolic Square control rooms:0600x0600mm(2 Lamp) - 120V:1027490:0600x0600mm(2 Lamp) - 120V:1027490 : M_Troffer Light - Parabolic Square control rooms:0600x0600mm(2 Lamp) - 120V:1027490:327948, M_Troffer Light - Parabolic Square control rooms:0600x0600mm(2 Lamp) - 120V:1027490:0600x0600mm(2 Lamp) - 120V:1027490 : M_Troffer Light - Parabolic Square control rooms:0600x0600mm(2 Lamp) - 120V:1027490:327948:0600x0600mm(2 Lamp) - 120V:1027490:0600x0600mm(2 Lamp) - 120V:1027490 : M_Troffer Light - Parabolic Square control rooms:0600x0600mm(2 Lamp) - 120V:1027490:327948 : M_Troffer Light - Parabolic Square control rooms:0600x0600mm(2 Lamp) - 120V:1027490:0600x0600mm(2 Lamp) - 120V:1027490 : M_Troffer Light - Parabolic Square control rooms:0600x0600mm(2 Lamp) - 120V:1027490:327948:326943
In: Level 2
Type - Material: Glass, White, High Luminance (2), Steel, Chrome Plated 155972 (2)
Type - Pset_DistributionFlowElementCommon - Reference: 0600x0600mm(2 Lamp) - 120V
Type - Pset_ProductRequirements - Category: Lighting Fixtures
Type - Pset_QuantityTakeOff - Reference: 0600x0600mm(2 Lamp) - 120V
Pset_DistributionFlowElementCommon - sets with these values: 2

# IfcFlowTerminal: M_Troffer Light - Parabolic Square control rooms:0600x0600mm(2 Lamp) - 120V:1027491:0600x0600mm(2 Lamp) - 120V:1027491 : M_Troffer Light - Parabolic Square control rooms:0600x0600mm(2 Lamp) - 120V:1027491:327987, M_Troffer Light - Parabolic Square control rooms:0600x0600mm(2 Lamp) - 120V:1027491:0600x0600mm(2 Lamp) - 120V:1027491 : M_Troffer Light - Parabolic Square control rooms:0600x0600mm(2 Lamp) - 120V:1027491:327987:0600x0600mm(2 Lamp) - 120V:1027491:0600x0600mm(2 Lamp) - 120V:1027491 : M_Troffer Light - Parabolic Square control rooms:0600x0600mm(2 Lamp) - 120V:1027491:327987 : M_Troffer Light - Parabolic Square control rooms:0600x0600mm(2 Lamp) - 120V:1027491:0600x0600mm(2 Lamp) - 120V:1027491 : M_Troffer Light - Parabolic Square control rooms:0600x0600mm(2 Lamp) - 120V:1027491:327987:326982
In: Level 2
Type - Material: Glass, White, High Luminance (2), Steel, Chrome Plated 155972 (2)
Type - Pset_DistributionFlowElementCommon - Reference: 0600x0600mm(2 Lamp) - 120V
Type - Pset_ProductRequirements - Category: Lighting Fixtures
Type - Pset_QuantityTakeOff - Reference: 0600x0600mm(2 Lamp) - 120V
Pset_DistributionFlowElementCommon - sets with these values: 2

# IfcFlowTerminal: M_Troffer Light - Parabolic Square control rooms:0600x0600mm(2 Lamp) - 120V:1027492:0600x0600mm(2 Lamp) - 120V:1027492 : M_Troffer Light - Parabolic Square control rooms:0600x0600mm(2 Lamp) - 120V:1027492:328026, M_Troffer Light - Parabolic Square control rooms:0600x0600mm(2 Lamp) - 120V:1027492:0600x0600mm(2 Lamp) - 120V:1027492 : M_Troffer Light - Parabolic Square control rooms:0600x0600mm(2 Lamp) - 120V:1027492:328026:0600x0600mm(2 Lamp) - 120V:1027492:0600x0600mm(2 Lamp) - 120V:1027492 : M_Troffer Light - Parabolic Square control rooms:0600x0600mm(2 Lamp) - 120V:1027492:328026 : M_Troffer Light - Parabolic Square control rooms:0600x0600mm(2 Lamp) - 120V:1027492:0600x0600mm(2 Lamp) - 120V:1027492 : M_Troffer Light - Parabolic Square control rooms:0600x0600mm(2 Lamp) - 120V:1027492:328026:327021
In: Level 2
Type - Material: Glass, White, High Luminance (2), Steel, Chrome Plated 155972 (2)
Type - Pset_DistributionFlowElementCommon - Reference: 0600x0600mm(2 Lamp) - 120V
Type - Pset_ProductRequirements - Category: Lighting Fixtures
Type - Pset_QuantityTakeOff - Reference: 0600x0600mm(2 Lamp) - 120V
Pset_DistributionFlowElementCommon - sets with these values: 2

# IfcFlowTerminal: M_Troffer Light - Parabolic Square control rooms:0600x0600mm(2 Lamp) - 120V:1027493:0600x0600mm(2 Lamp) - 120V:1027493 : M_Troffer Light - Parabolic Square control rooms:0600x0600mm(2 Lamp) - 120V:1027493:328065, M_Troffer Light - Parabolic Square control rooms:0600x0600mm(2 Lamp) - 120V:1027493:0600x0600mm(2 Lamp) - 120V:1027493 : M_Troffer Light - Parabolic Square control rooms:0600x0600mm(2 Lamp) - 120V:1027493:328065:0600x0600mm(2 Lamp) - 120V:1027493:0600x0600mm(2 Lamp) - 120V:1027493 : M_Troffer Light - Parabolic Square control rooms:0600x0600mm(2 Lamp) - 120V:1027493:328065 : M_Troffer Light - Parabolic Square control rooms:0600x0600mm(2 Lamp) - 120V:1027493:0600x0600mm(2 Lamp) - 120V:1027493 : M_Troffer Light - Parabolic Square control rooms:0600x0600mm(2 Lamp) - 120V:1027493:328065:327060
In: Level 2
Type - Material: Glass, White, High Luminance (2), Steel, Chrome Plated 155972 (2)
Type - Pset_DistributionFlowElementCommon - Reference: 0600x0600mm(2 Lamp) - 120V
Type - Pset_ProductRequirements - Category: Lighting Fixtures
Type - Pset_QuantityTakeOff - Reference: 0600x0600mm(2 Lamp) - 120V
Pset_DistributionFlowElementCommon - sets with these values: 2

# IfcFlowTerminal: M_Troffer Light - Parabolic Square control rooms:0600x0600mm(2 Lamp) - 120V:1027494:0600x0600mm(2 Lamp) - 120V:1027494 : M_Troffer Light - Parabolic Square control rooms:0600x0600mm(2 Lamp) - 120V:1027494:328104, M_Troffer Light - Parabolic Square control rooms:0600x0600mm(2 Lamp) - 120V:1027494:0600x0600mm(2 Lamp) - 120V:1027494 : M_Troffer Light - Parabolic Square control rooms:0600x0600mm(2 Lamp) - 120V:1027494:328104:0600x0600mm(2 Lamp) - 120V:1027494:0600x0600mm(2 Lamp) - 120V:1027494 : M_Troffer Light - Parabolic Square control rooms:0600x0600mm(2 Lamp) - 120V:1027494:328104 : M_Troffer Light - Parabolic Square control rooms:0600x0600mm(2 Lamp) - 120V:1027494:0600x0600mm(2 Lamp) - 120V:1027494 : M_Troffer Light - Parabolic Square control rooms:0600x0600mm(2 Lamp) - 120V:1027494:328104:327099
In: Level 2
Type - Material: Glass, White, High Luminance (2), Steel, Chrome Plated 155972 (2)
Type - Pset_DistributionFlowElementCommon - Reference: 0600x0600mm(2 Lamp) - 120V
Type - Pset_ProductRequirements - Category: Lighting Fixtures
Type - Pset_QuantityTakeOff - Reference: 0600x0600mm(2 Lamp) - 120V
Pset_DistributionFlowElementCommon - sets with these values: 2

# IfcFlowTerminal: M_Troffer Light - Parabolic Square control rooms:0600x0600mm(2 Lamp) - 120V:1027495:0600x0600mm(2 Lamp) - 120V:1027495 : M_Troffer Light - Parabolic Square control rooms:0600x0600mm(2 Lamp) - 120V:1027495:328143, M_Troffer Light - Parabolic Square control rooms:0600x0600mm(2 Lamp) - 120V:1027495:0600x0600mm(2 Lamp) - 120V:1027495 : M_Troffer Light - Parabolic Square control rooms:0600x0600mm(2 Lamp) - 120V:1027495:328143:0600x0600mm(2 Lamp) - 120V:1027495:0600x0600mm(2 Lamp) - 120V:1027495 : M_Troffer Light - Parabolic Square control rooms:0600x0600mm(2 Lamp) - 120V:1027495:328143 : M_Troffer Light - Parabolic Square control rooms:0600x0600mm(2 Lamp) - 120V:1027495:0600x0600mm(2 Lamp) - 120V:1027495 : M_Troffer Light - Parabolic Square control rooms:0600x0600mm(2 Lamp) - 120V:1027495:328143:327138
In: Level 2
Type - Material: Glass, White, High Luminance (2), Steel, Chrome Plated 155972 (2)
Type - Pset_DistributionFlowElementCommon - Reference: 0600x0600mm(2 Lamp) - 120V
Type - Pset_ProductRequirements - Category: Lighting Fixtures
Type - Pset_QuantityTakeOff - Reference: 0600x0600mm(2 Lamp) - 120V
Pset_DistributionFlowElementCommon - sets with these values: 2

# IfcFlowTerminal: M_Troffer Light - Parabolic Square control rooms:0600x0600mm(2 Lamp) - 120V:1027496:0600x0600mm(2 Lamp) - 120V:1027496 : M_Troffer Light - Parabolic Square control rooms:0600x0600mm(2 Lamp) - 120V:1027496:328182, M_Troffer Light - Parabolic Square control rooms:0600x0600mm(2 Lamp) - 120V:1027496:0600x0600mm(2 Lamp) - 120V:1027496 : M_Troffer Light - Parabolic Square control rooms:0600x0600mm(2 Lamp) - 120V:1027496:328182:0600x0600mm(2 Lamp) - 120V:1027496:0600x0600mm(2 Lamp) - 120V:1027496 : M_Troffer Light - Parabolic Square control rooms:0600x0600mm(2 Lamp) - 120V:1027496:328182 : M_Troffer Light - Parabolic Square control rooms:0600x0600mm(2 Lamp) - 120V:1027496:0600x0600mm(2 Lamp) - 120V:1027496 : M_Troffer Light - Parabolic Square control rooms:0600x0600mm(2 Lamp) - 120V:1027496:328182:327177
In: Level 2
Type - Material: Glass, White, High Luminance (2), Steel, Chrome Plated 155972 (2)
Type - Pset_DistributionFlowElementCommon - Reference: 0600x0600mm(2 Lamp) - 120V
Type - Pset_ProductRequirements - Category: Lighting Fixtures
Type - Pset_QuantityTakeOff - Reference: 0600x0600mm(2 Lamp) - 120V
Pset_DistributionFlowElementCommon - sets with these values: 2

# IfcFlowTerminal: M_Troffer Light - Parabolic Square control rooms:0600x0600mm(2 Lamp) - 120V:1027497:0600x0600mm(2 Lamp) - 120V:1027497 : M_Troffer Light - Parabolic Square control rooms:0600x0600mm(2 Lamp) - 120V:1027497:328221, M_Troffer Light - Parabolic Square control rooms:0600x0600mm(2 Lamp) - 120V:1027497:0600x0600mm(2 Lamp) - 120V:1027497 : M_Troffer Light - Parabolic Square control rooms:0600x0600mm(2 Lamp) - 120V:1027497:328221:0600x0600mm(2 Lamp) - 120V:1027497:0600x0600mm(2 Lamp) - 120V:1027497 : M_Troffer Light - Parabolic Square control rooms:0600x0600mm(2 Lamp) - 120V:1027497:328221 : M_Troffer Light - Parabolic Square control rooms:0600x0600mm(2 Lamp) - 120V:1027497:0600x0600mm(2 Lamp) - 120V:1027497 : M_Troffer Light - Parabolic Square control rooms:0600x0600mm(2 Lamp) - 120V:1027497:328221:327216
In: Level 2
Type - Material: Glass, White, High Luminance (2), Steel, Chrome Plated 155972 (2)
Type - Pset_DistributionFlowElementCommon - Reference: 0600x0600mm(2 Lamp) - 120V
Type - Pset_ProductRequirements - Category: Lighting Fixtures
Type - Pset_QuantityTakeOff - Reference: 0600x0600mm(2 Lamp) - 120V
Pset_DistributionFlowElementCommon - sets with these values: 2

# IfcOpeningElement: Opening (42)
Pset_OpeningElementCommon - sets with these values: 2
Name | In | Reference | Category
6 x Basic Wall:My exterior wall 280mm:1026547 | Level 2 | Basic Wall:Basic Wall:My exterior wall 280mm | Walls: Rectangular Straight Wall Opening
Basic Wall:My exterior wall HALL 220 mm:1026508 | Level 1 | Basic Wall:Basic Wall:My exterior wall HALL 220 mm | Walls: Rectangular Straight Wall Opening
Basic Wall:My exterior wall HALL 220 mm:1026507 | Level 1 | Basic Wall:Basic Wall:My exterior wall HALL 220 mm | Walls: Rectangular Straight Wall Opening
Basic Wall:My interior wall 80mm:1026527 | Level 1 | Basic Wall:Basic Wall:My interior wall 80mm | Walls: Rectangular Straight Wall Opening
Basic Wall:My interior wall 80mm:1026528 | Level 1 | Basic Wall:Basic Wall:My interior wall 80mm | Walls: Rectangular Straight Wall Opening
2 x Basic Wall:My interior wall 80mm:1026529 | Level 1 | Basic Wall:Basic Wall:My interior wall 80mm | Walls: Rectangular Straight Wall Opening
7 x Basic Wall:My exterior wall 280mm:1026545 | Level 2 | Basic Wall:Basic Wall:My exterior wall 280mm | Walls: Rectangular Straight Wall Opening
3 x Basic Wall:My exterior wall 280mm:1026546 | Level 2 | Basic Wall:Basic Wall:My exterior wall 280mm | Walls: Rectangular Straight Wall Opening
4 x Basic Wall:My exterior wall 280mm:1026548 | Level 2 | Basic Wall:Basic Wall:My exterior wall 280mm | Walls: Rectangular Straight Wall Opening
Basic Wall:My interior wall 80mm:1026549 | Level 2 | Basic Wall:Basic Wall:My interior wall 80mm | Walls: Rectangular Straight Wall Opening
Basic Wall:My interior wall 80mm:1026552 | Level 2 | Basic Wall:Basic Wall:My interior wall 80mm | Walls: Rectangular Straight Wall Opening
Basic Wall:My interior wall 80mm:1026553 | Level 2 | Basic Wall:Basic Wall:My interior wall 80mm | Walls: Rectangular Straight Wall Opening
Basic Wall:My interior wall 80mm:1026661 | Level 1 | Basic Wall:Basic Wall:My interior wall 80mm | Walls: Rectangular Straight Wall Opening
Basic Wall:My interior wall 80mm:1026665 | Level 1 | Basic Wall:Basic Wall:My interior wall 80mm | Walls: Rectangular Straight Wall Opening
Basic Wall:My interior wall 80mm:1026668 | Level 2 | Basic Wall:Basic Wall:My interior wall 80mm | Walls: Rectangular Straight Wall Opening
Basic Wall:My interior wall 80mm:1026670 | Level 2 | Basic Wall:Basic Wall:My interior wall 80mm | Walls: Rectangular Straight Wall Opening
3 x Basic Wall:My exterior wall 280mm:1026675 | Level 1 | Basic Wall:Basic Wall:My exterior wall 280mm | Walls: Rectangular Straight Wall Opening
2 x Basic Wall:My exterior wall 280mm:1027070 | Level 1 | Basic Wall:Basic Wall:My exterior wall 280mm | Walls: Rectangular Straight Wall Opening
3 x Basic Wall:My exterior wall 280mm:1027299 | Level 1 | Basic Wall:Basic Wall:My exterior wall 280mm | Walls: Rectangular Straight Wall Opening
Floor:Floor:Floor:My first floor:336751:2 | Level 2 | Floor:Floor:My first floor | Floors

# IfcRailing: Railing:Construction_Railing_Faraone_NINFA-5_Tempered-Glass 10+10:1027437:Construction_Railing_Faraone_NINFA-5_Tempered-Glass 10+10:1027437 : Railing:Construction_Railing_Faraone_NINFA-5_Tempered-Glass 10+10:1027437:327621, Railing:Construction_Railing_Faraone_NINFA-5_Tempered-Glass 10+10:1027437:Construction_Railing_Faraone_NINFA-5_Tempered-Glass 10+10:1027437 : Railing:Construction_Railing_Faraone_NINFA-5_Tempered-Glass 10+10:1027437:327621:Construction_Railing_Faraone_NINFA-5_Tempered-Glass 10+10:1027437:Construction_Railing_Faraone_NINFA-5_Tempered-Glass 10+10:1027437 : Railing:Construction_Railing_Faraone_NINFA-5_Tempered-Glass 10+10:1027437:327621 : Railing:Construction_Railing_Faraone_NINFA-5_Tempered-Glass 10+10:1027437:Construction_Railing_Faraone_NINFA-5_Tempered-Glass 10+10:1027437 : Railing:Construction_Railing_Faraone_NINFA-5_Tempered-Glass 10+10:1027437:327621:327796
In: Level 2
Type - Material: Glass, Clear Glazing, Aluminum 6061-O
Type - Pset_ManufacturerTypeInformation - Manufacturer: Faraone srl - Architetture Trasparenti - Via Po, 12 – 64018 Tortoreto Lido TE
Type - Pset_ProductRequirements - Category: Railings
Type - Pset_QuantityTakeOff - Reference: Construction_Railing_Faraone_NINFA-5_Tempered-Glass 10+10
Type - Pset_RailingCommon - IsExternal: no; Reference: Construction_Railing_Faraone_NINFA-5_Tempered-Glass 10+10; Height: 900 mm

# IfcRailing: Railing:My railing 120 mm:1027140:My railing 120 mm:1027140 : Railing:My railing 120 mm:1027140:327531, Railing:My railing 120 mm:1027140:My railing 120 mm:1027140 : Railing:My railing 120 mm:1027140:327531:My railing 120 mm:1027140:My railing 120 mm:1027140 : Railing:My railing 120 mm:1027140:327531 : Railing:My railing 120 mm:1027140:My railing 120 mm:1027140 : Railing:My railing 120 mm:1027140:327531:327726
In: Level 2
Type - Material: Metal Deck (8)
Type - Pset_ProductRequirements - Category: Railings
Type - Pset_QuantityTakeOff - Reference: My railing 120 mm
Type - Pset_RailingCommon - IsExternal: no; Reference: My railing 120 mm; Height: 1200 mm

# IfcRoof: Basic Roof:Cold Roof - MY Roof:1027052:Cold Roof - MY Roof:1027052 : Basic Roof:Cold Roof - MY Roof:1027052:329143:1:Cold Roof - MY Roof:1027052:Cold Roof - MY Roof:1027052 : Basic Roof:Cold Roof - MY Roof:1027052:329143:1 : Basic Roof:Cold Roof - MY Roof:1027052:Cold Roof - MY Roof:1027052 : Basic Roof:Cold Roof - MY Roof:1027052:329143:1, Basic Roof:Cold Roof - MY Roof:1027052:Cold Roof - MY Roof:1027052 : Basic Roof:Cold Roof - MY Roof:1027052:329143:1:Cold Roof - MY Roof:1027052:Cold Roof - MY Roof:1027052 : Basic Roof:Cold Roof - MY Roof:1027052:329143:1 : Basic Roof:Cold Roof - MY Roof:1027052:Cold Roof - MY Roof:1027052 : Basic Roof:Cold Roof - MY Roof:1027052:329143:1:327700
In: Level 2
Material: ashpalt waterproofing membrane (SBS)
Pset_ProductRequirements - Category: Roofs
Pset_QuantityTakeOff - Reference: Cold Roof - MY Roof
Pset_RoofCommon - IsExternal: yes; Reference: Cold Roof - MY Roof; TotalArea: 143.865 m2

# IfcSlab: Basic Roof:Cold Roof - MY Roof:1027052:Cold Roof - MY Roof:1027052 : Basic Roof:Cold Roof - MY Roof:1027052:329143:1, Basic Roof:Cold Roof - MY Roof:1027052:Cold Roof - MY Roof:1027052 : Basic Roof:Cold Roof - MY Roof:1027052:329143:1:Cold Roof - MY Roof:1027052:Cold Roof - MY Roof:1027052 : Basic Roof:Cold Roof - MY Roof:1027052:329143:1 : Basic Roof:Cold Roof - MY Roof:1027052:Cold Roof - MY Roof:1027052 : Basic Roof:Cold Roof - MY Roof:1027052:329143:1:327700:1
In: Level 2
Type - PredefinedType: ROOF
Type - Pset_ProductRequirements - Category: Roofs
Type - Pset_QuantityTakeOff - Reference: Cold Roof - MY Roof
Type - Pset_ReinforcementBarPitchOfSlab - Reference: Cold Roof - MY Roof
Type - Pset_SlabCommon - IsExternal: yes; Reference: Cold Roof - MY Roof; PitchAngle: 0 deg; ThermalTransmittance: 0.334267 kg/K/s3
Pset_QuantityTakeOff - sets with these values: 2

# IfcSlab: Floor:Floor:Floor:Concrete-Domestic My floor, Floor:Floor:Floor:Concrete-Domestic My floor:336739
In: Level 1
Type - PredefinedType: FLOOR; Material: Ceramic tiles 5 mm, cement mortar 50 mm, Reinforced Concrete 2% 150 mm, FIBRAN xps seismic 400 50 mm, FIBRAN xps seismic 400 50 mm
Type - Pset_ElementShading - Roughness: 304.8 mm
Type - Pset_ProductRequirements - Category: Floors
Type - Pset_SlabCommon - IsExternal: no; ThermalTransmittance: 4.60799 kg/K/s3
Pset_QuantityTakeOff - Reference: Floor:Floor:Concrete-Domestic My floor; sets with these values: 2
Pset_SlabCommon - LoadBearing: no; PitchAngle: 0 deg; Reference: Floor:Floor:Concrete-Domestic My floor

# IfcSlab: Floor:Floor:Floor:My first floor (3)
Type - PredefinedType: FLOOR; Material: Ceramic tiles 5 mm, cement mortar 50 mm, Reinforced Concrete 2% 150 mm
Type - Pset_ElementShading - Roughness: 304.8 mm
Type - Pset_ProductRequirements - Category: Floors
Type - Pset_SlabCommon - IsExternal: no; ThermalTransmittance: 4.60799 kg/K/s3
Pset_QuantityTakeOff - Reference: Floor:Floor:My first floor; sets with these values: 2
Pset_SlabCommon - LoadBearing: no; PitchAngle: 0 deg; Reference: Floor:Floor:My first floor
Name (Floor:Floor:Floor:My first floor:...) | In
336751 | Level 2
336793 | Level 2
336801 | Top

# IfcSlab: Floor:Floor:Floor:My first floor with insulation (2)
In: Level 2
Type - PredefinedType: FLOOR; Material: Ceramic tiles 5 mm, unreinforced concrete (gross beton) (C12/15) 50 mm, Reinforced Concrete 2% 150 mm, Air 10 mm, FIBRAN GEO B-570 100 mm
Type - Pset_ElementShading - Roughness: 304.8 mm
Type - Pset_ProductRequirements - Category: Floors
Type - Pset_SlabCommon - IsExternal: no; ThermalTransmittance: 0.286636 kg/K/s3
Pset_QuantityTakeOff - Reference: Floor:Floor:My first floor with insulation; sets with these values: 2
Pset_SlabCommon - LoadBearing: no; PitchAngle: 0 deg; Reference: Floor:Floor:My first floor with insulation
Name (Floor:Floor:Floor:My first floor with insulation:...)
336771
336778

# IfcSlab: Floor:Floor:Floor:My metal deck floor (3)
Type - PredefinedType: FLOOR; Material: Exterior Tread Stair 50 mm
Type - Pset_ElementShading - Roughness: 304.8 mm
Type - Pset_ProductRequirements - Category: Floors
Type - Pset_SlabCommon - IsExternal: no
Pset_QuantityTakeOff - Reference: Floor:Floor:My metal deck floor; sets with these values: 2
Pset_SlabCommon - LoadBearing: no; PitchAngle: 0 deg; Reference: Floor:Floor:My metal deck floor
Name (Floor:Floor:Floor:My metal deck floor:...) | In
336809 | Level 2
336818 | Top
336825 | Level 1

# IfcStair: Assembled Stair:Stair:1026555 Run 1:Stair:1026555 Run 1 : Assembled Stair:Stair:1026555 Run 1:321465:Stair:1026555 Run 1:Stair:1026555 Run 1 : Assembled Stair:Stair:1026555 Run 1:321465 : Assembled Stair:Stair:1026555 Run 1:Stair:1026555 Run 1 : Assembled Stair:Stair:1026555 Run 1:321465 (2)
In: Level 1
Name (Assembled Stair:Stair:1026555 Run 1:Stair:1026555 Run 1 : Assembled Stair:Stair:1026555 Run 1:321465:Stair:1026555 Run 1:Stair:1026555 Run 1 : Assembled Stair:Stair:1026555 Run 1:321465 : Assembled Stair:Stair:1026555 Run 1:Stair:1026555 Run 1 : Assembled Stair:Stair:1026555 Run 1:321465:...)
321319 | Material: Oak Flooring
321319 | Pset_ProductRequirements - Category: Stairs; Pset_QuantityTakeOff - Reference: Stair:1026555 Run 1:Stair:1026555 Run 1 : Assembled Stair:Stair:1026555 Run 1:321465 : Assembled Stair:Stair:1026555 Run 1:Stair:1026555 Run 1 : Assembled Stair:Stair:1026555 Run 1:321465; Pset_StairCommon - Reference: Stair:1026555 Run 1:Stair:1026555 Run 1 : Assembled Stair:Stair:1026555 Run 1:321465 : Assembled Stair:Stair:1026555 Run 1:Stair:1026555 Run 1 : Assembled Stair:Stair:1026555 Run 1:321465; IsExternal: no

# IfcStair: Assembled Stair:Stair:1027112 Run 1:Stair:1027112 Run 1 : Assembled Stair:Stair:1027112 Run 1:321865:Stair:1027112 Run 1:Stair:1027112 Run 1 : Assembled Stair:Stair:1027112 Run 1:321865 : Assembled Stair:Stair:1027112 Run 1:Stair:1027112 Run 1 : Assembled Stair:Stair:1027112 Run 1:321865 (2)
In: Level 1
Name (Assembled Stair:Stair:1027112 Run 1:Stair:1027112 Run 1 : Assembled Stair:Stair:1027112 Run 1:321865:Stair:1027112 Run 1:Stair:1027112 Run 1 : Assembled Stair:Stair:1027112 Run 1:321865 : Assembled Stair:Stair:1027112 Run 1:Stair:1027112 Run 1 : Assembled Stair:Stair:1027112 Run 1:321865:...)
321663 | Material: Exterior Tread Stair
321663 | Pset_ProductRequirements - Category: Stairs; Pset_QuantityTakeOff - Reference: Stair:1027112 Run 1:Stair:1027112 Run 1 : Assembled Stair:Stair:1027112 Run 1:321865 : Assembled Stair:Stair:1027112 Run 1:Stair:1027112 Run 1 : Assembled Stair:Stair:1027112 Run 1:321865; Pset_StairCommon - IsExternal: no; Reference: Stair:1027112 Run 1:Stair:1027112 Run 1 : Assembled Stair:Stair:1027112 Run 1:321865 : Assembled Stair:Stair:1027112 Run 1:Stair:1027112 Run 1 : Assembled Stair:Stair:1027112 Run 1:321865

# IfcWall: Basic Wall:My exterior wall 280mm:1026504, Basic Wall:My exterior wall 280mm:1026504:My exterior wall 280mm:1026504 : Basic Wall:My exterior wall 280mm:1026504:324654
In: Level 1
Type - Material: Finishing Coating
Type - Pset_ElementShading - Roughness: 304.8 mm
Type - Pset_ProductRequirements - Category: Walls
Type - Pset_QuantityTakeOff - Reference: My exterior wall 280mm
Type - Pset_ReinforcementBarPitchOfWall - Reference: My exterior wall 280mm
Type - Pset_WallCommon - Reference: My exterior wall 280mm; ThermalTransmittance: 0.201157 kg/K/s3; IsExternal: yes; ExtendToStructure: no; LoadBearing: no
Pset_QuantityTakeOff - sets with these values: 2

# IfcWall: Basic Wall:My exterior wall 280mm:1026505, Basic Wall:My exterior wall 280mm:1026505:My exterior wall 280mm:1026505 : Basic Wall:My exterior wall 280mm:1026505:324743
In: Level 1
Type - Material: Finishing Coating
Type - Pset_ElementShading - Roughness: 304.8 mm
Type - Pset_ProductRequirements - Category: Walls
Type - Pset_QuantityTakeOff - Reference: My exterior wall 280mm
Type - Pset_ReinforcementBarPitchOfWall - Reference: My exterior wall 280mm
Type - Pset_WallCommon - Reference: My exterior wall 280mm; IsExternal: yes; ExtendToStructure: no; LoadBearing: no; ThermalTransmittance: 0.201157 kg/K/s3
Pset_QuantityTakeOff - sets with these values: 2

# IfcWall: Basic Wall:My exterior wall 280mm:1026509, Basic Wall:My exterior wall 280mm:1026509:My exterior wall 280mm:1026509 : Basic Wall:My exterior wall 280mm:1026509:324874
In: Level 1
Type - Material: Finishing Coating
Type - Pset_ElementShading - Roughness: 304.8 mm
Type - Pset_ProductRequirements - Category: Walls
Type - Pset_QuantityTakeOff - Reference: My exterior wall 280mm
Type - Pset_ReinforcementBarPitchOfWall - Reference: My exterior wall 280mm
Type - Pset_WallCommon - Reference: My exterior wall 280mm; IsExternal: yes; LoadBearing: no; ThermalTransmittance: 0.201157 kg/K/s3; ExtendToStructure: yes
Pset_QuantityTakeOff - sets with these values: 2

# IfcWall: Basic Wall:My exterior wall 280mm:1027084, Basic Wall:My exterior wall 280mm:1027084:My exterior wall 280mm:1027084 : Basic Wall:My exterior wall 280mm:1027084:324894
In: Level 1
Type - Material: Finishing Coating
Type - Pset_ElementShading - Roughness: 304.8 mm
Type - Pset_ProductRequirements - Category: Walls
Type - Pset_QuantityTakeOff - Reference: My exterior wall 280mm
Type - Pset_ReinforcementBarPitchOfWall - Reference: My exterior wall 280mm
Type - Pset_WallCommon - Reference: My exterior wall 280mm; IsExternal: yes; ExtendToStructure: no; LoadBearing: no; ThermalTransmittance: 0.201157 kg/K/s3
Pset_QuantityTakeOff - sets with these values: 2

# IfcWall: Curtain Wall:My Curtain Wall:1027155:My Curtain Wall:1027155 : Curtain Wall:My Curtain Wall:1027155:326742, Curtain Wall:My Curtain Wall:1027155:My Curtain Wall:1027155 : Curtain Wall:My Curtain Wall:1027155:326742:My Curtain Wall:1027155:My Curtain Wall:1027155 : Curtain Wall:My Curtain Wall:1027155:326742 : Curtain Wall:My Curtain Wall:1027155:My Curtain Wall:1027155 : Curtain Wall:My Curtain Wall:1027155:326742:326081
In: Level 2
Type - Material: Default Wall
Type - Pset_ProductRequirements - Category: Walls
Type - Pset_QuantityTakeOff - Reference: My Curtain Wall:1027155 : Curtain Wall:My Curtain Wall:1027155
Type - Pset_ReinforcementBarPitchOfWall - Reference: My Curtain Wall:1027155 : Curtain Wall:My Curtain Wall:1027155
Type - Pset_WallCommon - IsExternal: no; Reference: My Curtain Wall:1027155 : Curtain Wall:My Curtain Wall:1027155
Pset_QuantityTakeOff - sets with these values: 2

# IfcWall: Curtain Wall:My Curtain Wall:1027565:My Curtain Wall:1027565 : Curtain Wall:My Curtain Wall:1027565:327064, Curtain Wall:My Curtain Wall:1027565:My Curtain Wall:1027565 : Curtain Wall:My Curtain Wall:1027565:327064:My Curtain Wall:1027565:My Curtain Wall:1027565 : Curtain Wall:My Curtain Wall:1027565:327064 : Curtain Wall:My Curtain Wall:1027565:My Curtain Wall:1027565 : Curtain Wall:My Curtain Wall:1027565:327064:326388
In: Level 2
Type - Material: Default Wall
Type - Pset_ProductRequirements - Category: Walls
Type - Pset_QuantityTakeOff - Reference: My Curtain Wall:1027565 : Curtain Wall:My Curtain Wall:1027565
Type - Pset_ReinforcementBarPitchOfWall - Reference: My Curtain Wall:1027565 : Curtain Wall:My Curtain Wall:1027565
Type - Pset_WallCommon - IsExternal: no; Reference: My Curtain Wall:1027565 : Curtain Wall:My Curtain Wall:1027565
Pset_QuantityTakeOff - sets with these values: 2

# IfcWallStandardCase: Basic Wall:Basic Wall:Basic Wall:Generic - 300mm, Basic Wall:Generic - 300mm:1027104
In: Level 1
Type - PredefinedType: STANDARD; Material: Default Wall 300 mm
Type - Pset_ProductRequirements - Category: Walls
Type - Pset_WallCommon - IsExternal: yes
Pset_QuantityTakeOff - Reference: Generic - 300mm; sets with these values: 2
Pset_WallCommon - ExtendToStructure: no; LoadBearing: no; Reference: Generic - 300mm

# IfcWallStandardCase: Basic Wall:Basic Wall:Basic Wall:My exterior wall 280mm (7)
Type - PredefinedType: STANDARD; Material: Finishing Coating 10 mm, Finishing Coating 10 mm, FIBRAN GEO BP Etics 160 mm, Lightweight Perlite Concrete 90 mm, Finishing Coating 10 mm
Type - Pset_ProductRequirements - Category: Walls
Type - Pset_WallCommon - IsExternal: yes; ThermalTransmittance: 0.2125 kg/K/s3
Pset_QuantityTakeOff - Reference: My exterior wall 280mm; sets with these values: 2
Pset_WallCommon - Reference: My exterior wall 280mm; ExtendToStructure: no; LoadBearing: no
Name (Basic Wall:My exterior wall 280mm:...) | In
1026547 | Level 2
1026545 | Level 2
1026546 | Level 2
1026548 | Level 2
1026675 | Level 1
1027070 | Level 1
1027299 | Level 1

# IfcWallStandardCase: Basic Wall:Basic Wall:Basic Wall:My exterior wall HALL 220 mm (3)
In: Level 1
Type - PredefinedType: STANDARD; Material: Finishing Coating 10 mm, Finishing Coating 10 mm, FIBRAN GEO BP Etics 100 mm, Lightweight Perlite Concrete 90 mm, Finishing Coating 10 mm
Type - Pset_ProductRequirements - Category: Walls
Type - Pset_WallCommon - IsExternal: yes; ThermalTransmittance: 0.34 kg/K/s3
Pset_QuantityTakeOff - Reference: My exterior wall HALL 220 mm; sets with these values: 2
Pset_WallCommon - LoadBearing: no; ExtendToStructure: yes; Reference: My exterior wall HALL 220 mm
Name (Basic Wall:My exterior wall HALL 220 mm:...)
1026508
1026507
1026506

# IfcWallStandardCase: Basic Wall:Basic Wall:Basic Wall:My glass wall (2)
In: Level 1
Type - PredefinedType: STANDARD; Material: Glass, Clear Glazing 50 mm
Type - Pset_ProductRequirements - Category: Walls
Type - Pset_WallCommon - IsExternal: no; ThermalTransmittance: 22 kg/K/s3
Pset_QuantityTakeOff - Reference: My glass wall; sets with these values: 2
Pset_WallCommon - ExtendToStructure: no; LoadBearing: no; Reference: My glass wall
Name (Basic Wall:My glass wall:...)
1027380
1027381

# IfcWallStandardCase: Basic Wall:Basic Wall:Basic Wall:My interior wall 80mm (21)
Type - PredefinedType: STANDARD; Material: Steel, Paint Finish, Ivory, Matte 1 mm, FIBRAN gyps SUPER 15 mm, FIBRAN GEO B-570 50 mm, FIBRAN gyps SUPER 15 mm, Steel, Paint Finish, Ivory, Matte 1 mm
Type - Pset_ProductRequirements - Category: Walls
Type - Pset_WallCommon - IsExternal: no; ThermalTransmittance: 0.68 kg/K/s3
Pset_QuantityTakeOff - Reference: My interior wall 80mm; sets with these values: 2
Pset_WallCommon - LoadBearing: no; Reference: My interior wall 80mm
Name (Basic Wall:My interior wall 80mm:...) | In | ExtendToStructure
1026527 | Level 1 | yes
1026528 | Level 1 | yes
1026529 | Level 1 | yes
1026549 | Level 2 | yes
1026552 | Level 2 | yes
1026553 | Level 2 | yes
1026661 | Level 1 | yes
1026665 | Level 1 | yes
1026668 | Level 2 | yes
1026670 | Level 2 | yes
1026526 | Level 1 | yes
1026530 | Level 1 | yes
1026550 | Level 2 | yes
1026551 | Level 2 | yes
1026662 | Level 2 | yes
1026664 | Level 1 | yes
1026666 | Level 1 | yes
1026667 | Level 1 | yes
1026669 | Level 2 | yes
1026698 | Level 1 | no
1027359 | Level 1 | no
